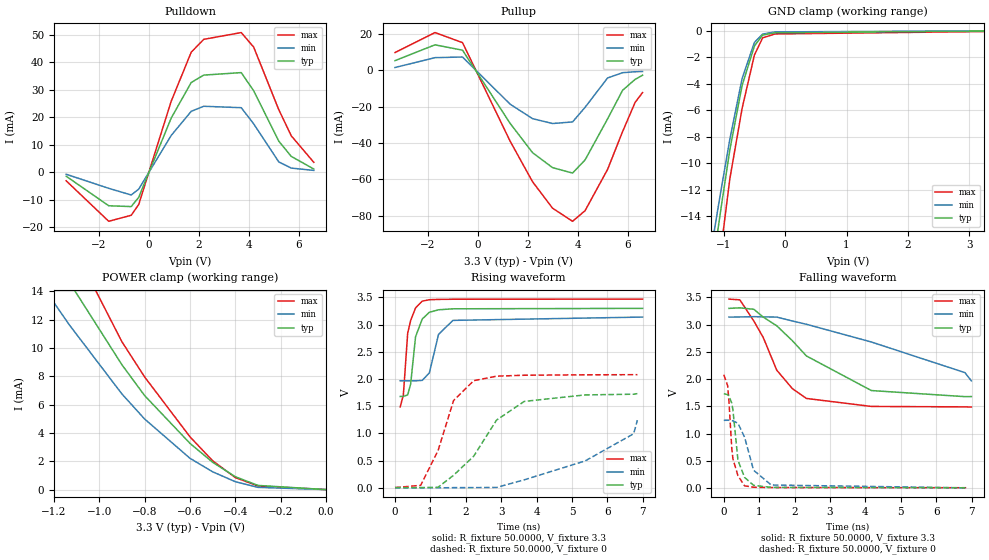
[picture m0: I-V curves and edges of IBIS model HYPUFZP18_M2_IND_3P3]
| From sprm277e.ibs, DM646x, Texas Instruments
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|Driver model in Slow Mode of operation, 1P8V +/-5% Operation
|   Model Cell HYPUFZP18_M2_IND_3P3
[Model]   HYPUFZP18_M2_IND_3P3
Model_type   I/O
Polarity   Non-Inverting
Enable   Active-Low
Vinl =  0.8V
Vinh =  2V
Cref =  10.0000pF
Rref =  50.0000
Vref =  1.5V
Vmeas =  1.65
C_comp   1.727272p   1.679637p   1.767235p
[Model Spec]
Vinl   0.8V   0.8V   0.8V
Vinh   2V   2V   2V
[Temperature Range]   25   125   -40
[Voltage Range]   3.3   3.14   3.47
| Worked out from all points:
|   slope of the pulldown table from 0 to 0.495 V, typ, clamps not added: 44 ohm
|   slope of the pullup table from 0 to 0.495 V, typ, clamps not added: 42.8 ohm
|   GND clamp passes 1 mA (typ) near -0.48 V on its own axis
|   POWER clamp passes 1 mA (typ) near -0.41 V on its own axis
|   rising waveform, R_fixture 50.0000, V_fixture 3.3: 20-80 % time 223ps typ, 314ps min, 181ps max; typ from 1.68 V to 3.3 V
|   rising waveform, R_fixture 50.0000, V_fixture 0: 20-80 % time 1.22ns typ, 2.54ns min, 685ps max; typ from 0.003 V to 1.73 V
|   falling waveform, R_fixture 50.0000, V_fixture 3.3: 20-80 % time 1.87ns typ, 3.47ns min, 1.01ns max; typ from 3.3 V to 1.68 V
|   falling waveform, R_fixture 50.0000, V_fixture 0: 20-80 % time 204ps typ, 362ps min, 167ps max; typ from 1.73 V to 0.003 V
[POWER_clamp]
|   voltage   I(typ)   I(min)   I(max)
-3.3V     86.16mA    64.93mA    104.3mA
-1.4V     22.2mA     18mA       26.83mA
-1.367V   21.21mA    17.19mA    25.68mA
-1.233V   17.39mA    13.98mA    21.08mA
-1.133V   14.68mA    11.66mA    17.73mA
-900mV    8.817mA    6.754mA    10.44mA
-800mV    6.639mA    4.986mA    7.957mA
-600mV    3.265mA    2.21mA     3.725mA
-500mV    1.929mA    1.256mA    2.033mA
-400mV    907.2uA    556.6uA    845.5uA
-300mV    294.6uA    156.7uA    257.4uA
0V        111.6nA    200.9nA    235nA
[Pulldown]
|   voltage   I(typ)   I(min)   I(max)
-3.3V     -1.512mA   -788.5uA   -3.18mA
-1.6V     -12.28mA   -5.92mA    -17.95mA
-700mV    -12.58mA   -8.352mA   -15.75mA
-400mV    -9.19mA    -6.204mA   -11.82mA
900mV     19.74mA    13.39mA    25.89mA
1.7V      32.7mA     22.18mA    43.75mA
2.2V      35.39mA    24.02mA    48.44mA
3.7V      36.3mA     23.5mA     50.91mA
4.2V      29.62mA    17.57mA    45.56mA
5.2V      11.29mA    3.716mA    22.78mA
5.7V      5.731mA    1.467mA    13.24mA
6.6V      1.129mA    616.6uA    3.57mA
[Pullup]
|   voltage   I(typ)   I(min)   I(max)
-3.3V     5.396mA    1.593mA    9.847mA
-1.7V     14.1mA     7.028mA    20.86mA
-600mV    11.14mA    7.391mA    15.31mA
1.3V      -29.12mA   -18.58mA   -38.91mA
2.2V      -45.34mA   -26.59mA   -61.37mA
3V        -53.59mA   -29.28mA   -75.95mA
3.8V      -56.59mA   -28.4mA    -83.18mA
4.3V      -49.37mA   -20.37mA   -77.34mA
5.2V      -26.74mA   -4.177mA   -54.59mA
5.8V      -10.98mA   -1.259mA   -33.78mA
6.3V      -4.973mA   -743uA     -17.68mA
6.6V      -2.651mA   -591uA     -12.21mA
[GND_clamp]
|   voltage   I(typ)   I(min)   I(max)
-3.3V     -101.9mA   -78.12mA   -120.9mA
-1.3V     -22.23mA   -19.37mA   -26.67mA
-1.233V   -19.8mA    -17.43mA   -23.98mA
-1.167V   -17.45mA   -15.5mA    -21.31mA
-1.1V     -15.2mA    -13.6mA    -18.66mA
-1.033V   -13.07mA   -11.75mA   -16.08mA
-900mV    -8.978mA   -8.176mA   -11.17mA
-700mV    -4.111mA   -3.59mA    -5.844mA
-500mV    -1.141mA   -866.9uA   -1.82mA
-366.7mV  -309.2uA   -237.7uA   -524.9uA
-166.7mV  -140.6uA   -73.41uA   -228.8uA
3.233V    -8.734uA   10uA       -45.21uA
[Ramp]
| variable   typ   min   max
dV/dt_f 0.98441839/1.9020411n 0.74512477/3.6718234n  1.2012952/1.0170093n
dV/dt_r  1.0409321/1.2292789n 0.75500684/2.5921283n  1.2504128/0.6862581n
R_load = 50
[Rising Waveform]
R_fixture = 50.0000
V_fixture = 3.3
V_fixture_min = 3.14
V_fixture_max = 3.47
|   time   V(typ)   V(min)   V(max)
146.9ps   1.68V      1.968V     1.487V
236.2ps   1.68V      1.968V     1.706V
358.8ps   1.709V     1.968V     2.845V
442.2ps   1.908V     1.968V     3.077V
581.3ps   2.779V     1.968V     3.309V
769.9ps   3.104V     1.975V     3.433V
971.3ps   3.228V     2.114V     3.459V
1.23ns    3.274V     2.821V     3.465V
1.637ns   3.292V     3.079V     3.468V
6.996ns   3.3V       3.14V      3.47V
[Rising Waveform]
R_fixture = 50.0000
V_fixture = 0
V_fixture_min = 0
V_fixture_max = 0
|   time   V(typ)   V(min)   V(max)
95.49fs   3.146mV    1.893mV    4.431mV
724.9ps   2.755mV    1.675mV    44.55mV
1.216ns   9.836mV    -1.558mV   683.1mV
1.656ns   230.3mV    2.632mV    1.605V
2.224ns   581.3mV    3.378mV    1.97V
2.872ns   1.247V     6.476mV    2.053V
3.654ns   1.589V     146.8mV    2.07V
5.371ns   1.708V     493.3mV    2.078V
6.744ns   1.721V     993.9mV    2.08V
6.849ns   1.732V     1.243V     2.081V
[Falling Waveform]
R_fixture = 50.0000
V_fixture = 3.3
V_fixture_min = 3.14
V_fixture_max = 3.47
|   time   V(typ)   V(min)   V(max)
146.9ps   3.3V       3.14V      3.47V
453.3ps   3.31V      3.142V     3.457V
850.2ps   3.283V     3.148V     3.066V
1.114ns   3.14V      3.144V     2.766V
1.496ns   2.98V      3.14V      2.165V
1.938ns   2.706V     3.068V     1.825V
2.334ns   2.426V     3.008V     1.645V
4.171ns   1.79V      2.682V     1.498V
6.815ns   1.678V     2.119V     1.49V
6.996ns   1.68V      1.968V     1.487V
[Falling Waveform]
R_fixture = 50.0000
V_fixture = 0
V_fixture_min = 0
V_fixture_max = 0
|   time   V(typ)   V(min)   V(max)
95.49fs   1.732V     1.243V     2.081V
109.4ps   1.714V     1.244V     1.878V
144.4ps   1.693V     1.244V     1.603V
224.4ps   1.56V      1.238V     739.2mV
257.7ps   1.436V     1.234V     535.1mV
400.6ps   507.2mV    1.188V     224.3mV
587.6ps   193.6mV    932.8mV    39.78mV
841.9ps   48.86mV    325.8mV    13.44mV
1.34ns    11.05mV    54.58mV    7.764mV
6.849ns   3.146mV    1.893mV    4.431mV
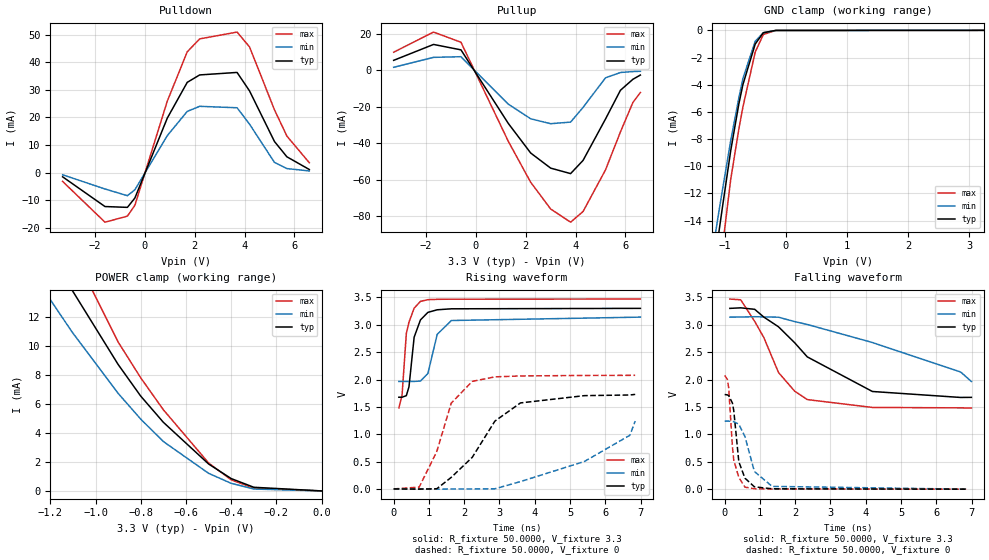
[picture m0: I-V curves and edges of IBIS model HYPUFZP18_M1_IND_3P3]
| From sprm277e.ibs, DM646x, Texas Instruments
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|   Model Cell HYPUFZP18_M1_IND_3P3
[Model]   HYPUFZP18_M1_IND_3P3
Model_type   I/O
Polarity   Non-Inverting
Enable   Active-Low
Vinl =  0.8V
Vinh =  2V
Cref =  10.0000pF
Rref =  50.0000
Vref =  1.5V
Vmeas =  1.65
C_comp   1.727272p   1.679637p   1.767235p
[Model Spec]
Vinl   0.8V   0.8V   0.8V
Vinh   2V   2V   2V
[Temperature Range]   25   125   -40
[Voltage Range]   3.3   3.14   3.47
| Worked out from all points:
|   slope of the pulldown table from 0 to 0.495 V, typ, clamps not added: 44 ohm
|   slope of the pullup table from 0 to 0.495 V, typ, clamps not added: 42.8 ohm
|   GND clamp passes 1 mA (typ) near -0.50 V on its own axis
|   POWER clamp passes 1 mA (typ) near -0.41 V on its own axis
|   rising waveform, R_fixture 50.0000, V_fixture 3.3: 20-80 % time 225ps typ, 315ps min, 183ps max; typ from 1.68 V to 3.3 V
|   rising waveform, R_fixture 50.0000, V_fixture 0: 20-80 % time 1.22ns typ, 2.49ns min, 683ps max; typ from 0 V to 1.73 V
|   falling waveform, R_fixture 50.0000, V_fixture 3.3: 20-80 % time 1.87ns typ, 3.46ns min, 1ns max; typ from 3.3 V to 1.68 V
|   falling waveform, R_fixture 50.0000, V_fixture 0: 20-80 % time 203ps typ, 361ps min, 165ps max; typ from 1.73 V to 0 V
[POWER_clamp]
|   voltage   I(typ)   I(min)   I(max)
-3.3V     86.16mA    64.93mA    104.3mA
-1.367V   21.2mA     17.18mA    25.66mA
-1.233V   17.37mA    13.97mA    21.04mA
-1.133V   14.66mA    11.65mA    17.64mA
-1.1V     13.77mA    10.89mA    16.52mA
-900mV    8.73mA     6.735mA    10.28mA
-800mV    6.543mA    4.955mA    7.805mA
-700mV    4.738mA    3.41mA     5.602mA
-500mV    1.861mA    1.216mA    1.931mA
-400mV    852uA      523.7uA    761.9uA
-300mV    252.5uA    131.8uA    194.2uA
0V        112.1nA    201.3nA    235.2nA
[Pulldown]
|   voltage   I(typ)   I(min)   I(max)
-3.3V     -1.512mA   -788.5uA   -3.18mA
-1.6V     -12.28mA   -5.92mA    -17.95mA
-700mV    -12.58mA   -8.352mA   -15.76mA
-400mV    -9.19mA    -6.205mA   -11.82mA
900mV     19.74mA    13.39mA    25.89mA
1.7V      32.7mA     22.18mA    43.75mA
2.2V      35.39mA    24.02mA    48.45mA
3.7V      36.3mA     23.5mA     50.91mA
4.2V      29.62mA    17.57mA    45.56mA
5.2V      11.29mA    3.716mA    22.78mA
5.7V      5.731mA    1.467mA    13.24mA
6.6V      1.129mA    616.6uA    3.57mA
[Pullup]
|   voltage   I(typ)   I(min)   I(max)
-3.3V     5.396mA    1.593mA    9.847mA
-1.7V     14.1mA     7.028mA    20.86mA
-600mV    11.14mA    7.391mA    15.31mA
1.3V      -29.12mA   -18.58mA   -38.91mA
2.2V      -45.34mA   -26.59mA   -61.37mA
3V        -53.59mA   -29.28mA   -75.95mA
3.8V      -56.59mA   -28.4mA    -83.18mA
4.3V      -49.37mA   -20.37mA   -77.34mA
5.2V      -26.74mA   -4.177mA   -54.59mA
5.8V      -10.98mA   -1.259mA   -33.78mA
6.3V      -4.973mA   -743uA     -17.68mA
6.6V      -2.651mA   -591uA     -12.21mA
[GND_clamp]
|   voltage   I(typ)   I(min)   I(max)
-3.3V     -101.7mA   -78.06mA   -120.7mA
-1.233V   -19.67mA   -17.36mA   -23.77mA
-1.167V   -17.33mA   -15.44mA   -21.11mA
-1.1V     -15.07mA   -13.53mA   -18.46mA
-1.033V   -12.94mA   -11.68mA   -15.87mA
-900mV    -8.85mA    -8.113mA   -10.96mA
-766.7mV  -5.397mA   -4.953mA   -7.245mA
-700mV    -3.976mA   -3.526mA   -5.621mA
-500mV    -1.005mA   -799.5uA   -1.597mA
-366.7mV  -173.3uA   -170.2uA   -302.3uA
-166.7mV  -4.974uA   -6.036uA   -6.587uA
3.233V    79.94nA    2.44uA     205.4nA
[Ramp]
| variable   typ   min   max
dV/dt_f 0.98699288/1.8980343n 0.74658914/3.6696309n   1.204652/1.0122786n
dV/dt_r  1.0418022/1.2286872n 0.75518748/2.5917648n  1.2520798/0.68561525n
R_load = 50
[Rising Waveform]
R_fixture = 50.0000
V_fixture = 3.3
V_fixture_min = 3.14
V_fixture_max = 3.47
|   time   V(typ)   V(min)   V(max)
147ps     1.676V     1.965V     1.481V
238ps     1.676V     1.965V     1.711V
359.3ps   1.705V     1.965V     2.839V
434.3ps   1.865V     1.965V     3.047V
580.9ps   2.773V     1.965V     3.304V
760.5ps   3.09V      1.971V     3.428V
971.3ps   3.227V     2.111V     3.459V
1.235ns   3.274V     2.825V     3.465V
1.637ns   3.292V     3.078V     3.468V
6.996ns   3.3V       3.14V      3.47V
[Rising Waveform]
R_fixture = 50.0000
V_fixture = 0
V_fixture_min = 0
V_fixture_max = 0
|   time   V(typ)   V(min)   V(max)
0s        38.03uV    22.53uV    59.66uV
724.4ps   -3.316mV   -195.8uV   33.46mV
1.224ns   3.693mV    -4.135mV   685.1mV
1.632ns   210.9mV    -771.5uV   1.567V
2.229ns   578.1mV    33.73uV    1.966V
2.871ns   1.24V      3.076mV    2.048V
3.596ns   1.572V     134.1mV    2.065V
5.411ns   1.705V     502.7mV    2.074V
6.7ns     1.717V     981.4mV    2.076V
6.849ns   1.728V     1.24V      2.077V
[Falling Waveform]
R_fixture = 50.0000
V_fixture = 3.3
V_fixture_min = 3.14
V_fixture_max = 3.47
|   time   V(typ)   V(min)   V(max)
147ps     3.3V       3.14V      3.47V
453.3ps   3.31V      3.142V     3.457V
850.2ps   3.283V     3.148V     3.063V
1.108ns   3.142V     3.144V     2.77V
1.525ns   2.964V     3.139V     2.13V
1.982ns   2.674V     3.059V     1.79V
2.343ns   2.414V     3.006V     1.635V
4.188ns   1.783V     2.677V     1.492V
6.692ns   1.674V     2.138V     1.484V
6.996ns   1.676V     1.965V     1.481V
[Falling Waveform]
R_fixture = 50.0000
V_fixture = 0
V_fixture_min = 0
V_fixture_max = 0
|   time   V(typ)   V(min)   V(max)
0s        1.728V     1.24V      2.077V
75.14ps   1.721V     1.242V     2.002V
112.4ps   1.709V     1.242V     1.855V
218.9ps   1.572V     1.236V     779.8mV
257.1ps   1.435V     1.232V     529.4mV
400.6ps   501.1mV    1.186V     214.3mV
573.9ps   200.9mV    960.8mV    36.89mV
842.1ps   42.86mV    322.7mV    7.839mV
1.343ns   6.854mV    50.74mV    2.674mV
6.849ns   38.03uV    22.53uV    59.66uV
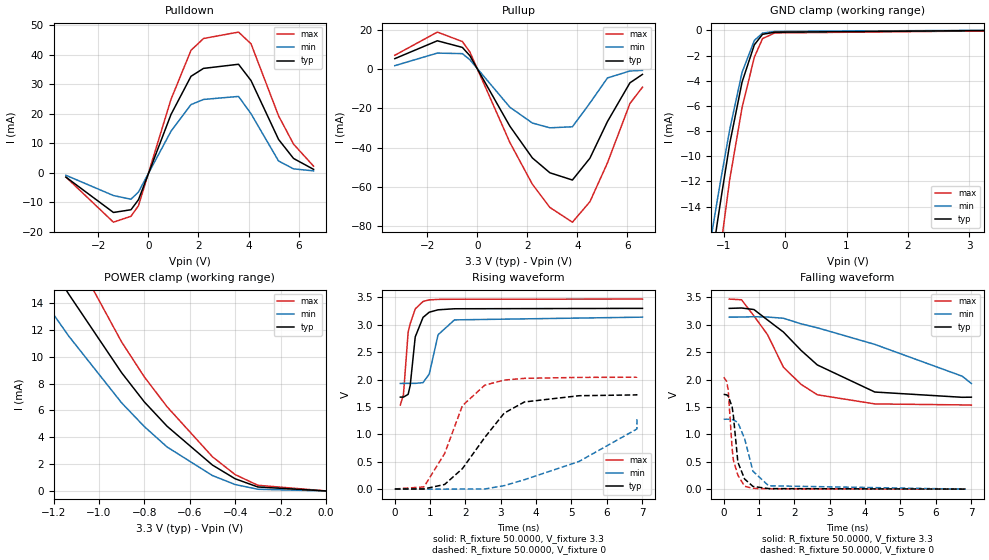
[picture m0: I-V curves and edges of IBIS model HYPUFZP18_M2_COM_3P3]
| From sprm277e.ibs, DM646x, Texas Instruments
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|   Model Cell HYPUFZP18_M2_COM_3P3
[Model]   HYPUFZP18_M2_COM_3P3
Model_type   I/O
Polarity   Non-Inverting
Enable   Active-Low
Vinl =  0.8V
Vinh =  2V
Cref =  10.0000pF
Rref =  50.0000
Vref =  1.5V
Vmeas =  1.65
C_comp   1.727272p   1.681011p   1.768042p
[Model Spec]
Vinl   0.8V   0.8V   0.8V
Vinh   2V   2V   2V
[Temperature Range]   25   105   0
[Voltage Range]   3.3   3.14   3.47
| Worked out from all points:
|   slope of the pulldown table from 0 to 0.495 V, typ, clamps not added: 44 ohm
|   slope of the pullup table from 0 to 0.495 V, typ, clamps not added: 42.8 ohm
|   GND clamp passes 1 mA (typ) near -0.48 V on its own axis
|   POWER clamp passes 1 mA (typ) near -0.41 V on its own axis
|   rising waveform, R_fixture 50.0000, V_fixture 3.3: 20-80 % time 223ps typ, 309ps min, 188ps max; typ from 1.68 V to 3.3 V
|   rising waveform, R_fixture 50.0000, V_fixture 0: 20-80 % time 1.22ns typ, 2.4ns min, 842ps max; typ from 0.003 V to 1.73 V
|   falling waveform, R_fixture 50.0000, V_fixture 3.3: 20-80 % time 1.88ns typ, 3.36ns min, 1.22ns max; typ from 3.3 V to 1.68 V
|   falling waveform, R_fixture 50.0000, V_fixture 0: 20-80 % time 204ps typ, 351ps min, 171ps max; typ from 1.73 V to 0.003 V
[POWER_clamp]
|   voltage   I(typ)   I(min)   I(max)
-3.3V     86.16mA    67.13mA    105mA
-1.433V   23.25mA    19mA       28.67mA
-1.4V     22.2mA     18.14mA    27.44mA
-1.267V   18.31mA    14.78mA    22.82mA
-1.133V   14.68mA    11.55mA    18.37mA
-900mV    8.817mA    6.569mA    11.11mA
-800mV    6.639mA    4.799mA    8.503mA
-700mV    4.827mA    3.28mA     6.281mA
-500mV    1.929mA    1.146mA    2.549mA
-400mV    907.2uA    478uA      1.218mA
-300mV    294.5uA    124.1uA    421.8uA
0V        111.6nA    122.2nA    531.1nA
[Pulldown]
|   voltage   I(typ)   I(min)   I(max)
-3.3V     -1.512mA   -878.6uA   -1.478mA
-1.4V     -13.5mA    -7.754mA   -16.8mA
-700mV    -12.58mA   -9.011mA   -14.79mA
-400mV    -9.19mA    -6.568mA   -11.22mA
900mV     19.74mA    14.05mA    24.87mA
1.7V      32.7mA     23.1mA     41.52mA
2.2V      35.39mA    24.85mA    45.53mA
3.6V      36.79mA    25.88mA    47.71mA
4.1V      31.25mA    19.99mA    43.72mA
5.2V      11.29mA    3.971mA    19.31mA
5.8V      4.817mA    1.297mA    9.688mA
6.6V      1.129mA    610.1uA    2.216mA
[Pullup]
|   voltage   I(typ)   I(min)   I(max)
-3.3V     5.397mA    1.812mA    7.127mA
-1.6V     14.52mA    8.233mA    18.96mA
-600mV    11.14mA    7.955mA    14.14mA
-300mV    6.902mA    4.842mA    8.811mA
1.3V      -29.12mA   -19.41mA   -37.45mA
2.2V      -45.34mA   -27.5mA    -58.77mA
2.9V      -52.91mA   -29.94mA   -70.62mA
3.8V      -56.6mA    -29.4mA    -78.14mA
4.5V      -45.44mA   -17.28mA   -67.66mA
5.2V      -26.74mA   -4.474mA   -47.85mA
6.1V      -6.94mA    -895.2uA   -17.5mA
6.6V      -2.652mA   -585.1uA   -9.182mA
[GND_clamp]
|   voltage   I(typ)   I(min)   I(max)
-3.3V     -101.9mA   -80.83mA   -121.5mA
-1.3V     -22.23mA   -19.42mA   -27.13mA
-1.233V   -19.8mA    -17.39mA   -24.45mA
-1.167V   -17.45mA   -15.39mA   -21.82mA
-1.1V     -15.2mA    -13.41mA   -19.23mA
-1.033V   -13.07mA   -11.5mA    -16.71mA
-900mV    -8.978mA   -7.863mA   -11.83mA
-700mV    -4.111mA   -3.334mA   -6.141mA
-500mV    -1.141mA   -794.5uA   -2.129mA
-366.7mV  -309.2uA   -210.5uA   -650.5uA
-166.7mV  -140.6uA   -75.05uA   -198.7uA
3.233V    -8.733uA   9.396uA    -38.37uA
[Ramp]
| variable   typ   min   max
dV/dt_f   0.984392/1.9018313n 0.76805453/3.5496673n  1.1728981/1.2350833n
dV/dt_r  1.0409375/1.2292146n 0.77628069/2.4455529n  1.2301703/0.84780407n
R_load = 50
[Rising Waveform]
R_fixture = 50.0000
V_fixture = 3.3
V_fixture_min = 3.14
V_fixture_max = 3.47
|   time   V(typ)   V(min)   V(max)
158.4ps   1.68V      1.93V      1.535V
247.4ps   1.681V     1.931V     1.73V
379.4ps   1.731V     1.931V     2.865V
438.3ps   1.895V     1.931V     3.021V
580ps     2.779V     1.931V     3.29V
801.3ps   3.136V     1.945V     3.426V
976.5ps   3.23V      2.102V     3.455V
1.226ns   3.274V     2.818V     3.464V
1.69ns    3.293V     3.09V      3.467V
7.008ns   3.3V       3.14V      3.47V
[Rising Waveform]
R_fixture = 50.0000
V_fixture = 0
V_fixture_min = 0
V_fixture_max = 0
|   time   V(typ)   V(min)   V(max)
2.236ps   3.146mV    1.93mV     3.847mV
826.7ps   4.911mV    1.344mV    41.58mV
1.411ns   85.98mV    353.5uV    650.1mV
1.915ns   375.2mV    3.413mV    1.525V
2.548ns   944.8mV    3.815mV    1.899V
3.096ns   1.388V     64.44mV    1.991V
3.668ns   1.592V     172.7mV    2.023V
5.214ns   1.706V     506.2mV    2.04V
6.85ns    1.721V     1.099V     2.044V
6.852ns   1.732V     1.277V     2.046V
[Falling Waveform]
R_fixture = 50.0000
V_fixture = 3.3
V_fixture_min = 3.14
V_fixture_max = 3.47
|   time   V(typ)   V(min)   V(max)
158.4ps   3.3V       3.14V      3.47V
506.2ps   3.307V     3.142V     3.457V
857.7ps   3.279V     3.148V     3.162V
1.244ns   3.087V     3.142V     2.819V
1.692ns   2.868V     3.12V      2.226V
2.191ns   2.534V     3.018V     1.914V
2.651ns   2.268V     2.946V     1.724V
4.277ns   1.774V     2.643V     1.557V
6.749ns   1.678V     2.063V     1.539V
7.008ns   1.68V      1.93V      1.535V
[Falling Waveform]
R_fixture = 50.0000
V_fixture = 0
V_fixture_min = 0
V_fixture_max = 0
|   time   V(typ)   V(min)   V(max)
2.236ps   1.732V     1.277V     2.046V
84.64ps   1.722V     1.279V     1.971V
129.1ps   1.703V     1.278V     1.813V
241.5ps   1.5V       1.271V     737mV
276.7ps   1.338V     1.265V     532.2mV
403.4ps   493.2mV    1.219V     256.1mV
594.2ps   186.6mV    921.7mV    54.7mV
829.9ps   52.15mV    329.2mV    15.68mV
1.274ns   12.09mV    63.13mV    8.24mV
6.852ns   3.146mV    1.93mV     3.847mV
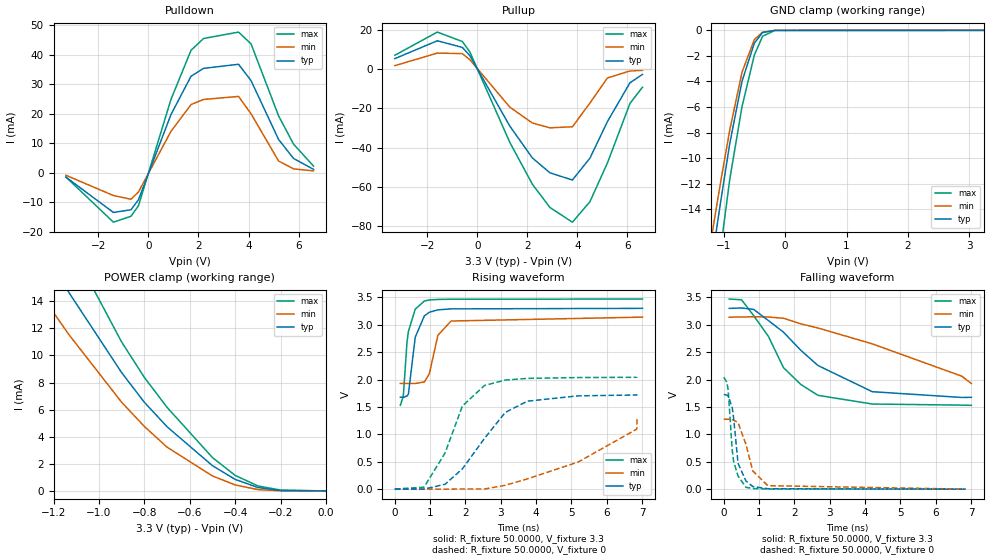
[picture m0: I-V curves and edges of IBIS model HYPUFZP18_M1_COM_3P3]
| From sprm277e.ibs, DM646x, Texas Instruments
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|   Model Cell HYPUFZP18_M1_COM_3P3
[Model]   HYPUFZP18_M1_COM_3P3
Model_type   I/O
Polarity   Non-Inverting
Enable   Active-Low
Vinl =  0.8V
Vinh =  2V
Cref =  10.0000pF
Rref =  50.0000
Vref =  1.5V
Vmeas =  1.65
C_comp   1.727272p   1.681011p   1.768042p
[Model Spec]
Vinl   0.8V   0.8V   0.8V
Vinh   2V   2V   2V
[Temperature Range]   25   105   0
[Voltage Range]   3.3   3.14   3.47
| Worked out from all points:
|   slope of the pulldown table from 0 to 0.495 V, typ, clamps not added: 44 ohm
|   slope of the pullup table from 0 to 0.495 V, typ, clamps not added: 42.8 ohm
|   GND clamp passes 1 mA (typ) near -0.50 V on its own axis
|   POWER clamp passes 1 mA (typ) near -0.41 V on its own axis
|   rising waveform, R_fixture 50.0000, V_fixture 3.3: 20-80 % time 225ps typ, 310ps min, 190ps max; typ from 1.68 V to 3.3 V
|   rising waveform, R_fixture 50.0000, V_fixture 0: 20-80 % time 1.22ns typ, 2.4ns min, 841ps max; typ from 0 V to 1.73 V
|   falling waveform, R_fixture 50.0000, V_fixture 3.3: 20-80 % time 1.87ns typ, 3.36ns min, 1.22ns max; typ from 3.3 V to 1.68 V
|   falling waveform, R_fixture 50.0000, V_fixture 0: 20-80 % time 203ps typ, 351ps min, 170ps max; typ from 1.73 V to 0 V
[POWER_clamp]
|   voltage   I(typ)   I(min)   I(max)
-3.3V     86.16mA    67.13mA    105mA
-1.4V     22.19mA    18.14mA    27.42mA
-1.267V   18.3mA     14.77mA    22.8mA
-1.133V   14.66mA    11.55mA    18.33mA
-900mV    8.73mA     6.544mA    10.99mA
-800mV    6.543mA    4.759mA    8.378mA
-700mV    4.738mA    3.23mA     6.168mA
-500mV    1.861mA    1.104mA    2.464mA
-400mV    852uA      443.1uA    1.148mA
-300mV    252.5uA    97.77uA    368.3uA
-200mV    33.02uA    10.49uA    62.16uA
0V        112.1nA    122.4nA    532.4nA
[Pulldown]
|   voltage   I(typ)   I(min)   I(max)
-3.3V     -1.512mA   -878.6uA   -1.478mA
-1.4V     -13.5mA    -7.754mA   -16.8mA
-700mV    -12.58mA   -9.011mA   -14.79mA
-400mV    -9.19mA    -6.568mA   -11.22mA
900mV     19.74mA    14.05mA    24.87mA
1.7V      32.7mA     23.1mA     41.52mA
2.2V      35.39mA    24.85mA    45.53mA
3.6V      36.79mA    25.88mA    47.71mA
4.1V      31.25mA    19.99mA    43.72mA
5.2V      11.29mA    3.971mA    19.31mA
5.8V      4.817mA    1.297mA    9.688mA
6.6V      1.129mA    610.1uA    2.216mA
[Pullup]
|   voltage   I(typ)   I(min)   I(max)
-3.3V     5.397mA    1.812mA    7.127mA
-1.6V     14.52mA    8.233mA    18.96mA
-600mV    11.14mA    7.955mA    14.14mA
-300mV    6.902mA    4.842mA    8.811mA
1.3V      -29.12mA   -19.41mA   -37.45mA
2.2V      -45.34mA   -27.5mA    -58.77mA
2.9V      -52.91mA   -29.94mA   -70.62mA
3.8V      -56.6mA    -29.4mA    -78.14mA
4.5V      -45.44mA   -17.28mA   -67.66mA
5.2V      -26.74mA   -4.474mA   -47.85mA
6.1V      -6.939mA   -895.2uA   -17.5mA
6.6V      -2.652mA   -585.1uA   -9.182mA
[GND_clamp]
|   voltage   I(typ)   I(min)   I(max)
-3.3V     -101.7mA   -80.77mA   -121.3mA
-1.3V     -22.1mA    -19.35mA   -26.96mA
-1.233V   -19.67mA   -17.33mA   -24.27mA
-1.167V   -17.33mA   -15.32mA   -21.64mA
-1.1V     -15.07mA   -13.35mA   -19.05mA
-1.033V   -12.94mA   -11.44mA   -16.53mA
-900mV    -8.849mA   -7.798mA   -11.65mA
-700mV    -3.976mA   -3.266mA   -5.954mA
-500mV    -1.005mA   -723.9uA   -1.94mA
-366.7mV  -173.3uA   -140uA     -461.5uA
-166.7mV  -4.974uA   -4.702uA   -10.03uA
3.233V    79.94nA    1.449uA    399.8nA
[Ramp]
| variable   typ   min   max
dV/dt_f 0.98696343/1.8977835n 0.76958064/3.5474193n  1.1759279/1.2301136n
dV/dt_r  1.0418135/1.2286609n 0.77649287/2.4452071n  1.2315165/0.84717372n
R_load = 50
[Rising Waveform]
R_fixture = 50.0000
V_fixture = 3.3
V_fixture_min = 3.14
V_fixture_max = 3.47
|   time   V(typ)   V(min)   V(max)
158.5ps   1.676V     1.928V     1.53V
242.7ps   1.676V     1.928V     1.697V
348ps     1.698V     1.928V     2.693V
387.2ps   1.737V     1.928V     2.88V
580.1ps   2.774V     1.928V     3.285V
837.3ps   3.162V     1.955V     3.434V
978.4ps   3.229V     2.104V     3.454V
1.221ns   3.273V     2.808V     3.463V
1.594ns   3.291V     3.069V     3.467V
7.008ns   3.3V       3.14V      3.47V
[Rising Waveform]
R_fixture = 50.0000
V_fixture = 0
V_fixture_min = 0
V_fixture_max = 0
|   time   V(typ)   V(min)   V(max)
2.154ps   38.03uV    21.16uV    59.4uV
827.1ps   -1.482mV   -578.1uV   32.76mV
1.423ns   86.82mV    -2.717mV   656.8mV
1.914ns   368.2mV    -63.3uV    1.517V
2.541ns   926.3mV    292.9uV    1.892V
3.127ns   1.399V     68.24mV    1.99V
3.754ns   1.605V     185.9mV    2.021V
5.189ns   1.702V     492.7mV    2.036V
6.85ns    1.718V     1.096V     2.041V
6.851ns   1.728V     1.275V     2.043V
[Falling Waveform]
R_fixture = 50.0000
V_fixture = 3.3
V_fixture_min = 3.14
V_fixture_max = 3.47
|   time   V(typ)   V(min)   V(max)
158.5ps   3.3V       3.14V      3.47V
506.2ps   3.307V     3.142V     3.457V
849.3ps   3.282V     3.148V     3.168V
1.267ns   3.077V     3.142V     2.789V
1.692ns   2.866V     3.12V      2.219V
2.185ns   2.534V     3.018V     1.91V
2.668ns   2.257V     2.942V     1.713V
4.207ns   1.779V     2.652V     1.554V
6.738ns   1.674V     2.062V     1.534V
7.008ns   1.676V     1.928V     1.53V
[Falling Waveform]
R_fixture = 50.0000
V_fixture = 0
V_fixture_min = 0
V_fixture_max = 0
|   time   V(typ)   V(min)   V(max)
2.154ps   1.728V     1.275V     2.043V
90.59ps   1.717V     1.276V     1.954V
129.1ps   1.7V       1.276V     1.808V
241.5ps   1.495V     1.268V     728.6mV
281.3ps   1.308V     1.262V     510.7mV
407.7ps   472.2mV    1.214V     240.8mV
630.3ps   150.2mV    820.5mV    34.45mV
824.3ps   47.91mV    333.2mV    10.65mV
1.25ns    8.222mV    63.96mV    3.812mV
6.851ns   38.03uV    21.16uV    59.4uV
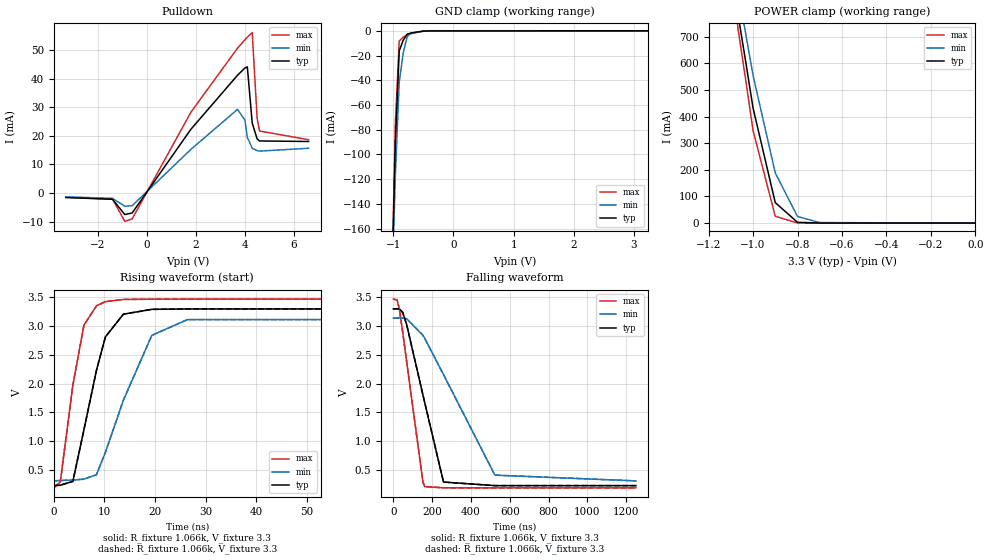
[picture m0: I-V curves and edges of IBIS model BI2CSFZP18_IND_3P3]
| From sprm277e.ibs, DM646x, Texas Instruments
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|   Model Cell BI2CSFZP18_IND_3P3
[Model]   BI2CSFZP18_IND_3P3
Model_type   I/O_open_drain
Polarity   Non-Inverting
Enable   Active-Low
Vinl =  0.99
Vinh =  2.31
Cref =  400pF
Rref =  1.066k
Vref =  1.8V
Vmeas =  1.65
C_comp   1.488594p   1.349892p   1.621248p
[Model Spec]
Vinl   0.99   0.942   1.041
Vinh   2.31   2.198   2.429
[Temperature Range]   25   125   -40
[Voltage Range]   3.3   3.14   3.47
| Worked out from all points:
|   slope of the pulldown table from 0 to 0.495 V, typ, clamps not added: 76.9 ohm
|   GND clamp passes 1 mA (typ) near -0.62 V on its own axis
|   POWER clamp passes 1 mA (typ) near -0.73 V on its own axis
|   rising waveform, R_fixture 1.066k, V_fixture 3.3: 20-80 % time 4.58ns typ, 7.2ns min, 3.21ns max; typ from 0.221 V to 3.3 V
|   rising waveform, R_fixture 1.066k, V_fixture 3.3: 20-80 % time 4.58ns typ, 7.2ns min, 3.21ns max; typ from 0.221 V to 3.3 V
|   falling waveform, R_fixture 1.066k, V_fixture 3.3: 20-80 % time 126ns typ, 253ns min, 79.7ns max; typ from 3.3 V to 0.221 V
|   falling waveform, R_fixture 1.066k, V_fixture 3.3: 20-80 % time 126ns typ, 253ns min, 79.7ns max; typ from 3.3 V to 0.221 V
[POWER_clamp]
|   voltage   I(typ)   I(min)   I(max)
-3.3V     15.05A     13.64A     16.17A
-1.067V   781.2mA    867.7mA    727.6mA
-1.033V   606.9mA    711.6mA    538mA
-1V       432.7mA    555.5mA    348.4mA
-900mV    76.75mA    188.3mA    25.46mA
-800mV    2.774mA    24.69mA    252.5uA
-700mV    66.53uA    1.695mA    2.137uA
0V        40.21nA    40.76nA    94nA
[Pulldown]
|   voltage   I(typ)   I(min)   I(max)
-3.3V     -1.585mA   -1.346mA   -1.531mA
-1.4V     -2.213mA   -1.889mA   -2.158mA
-900mV    -7.541mA   -4.635mA   -9.916mA
-600mV    -7.019mA   -4.472mA   -9.091mA
1.8V      22.32mA    15.27mA    28.29mA
3.7V      41.2mA     29.25mA    50.67mA
4V        43.73mA    25.55mA    53.59mA
4.1V      44.15mA    19.45mA    54.54mA
4.3V      24.45mA    15.65mA    56.14mA
4.5V      18.92mA    14.81mA    26.17mA
4.6V      18.2mA     14.65mA    21.68mA
6.6V      18.02mA    15.65mA    18.64mA
[GND_clamp]
|   voltage   I(typ)   I(min)   I(max)
-3.3V     -17.3A     -15.65A    -18.51A
-1.033V   -228.3mA   -233.3mA   -231.9mA
-966.7mV  -93.1mA    -119.6mA   -77.04mA
-900mV    -16.18mA   -41.41mA   -8.144mA
-833.3mV  -7.484mA   -17.78mA   -5.09mA
-766.7mV  -2.666mA   -4.584mA   -3.099mA
-700mV    -1.721mA   -1.808mA   -2.172mA
-500mV    -222.6uA   -326.8uA   -246.3uA
-366.7mV  -16.95uA   -49.29uA   -14.91uA
3.233V    39.65nA    41.75nA    88.83nA
[Ramp]
| variable   typ   min   max
dV/dt_f  1.7339576/0.13001354u  1.5510461/0.26044462u  1.8799555/81.619392n
dV/dt_r 13.711008m/1.120079n  8.3530201m/2.632613n  19.501467m/0.66262005n
R_load = 528
[Rising Waveform]
R_fixture = 1.066k
V_fixture = 3.3
V_fixture_min = 3.14
V_fixture_max = 3.47
|   time   V(typ)   V(min)   V(max)
0s        220.8mV    303.5mV    182.1mV
1.28ns    228.8mV    310.6mV    285mV
3.755ns   294mV      318.4mV    1.97V
5.955ns   1.198V     333.8mV    3.019V
8.425ns   2.232V     412.1mV    3.354V
10.19ns   2.813V     802.3mV    3.427V
13.74ns   3.208V     1.71V      3.464V
19.34ns   3.292V     2.838V     3.469V
26.35ns   3.299V     3.113V     3.47V
1.25us    3.3V       3.14V      3.47V
[Rising Waveform]
R_fixture = 1.066k
V_fixture = 3.3
V_fixture_min = 3.14
V_fixture_max = 3.47
|   time   V(typ)   V(min)   V(max)
0s        220.8mV    303.5mV    182.1mV
1.28ns    228.8mV    310.6mV    285mV
3.755ns   294mV      318.4mV    1.97V
5.955ns   1.198V     333.8mV    3.019V
8.425ns   2.232V     412.1mV    3.354V
10.19ns   2.813V     802.3mV    3.427V
13.74ns   3.208V     1.71V      3.464V
19.34ns   3.292V     2.838V     3.469V
26.35ns   3.299V     3.113V     3.47V
1.25us    3.3V       3.14V      3.47V
[Falling Waveform]
R_fixture = 1.066k
V_fixture = 3.3
V_fixture_min = 3.14
V_fixture_max = 3.47
|   time   V(typ)   V(min)   V(max)
0s        3.3V       3.14V      3.47V
19.62ns   3.302V     3.141V     3.457V
31.73ns   3.298V     3.141V     3.287V
48.39ns   3.239V     3.139V     2.896V
68.52ns   3.03V      3.129V     2.385V
152.7ns   1.799V     2.839V     281.9mV
161.7ns   1.67V      2.787V     203.6mV
258.5ns   283.3mV    2.157V     182.9mV
523.3ns   221mV      403.6mV    182.1mV
1.25us    220.8mV    303.5mV    182.1mV
[Falling Waveform]
R_fixture = 1.066k
V_fixture = 3.3
V_fixture_min = 3.14
V_fixture_max = 3.47
|   time   V(typ)   V(min)   V(max)
0s        3.3V       3.14V      3.47V
19.62ns   3.302V     3.141V     3.457V
31.73ns   3.298V     3.141V     3.287V
48.39ns   3.239V     3.139V     2.896V
68.52ns   3.03V      3.129V     2.385V
152.7ns   1.799V     2.839V     281.9mV
161.7ns   1.67V      2.787V     203.6mV
258.5ns   283.3mV    2.157V     182.9mV
523.3ns   221mV      403.6mV    182.1mV
1.25us    220.8mV    303.5mV    182.1mV
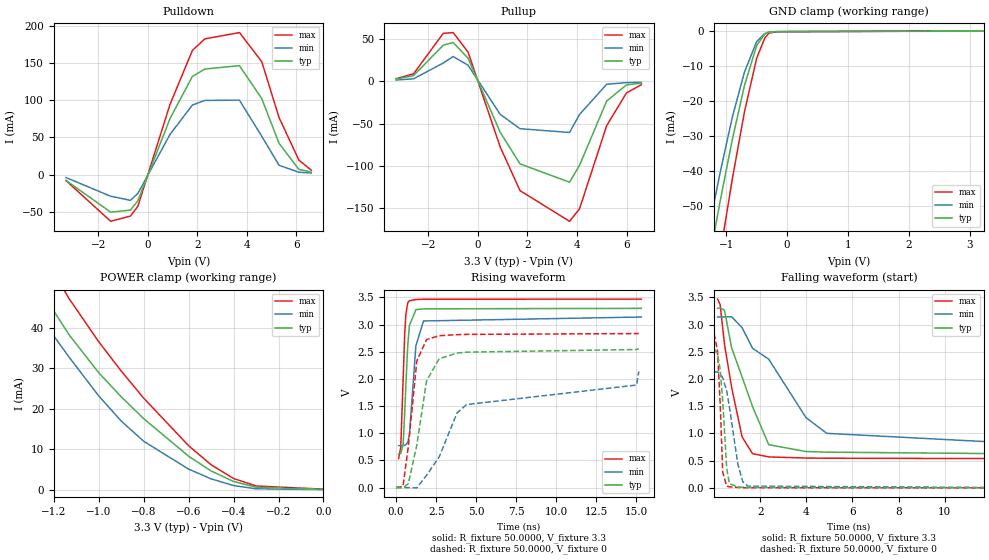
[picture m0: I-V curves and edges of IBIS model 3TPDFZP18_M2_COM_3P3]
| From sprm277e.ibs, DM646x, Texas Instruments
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|   Model Cell 3TPDFZP18_M2_COM_3P3
|BPCI33TPDFZP18_M2_COM_3P3
[Model]   3TPDFZP18_M2_COM_3P3
Model_type   I/O
Polarity   Non-Inverting
Enable   Active-Low
Vinl =  0.99V
Vinh =  1.65V
Cref =  10.0000pF
Rref =  50.0000
Vref =  1.5V
Vmeas =  1.65
C_comp   3.400798p   3.35082p   3.526617p
[Model Spec]
Vinl   0.99V   0.942V   1.041V
Vinh   1.65V   1.570V   1.735V
[Temperature Range]   25   105   0
[Voltage Range]   3.3   3.14   3.47
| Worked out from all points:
|   slope of the pulldown table from 0 to 0.495 V, typ, clamps not added: 11.5 ohm
|   slope of the pullup table from 0 to 0.495 V, typ, clamps not added: 14.2 ohm
|   GND clamp passes 1 mA (typ) near -0.38 V on its own axis
|   POWER clamp passes 1 mA (typ) near -0.32 V on its own axis
|   rising waveform, R_fixture 50.0000, V_fixture 3.3: 20-80 % time 257ps typ, 345ps min, 208ps max; typ from 0.618 V to 3.3 V
|   rising waveform, R_fixture 50.0000, V_fixture 0: 20-80 % time 905ps typ, 6.35ns min, 575ps max; typ from 0 V to 2.56 V
|   falling waveform, R_fixture 50.0000, V_fixture 3.3: 20-80 % time 1.25ns typ, 2.59ns min, 741ps max; typ from 3.3 V to 0.618 V
|   falling waveform, R_fixture 50.0000, V_fixture 0: 20-80 % time 227ps typ, 454ps min, 150ps max; typ from 2.56 V to 0 V
[POWER_clamp]
|   voltage   I(typ)   I(min)   I(max)
-3.3V     267mA      206.5mA    325.9mA
-1.333V   56.8mA     48.39mA    68.28mA
-1.233V   46.92mA    40.45mA    56.76mA
-1.133V   38.28mA    32.77mA    47.2mA
-1V       28.86mA    23.16mA    36.48mA
-900mV    22.94mA    16.96mA    29.27mA
-800mV    17.55mA    11.99mA    22.6mA
-600mV    8.297mA    5.123mA    10.88mA
-500mV    4.676mA    2.728mA    6.199mA
-400mV    2.081mA    1.079mA    2.81mA
-300mV    677.7uA    289.8uA    977uA
0V        143.1uA    86.94uA    197.4uA
[Pulldown]
|   voltage   I(typ)   I(min)   I(max)
-3.3V     -7.787mA   -3.888mA   -7.985mA
-1.5V     -50.3mA    -28.94mA   -62.59mA
-700mV    -47.57mA   -34.42mA   -55.53mA
-400mV    -34.9mA    -25.14mA   -42.3mA
900mV     75.57mA    54.22mA    94.65mA
1.8V      131.8mA    93.47mA    166.8mA
2.3V      141.8mA    99.67mA    182.3mA
3.7V      146.4mA    100.1mA    190.8mA
4.6V      102.2mA    51.62mA    151.8mA
5.3V      42.11mA    12.62mA    76.69mA
6.1V      7.062mA    3.321mA    19.67mA
6.6V      3.543mA    2.232mA    5.962mA
[Pullup]
|   voltage   I(typ)   I(min)   I(max)
-3.3V     2.841mA    1.735mA    3.327mA
-2.6V     6.94mA     3.146mA    9.053mA
-1.4V     43.04mA    21.89mA    57.16mA
-1V       46.23mA    29.6mA     58.04mA
-400mV    27.62mA    19.3mA     34.95mA
900mV     -60.4mA    -39.07mA   -77.82mA
1.7V      -97.84mA   -56.07mA   -129.6mA
3.7V      -119.6mA   -60.58mA   -166mA
4.1V      -99.72mA   -39.32mA   -151.4mA
5.2V      -23.22mA   -3.285mA   -52.37mA
6V        -4.027mA   -1.402mA   -13.57mA
6.6V      -2.032mA   -942.8uA   -3.85mA
[GND_clamp]
|   voltage   I(typ)   I(min)   I(max)
-3.3V     -301.2mA   -235.6mA   -364.4mA
-1.367V   -75.51mA   -63.63mA   -93.99mA
-1.3V     -68.15mA   -57.67mA   -85.99mA
-1.233V   -61.35mA   -51.8mA    -78.43mA
-1.1V     -48.52mA   -40.32mA   -63.59mA
-900mV    -30.93mA   -24.51mA   -42.17mA
-700mV    -15.41mA   -11.59mA   -22.96mA
-500mV    -4.036mA   -2.901mA   -7.657mA
-366.7mV  -757uA     -601.1uA   -1.906mA
-300mV    -173.8uA   -161.6uA   -469.5uA
-166.7mV  -45.04uA   -35.14uA   -70.3uA
3.233V    143uA      89.63uA    196.9uA
[Ramp]
| variable   typ   min   max
dV/dt_f  1.6129021/1.248522n   1.4235696/2.5918886n  1.7639899/0.74162486n
dV/dt_r   1.539227/0.90708009n  1.2863475/4.9184263n  1.7058563/0.5763429n
R_load = 50
[Rising Waveform]
R_fixture = 50.0000
V_fixture = 3.3
V_fixture_min = 3.14
V_fixture_max = 3.47
|   time   V(typ)   V(min)   V(max)
155.6ps   617.6mV    771.5mV    534.9mV
285.5ps   627.7mV    771.6mV    739.5mV
436.9ps   802.4mV    771.5mV    2.005V
535.7ps   1.392V     776.1mV    2.84V
608.4ps   1.897V     787.7mV    3.196V
725.9ps   2.629V     831.4mV    3.4V
828.5ps   2.981V     972.5mV    3.439V
1.232ns   3.275V     2.609V     3.461V
1.707ns   3.289V     3.066V     3.466V
15.31ns   3.298V     3.139V     3.468V
[Rising Waveform]
R_fixture = 50.0000
V_fixture = 0
V_fixture_min = 0
V_fixture_max = 0
|   time   V(typ)   V(min)   V(max)
2.755ps   22.7uV     15.94uV    32.12uV
428.3ps   -3.666mV   -41.09uV   24.96mV
756.9ps   70.78mV    -1.983mV   747.6mV
1.289ns   780.7mV    -5.473mV   2.33V
1.896ns   1.963V     225.9mV    2.723V
2.688ns   2.371V     565.8mV    2.795V
3.799ns   2.475V     1.372V     2.814V
4.391ns   2.492V     1.527V     2.819V
15.01ns   2.541V     1.887V     2.834V
15.15ns   2.555V     2.134V     2.835V
[Falling Waveform]
R_fixture = 50.0000
V_fixture = 3.3
V_fixture_min = 3.14
V_fixture_max = 3.47
|   time   V(typ)   V(min)   V(max)
155.6ps   3.298V     3.139V     3.468V
265.5ps   3.305V     3.141V     3.368V
453.9ps   3.266V     3.141V     2.642V
760.9ps   2.577V     3.144V     1.852V
1.217ns   2.038V     2.945V     936.6mV
1.672ns   1.492V     2.564V     627.9mV
2.372ns   793mV      2.365V     568.6mV
3.986ns   667.9mV    1.292V     548mV
4.885ns   656.2mV    1.002V     544.7mV
15.31ns   617.6mV    771.5mV    534.9mV
[Falling Waveform]
R_fixture = 50.0000
V_fixture = 0
V_fixture_min = 0
V_fixture_max = 0
|   time   V(typ)   V(min)   V(max)
2.755ps   2.555V     2.134V     2.835V
152.8ps   2.471V     2.128V     2.519V
270.6ps   2.161V     2.092V     1.519V
377.2ps   1.603V     2.023V     287.5mV
549.9ps   359.6mV    1.783V     31.48mV
665.5ps   78.15mV    1.493V     19.4mV
1.034ns   15.99mV    433.4mV    7.066mV
1.248ns   11.71mV    112.3mV    3.615mV
1.462ns   8.64mV     31.83mV    2.235mV
15.15ns   22.7uV     15.94uV    32.12uV
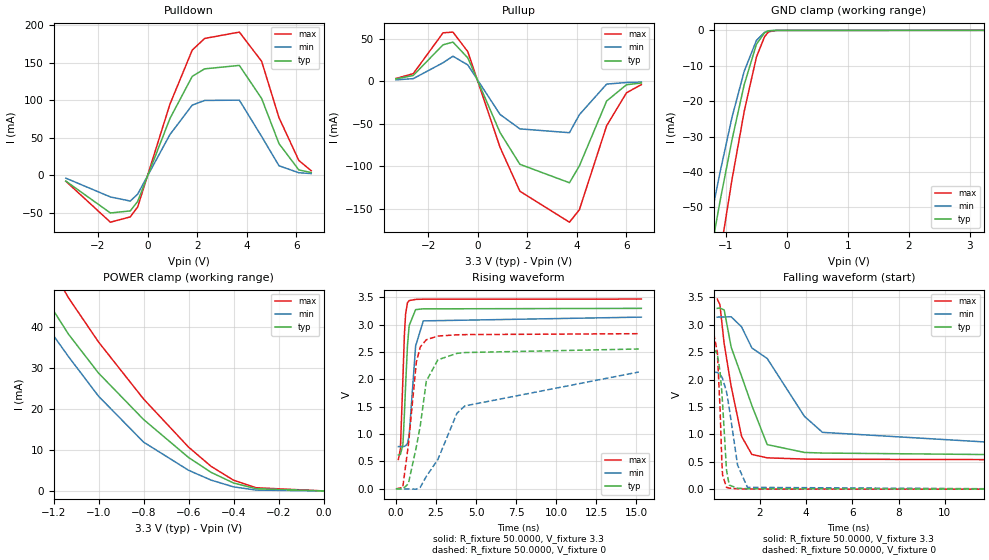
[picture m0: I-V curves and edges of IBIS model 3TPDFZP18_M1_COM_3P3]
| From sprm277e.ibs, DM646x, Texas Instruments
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|   Model Cell 3TPDFZP18_M1_COM_3P3
|BPCI33TPDFZP18_M1_COM_3P3
[Model]   3TPDFZP18_M1_COM_3P3
Model_type   I/O
Polarity   Non-Inverting
Enable   Active-Low
Vinl =  0.99V
Vinh =  1.65V
Cref =  10.0000pF
Rref =  50.0000
Vref =  1.5V
Vmeas =  1.65
C_comp   3.400798p   3.35082p   3.526617p
[Model Spec]
Vinl   0.99V   0.942V   1.041V
Vinh   1.65V   1.570V   1.735V
[Temperature Range]   25   105   0
[Voltage Range]   3.3   3.14   3.47
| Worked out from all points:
|   slope of the pulldown table from 0 to 0.495 V, typ, clamps not added: 11.5 ohm
|   slope of the pullup table from 0 to 0.495 V, typ, clamps not added: 14.2 ohm
|   GND clamp passes 1 mA (typ) near -0.38 V on its own axis
|   POWER clamp passes 1 mA (typ) near -0.33 V on its own axis
|   rising waveform, R_fixture 50.0000, V_fixture 3.3: 20-80 % time 256ps typ, 344ps min, 207ps max; typ from 0.619 V to 3.3 V
|   rising waveform, R_fixture 50.0000, V_fixture 0: 20-80 % time 902ps typ, 4.8ns min, 574ps max; typ from 0 V to 2.56 V
|   falling waveform, R_fixture 50.0000, V_fixture 3.3: 20-80 % time 1.25ns typ, 2.6ns min, 743ps max; typ from 3.3 V to 0.619 V
|   falling waveform, R_fixture 50.0000, V_fixture 0: 20-80 % time 227ps typ, 455ps min, 150ps max; typ from 2.56 V to 0 V
[POWER_clamp]
|   voltage   I(typ)   I(min)   I(max)
-3.3V     266.8mA    206.4mA    325.6mA
-1.333V   56.66mA    48.3mA     68.08mA
-1.3V     53.18mA    45.61mA    63.86mA
-1.233V   46.77mA    40.36mA    56.56mA
-1.133V   38.14mA    32.68mA    47mA
-1V       28.71mA    23.08mA    36.28mA
-800mV    17.41mA    11.9mA     22.41mA
-600mV    8.154mA    5.036mA    10.68mA
-500mV    4.533mA    2.642mA    6.002mA
-400mV    1.938mA    991.9uA    2.613mA
-300mV    534.7uA    203uA      780.2uA
0V        182.2nA    308.7nA    844.7nA
[Pulldown]
|   voltage   I(typ)   I(min)   I(max)
-3.3V     -7.787mA   -3.888mA   -7.985mA
-1.5V     -50.3mA    -28.94mA   -62.59mA
-700mV    -47.57mA   -34.42mA   -55.53mA
-400mV    -34.9mA    -25.14mA   -42.3mA
900mV     75.57mA    54.22mA    94.66mA
1.8V      131.8mA    93.47mA    166.8mA
2.3V      141.8mA    99.67mA    182.3mA
3.7V      146.4mA    100.1mA    190.8mA
4.6V      102.2mA    51.62mA    151.8mA
5.3V      42.11mA    12.62mA    76.69mA
6.1V      7.062mA    3.321mA    19.67mA
6.6V      3.543mA    2.232mA    5.962mA
[Pullup]
|   voltage   I(typ)   I(min)   I(max)
-3.3V     2.84mA     1.735mA    3.327mA
-2.6V     6.94mA     3.146mA    9.053mA
-1.4V     43.04mA    21.89mA    57.16mA
-1V       46.23mA    29.6mA     58.04mA
-400mV    27.63mA    19.3mA     34.95mA
900mV     -60.4mA    -39.07mA   -77.82mA
1.7V      -97.84mA   -56.07mA   -129.6mA
3.7V      -119.6mA   -60.58mA   -166.1mA
4.1V      -99.72mA   -39.32mA   -151.4mA
5.2V      -23.22mA   -3.285mA   -52.37mA
6V        -4.027mA   -1.402mA   -13.57mA
6.6V      -2.032mA   -942.8uA   -3.85mA
[GND_clamp]
|   voltage   I(typ)   I(min)   I(max)
-3.3V     -301.2mA   -235.6mA   -364.4mA
-1.367V   -75.5mA    -63.63mA   -93.98mA
-1.3V     -68.14mA   -57.66mA   -85.98mA
-1.233V   -61.34mA   -51.8mA    -78.41mA
-1.1V     -48.49mA   -40.31mA   -63.55mA
-900mV    -30.85mA   -24.49mA   -42.05mA
-700mV    -15.32mA   -11.54mA   -22.85mA
-500mV    -3.958mA   -2.853mA   -7.561mA
-366.7mV  -691.7uA   -560.5uA   -1.825mA
-300mV    -116.7uA   -125.7uA   -398.3uA
-166.7mV  -12.04uA   -14.05uA   -28.61uA
3.233V    119.2nA    2.959uA    596nA
[Ramp]
| variable   typ   min   max
dV/dt_f  1.6137308/1.2497869n  1.4241658/2.5928366n  1.7647865/0.74327872n
dV/dt_r  1.5402669/0.90489537n  1.2873513/4.8809306n  1.7069914/0.57489658n
R_load = 50
[Rising Waveform]
R_fixture = 50.0000
V_fixture = 3.3
V_fixture_min = 3.14
V_fixture_max = 3.47
|   time   V(typ)   V(min)   V(max)
155.5ps   618.6mV    772.4mV    535.8mV
283.3ps   628.2mV    772.5mV    729mV
439.1ps   811.5mV    772.4mV    2.025V
532.5ps   1.372V     776.7mV    2.823V
606.8ps   1.891V     788.3mV    3.196V
724.2ps   2.626V     831.4mV    3.402V
828.5ps   2.985V     974mV      3.442V
1.233ns   3.277V     2.615V     3.464V
1.711ns   3.291V     3.071V     3.468V
15.31ns   3.3V       3.14V      3.47V
[Rising Waveform]
R_fixture = 50.0000
V_fixture = 0
V_fixture_min = 0
V_fixture_max = 0
|   time   V(typ)   V(min)   V(max)
2.842ps   23.63uV    16.46uV    33.77uV
428.3ps   -3.668mV   -40.57uV   24.95mV
778ps     93.31mV    -2.244mV   799.4mV
1.277ns   768.4mV    -5.9mV     2.314V
1.518ns   1.146V     27.23mV    2.592V
1.898ns   1.969V     226.8mV    2.726V
2.619ns   2.359V     536.9mV    2.794V
3.805ns   2.477V     1.38V      2.816V
4.3ns     2.492V     1.516V     2.82V
15.15ns   2.557V     2.136V     2.837V
[Falling Waveform]
R_fixture = 50.0000
V_fixture = 3.3
V_fixture_min = 3.14
V_fixture_max = 3.47
|   time   V(typ)   V(min)   V(max)
155.5ps   3.3V       3.14V      3.47V
265.5ps   3.307V     3.143V     3.373V
453.9ps   3.27V      3.143V     2.649V
756.3ps   2.59V      3.146V     1.874V
1.206ns   2.061V     2.962V     963.4mV
1.65ns    1.527V     2.578V     634mV
2.314ns   813.3mV    2.385V     571.9mV
3.922ns   670.4mV    1.33V      549.3mV
4.705ns   659.2mV    1.037V     546.3mV
15.31ns   618.6mV    772.4mV    535.8mV
[Falling Waveform]
R_fixture = 50.0000
V_fixture = 0
V_fixture_min = 0
V_fixture_max = 0
|   time   V(typ)   V(min)   V(max)
2.842ps   2.557V     2.136V     2.837V
158.4ps   2.466V     2.129V     2.494V
277.3ps   2.137V     2.091V     1.444V
349ps     1.784V     2.047V     519.2mV
383.3ps   1.567V     2.019V     260.3mV
553.1ps   348.7mV    1.779V     32.28mV
671.7ps   75.16mV    1.479V     19.6mV
1.033ns   16.33mV    437.7mV    7.161mV
1.46ns    8.762mV    33.11mV    2.27mV
15.15ns   23.63uV    16.46uV    33.77uV
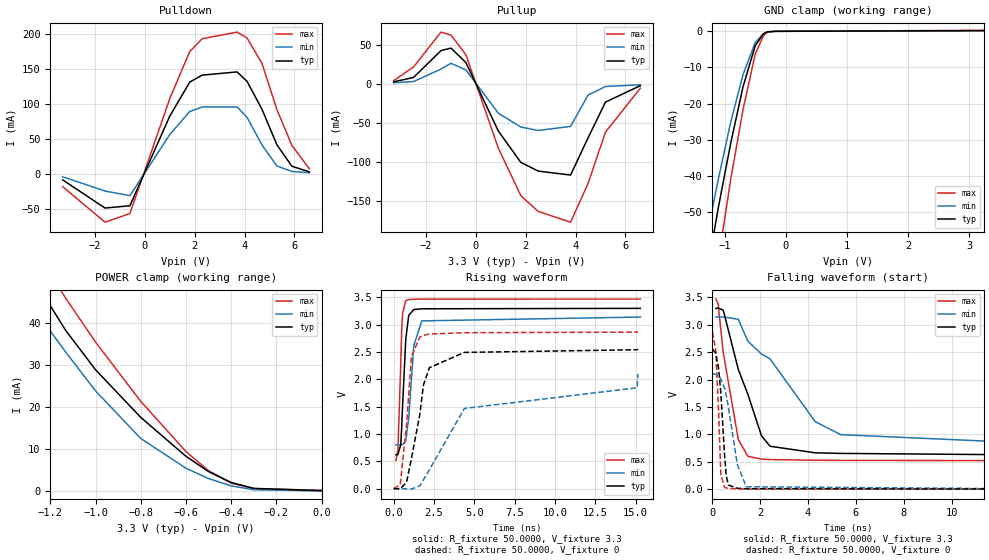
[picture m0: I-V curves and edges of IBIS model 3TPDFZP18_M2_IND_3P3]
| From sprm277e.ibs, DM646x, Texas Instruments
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|   Model Cell 3TPDFZP18_M2_IND_3P3
|BPCI33TPDFZP18_M2_IND_3P3
[Model]   3TPDFZP18_M2_IND_3P3
Model_type   I/O
Polarity   Non-Inverting
Enable   Active-Low
Vinl =  0.99V
Vinh =  1.65V
Cref =  10.0000pF
Rref =  50.0000
Vref =  1.5V
Vmeas =  1.65
C_comp   3.400798p   3.348868p   3.529696p
[Model Spec]
Vinl   0.99V   0.942V   1.041V
Vinh   1.65V   1.570V   1.735V
[Temperature Range]   25   125   -40
[Voltage Range]   3.3   3.14   3.47
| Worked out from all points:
|   slope of the pulldown table from 0 to 0.495 V, typ, clamps not added: 11.5 ohm
|   slope of the pullup table from 0 to 0.495 V, typ, clamps not added: 14.2 ohm
|   GND clamp passes 1 mA (typ) near -0.38 V on its own axis
|   POWER clamp passes 1 mA (typ) near -0.32 V on its own axis
|   rising waveform, R_fixture 50.0000, V_fixture 3.3: 20-80 % time 256ps typ, 355ps min, 184ps max; typ from 0.618 V to 3.3 V
|   rising waveform, R_fixture 50.0000, V_fixture 0: 20-80 % time 906ps typ, 7.05ns min, 457ps max; typ from 0 V to 2.56 V
|   falling waveform, R_fixture 50.0000, V_fixture 3.3: 20-80 % time 1.25ns typ, 2.7ns min, 649ps max; typ from 3.3 V to 0.618 V
|   falling waveform, R_fixture 50.0000, V_fixture 0: 20-80 % time 227ps typ, 465ps min, 141ps max; typ from 2.56 V to 0 V
[POWER_clamp]
|   voltage   I(typ)   I(min)   I(max)
-3.3V     267mA      199.1mA    323mA
-1.333V   56.8mA     48.08mA    64.5mA
-1.3V     53.32mA    45.52mA    60.67mA
-1.233V   46.92mA    40.5mA     54.49mA
-1.133V   38.28mA    33.14mA    45.95mA
-1V       28.86mA    23.84mA    35.43mA
-800mV    17.55mA    12.54mA    21.35mA
-600mV    8.297mA    5.469mA    9.424mA
-500mV    4.676mA    3.022mA    4.875mA
-400mV    2.081mA    1.274mA    1.922mA
-300mV    677.4uA    360.1uA    636.2uA
0V        142.8uA    83.54uA    234.1uA
[Pulldown]
|   voltage   I(typ)   I(min)   I(max)
-3.3V     -7.788mA   -3.439mA   -17.46mA
-1.6V     -48.12mA   -23.82mA   -68.34mA
-600mV    -44.86mA   -30.4mA    -55.99mA
1V        83.15mA    56.86mA    108.2mA
1.8V      131.8mA    89.77mA    175.4mA
2.3V      141.8mA    96.35mA    193.8mA
3.7V      146.4mA    96.42mA    203.3mA
4.1V      132.9mA    81.48mA    194.9mA
4.7V      93.04mA    41.99mA    158.5mA
5.3V      42.13mA    11.99mA    92.47mA
5.9V      11.6mA     4.111mA    41.42mA
6.6V      3.544mA    2.265mA    7.965mA
[Pullup]
|   voltage   I(typ)   I(min)   I(max)
-3.3V     2.84mA     1.649mA    4.345mA
-2.5V     8.541mA    3.25mA     22.02mA
-1.4V     43.04mA    19.26mA    66.82mA
-1V       46.23mA    26.7mA     63mA
-400mV    27.62mA    18.2mA     37.7mA
900mV     -60.4mA    -37.48mA   -82.33mA
1.8V      -100.6mA   -55.19mA   -143.4mA
2.5V      -111.9mA   -59.72mA   -163.8mA
3.8V      -117mA     -54.41mA   -177.6mA
4.5V      -69.24mA   -14.23mA   -127.9mA
5.2V      -23.21mA   -3.139mA   -61.78mA
6.6V      -2.032mA   -953.4uA   -5.249mA
[GND_clamp]
|   voltage   I(typ)   I(min)   I(max)
-3.3V     -301.2mA   -227.6mA   -361.6mA
-1.367V   -75.51mA   -63.1mA    -93.49mA
-1.3V     -68.15mA   -57.39mA   -85.78mA
-1.233V   -61.35mA   -51.76mA   -78.14mA
-1.1V     -48.52mA   -40.68mA   -62.97mA
-900mV    -30.93mA   -25.13mA   -40.97mA
-700mV    -15.41mA   -12.05mA   -21.73mA
-500mV    -4.036mA   -3.167mA   -6.357mA
-366.7mV  -756.9uA   -716.4uA   -1.297mA
-300mV    -173.8uA   -203.1uA   -270.2uA
-166.7mV  -45.01uA   -38.97uA   -63.56uA
3.233V    142.6uA    88.05uA    233.8uA
[Ramp]
| variable   typ   min   max
dV/dt_f  1.6129244/1.2481865n  1.4053732/2.6933403n  1.7735668/0.64963269n
dV/dt_r  1.5392242/0.90714573n   1.265974/5.327761n   1.7227507/0.4595914n
R_load = 50
[Rising Waveform]
R_fixture = 50.0000
V_fixture = 3.3
V_fixture_min = 3.14
V_fixture_max = 3.47
|   time   V(typ)   V(min)   V(max)
146.7ps   617.6mV    801.6mV    518.4mV
263.7ps   623.1mV    801.8mV    702.8mV
438.3ps   802.4mV    801.7mV    2.263V
493.7ps   1.09V      802.7mV    2.861V
558.5ps   1.547V     808.3mV    3.218V
751.2ps   2.732V     875.2mV    3.44V
933ps     3.169V     1.294V     3.457V
1.249ns   3.276V     2.617V     3.464V
1.746ns   3.29V      3.069V     3.467V
15.3ns    3.298V     3.139V     3.468V
[Rising Waveform]
R_fixture = 50.0000
V_fixture = 0
V_fixture_min = 0
V_fixture_max = 0
|   time   V(typ)   V(min)   V(max)
0s        22.69uV    17.19uV    29.57uV
407.5ps   -3.162mV   11.29uV    72.75mV
799.7ps   116.9mV    -2.452mV   1.169V
1.103ns   551.8mV    -9.258mV   2.421V
1.626ns   1.364V     52.3mV     2.773V
1.848ns   1.898V     162.6mV    2.804V
2.214ns   2.212V     345.2mV    2.827V
4.385ns   2.492V     1.467V     2.853V
15.1ns    2.541V     1.845V     2.863V
15.15ns   2.555V     2.1V       2.864V
[Falling Waveform]
R_fixture = 50.0000
V_fixture = 3.3
V_fixture_min = 3.14
V_fixture_max = 3.47
|   time   V(typ)   V(min)   V(max)
146.7ps   3.298V     3.139V     3.468V
241.4ps   3.304V     3.141V     3.378V
455.5ps   3.266V     3.141V     2.492V
1.084ns   2.185V     3.099V     908.1mV
1.484ns   1.73V      2.699V     599.1mV
2.051ns   977.9mV    2.466V     549mV
2.409ns   783.5mV    2.378V     539.7mV
4.299ns   662.9mV    1.231V     527.5mV
5.361ns   652.4mV    994.9mV    525.3mV
15.3ns    617.6mV    801.6mV    518.4mV
[Falling Waveform]
R_fixture = 50.0000
V_fixture = 0
V_fixture_min = 0
V_fixture_max = 0
|   time   V(typ)   V(min)   V(max)
0s        2.555V     2.1V       2.864V
143.3ps   2.482V     2.096V     2.534V
263.7ps   2.191V     2.063V     1.385V
353.8ps   1.756V     2.011V     272.7mV
508.8ps   630.6mV    1.847V     31.87mV
577.3ps   251.7mV    1.72V      22.54mV
668.9ps   76.35mV    1.496V     16.43mV
1.048ns   15.65mV    441.8mV    4.692mV
1.418ns   9.308mV    44.53mV    1.796mV
15.15ns   22.69uV    17.19uV    29.57uV
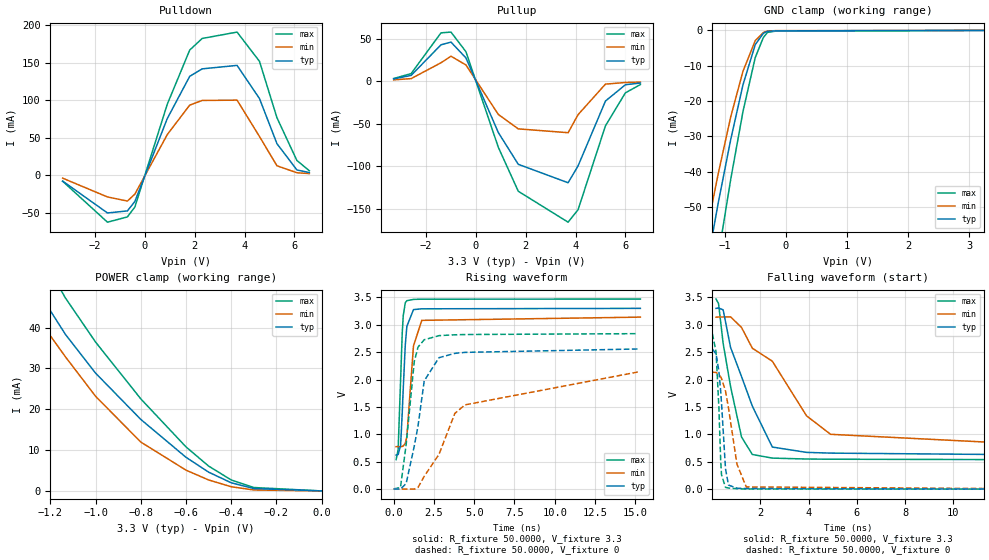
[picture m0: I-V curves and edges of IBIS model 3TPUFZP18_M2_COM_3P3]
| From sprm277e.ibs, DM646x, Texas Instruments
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|   Model Cell 3TPUFZP18_M2_COM_3P3
|BPCI33TPUFZP18_M2_COM_3P3
[Model]   3TPUFZP18_M2_COM_3P3
Model_type   I/O
Polarity   Non-Inverting
Enable   Active-Low
Vinl =  0.99V
Vinh =  1.65V
Cref =  10.0000pF
Rref =  50.0000
Vref =  1.5V
Vmeas =  1.65
C_comp   3.400798p   3.35082p   3.526617p
[Model Spec]
Vinl   0.99V   0.942V   1.041V
Vinh   1.65V   1.570V   1.735V
[Temperature Range]   25   105   0
[Voltage Range]   3.3   3.14   3.47
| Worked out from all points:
|   slope of the pulldown table from 0 to 0.495 V, typ, clamps not added: 11.5 ohm
|   slope of the pullup table from 0 to 0.495 V, typ, clamps not added: 14.2 ohm
|   GND clamp passes 1 mA (typ) near -0.38 V on its own axis
|   POWER clamp passes 1 mA (typ) near -0.33 V on its own axis
|   rising waveform, R_fixture 50.0000, V_fixture 3.3: 20-80 % time 255ps typ, 344ps min, 207ps max; typ from 0.62 V to 3.3 V
|   rising waveform, R_fixture 50.0000, V_fixture 0: 20-80 % time 903ps typ, 4.65ns min, 574ps max; typ from 0.001 V to 2.56 V
|   falling waveform, R_fixture 50.0000, V_fixture 3.3: 20-80 % time 1.25ns typ, 2.6ns min, 744ps max; typ from 3.3 V to 0.62 V
|   falling waveform, R_fixture 50.0000, V_fixture 0: 20-80 % time 226ps typ, 454ps min, 150ps max; typ from 2.56 V to 0.001 V
[POWER_clamp]
|   voltage   I(typ)   I(min)   I(max)
-3.3V     268.4mA    207.5mA    327.8mA
-1.333V   56.98mA    48.55mA    68.49mA
-1.3V     53.47mA    45.85mA    64.24mA
-1.233V   47.03mA    40.57mA    56.88mA
-1.133V   38.34mA    32.85mA    47.26mA
-1V       28.87mA    23.2mA     36.48mA
-800mV    17.53mA    11.98mA    22.56mA
-600mV    8.242mA    5.091mA    10.79mA
-500mV    4.606mA    2.687mA    6.094mA
-400mV    1.995mA    1.028mA    2.686mA
-300mV    577.2uA    229.5uA    834.3uA
0V        181nA      305.2nA    842.9nA
[Pulldown]
|   voltage   I(typ)   I(min)   I(max)
-3.3V     -7.785mA   -3.888mA   -7.982mA
-1.5V     -50.3mA    -28.94mA   -62.59mA
-700mV    -47.57mA   -34.42mA   -55.54mA
-400mV    -34.9mA    -25.14mA   -42.3mA
900mV     75.57mA    54.22mA    94.66mA
1.8V      131.8mA    93.47mA    166.8mA
2.3V      141.8mA    99.67mA    182.3mA
3.7V      146.4mA    100.1mA    190.8mA
4.6V      102.2mA    51.62mA    151.8mA
5.3V      42.12mA    12.62mA    76.69mA
6.1V      7.063mA    3.321mA    19.68mA
6.6V      3.543mA    2.233mA    5.963mA
[Pullup]
|   voltage   I(typ)   I(min)   I(max)
-3.3V     2.841mA    1.735mA    3.327mA
-2.6V     6.941mA    3.146mA    9.055mA
-1.4V     43.04mA    21.88mA    57.16mA
-1V       46.23mA    29.6mA     58.04mA
-400mV    27.62mA    19.3mA     34.95mA
900mV     -60.4mA    -39.07mA   -77.82mA
1.7V      -97.84mA   -56.07mA   -129.6mA
3.7V      -119.6mA   -60.58mA   -166.1mA
4.1V      -99.72mA   -39.32mA   -151.4mA
5.2V      -23.22mA   -3.285mA   -52.37mA
6V        -4.026mA   -1.402mA   -13.57mA
6.6V      -2.032mA   -942.7uA   -3.85mA
[GND_clamp]
|   voltage   I(typ)   I(min)   I(max)
-3.3V     -299.7mA   -234.6mA   -362.3mA
-1.367V   -75.26mA   -63.41mA   -93.68mA
-1.3V     -67.94mA   -57.47mA   -85.74mA
-1.233V   -61.19mA   -51.63mA   -78.23mA
-1.1V     -48.42mA   -40.2mA    -63.49mA
-900mV    -30.88mA   -24.46mA   -42.12mA
-700mV    -15.4mA    -11.56mA   -22.96mA
-500mV    -4.068mA   -2.905mA   -7.714mA
-366.7mV  -816.7uA   -622.7uA   -1.997mA
-300mV    -247.4uA   -192.2uA   -578.9uA
-166.7mV  -146uA     -83.39uA   -214.3uA
3.233V    -8.681uA   10.9uA     -38.06uA
[Ramp]
| variable   typ   min   max
dV/dt_f  1.6128795/1.2525253n   1.423504/2.5970645n  1.7638263/0.7450254n
dV/dt_r  1.5391339/0.9057428n  1.2867661/4.8469061n   1.705839/0.57507527n
R_load = 50
[Rising Waveform]
R_fixture = 50.0000
V_fixture = 3.3
V_fixture_min = 3.14
V_fixture_max = 3.47
|   time   V(typ)   V(min)   V(max)
155.3ps   619.9mV    773.3mV    537.3mV
281.1ps   629.1mV    773.5mV    720.3mV
435ps     798.6mV    773.4mV    2.002V
533.7ps   1.382V     777.8mV    2.839V
597.4ps   1.832V     787.3mV    3.165V
724.7ps   2.632V     832.3mV    3.403V
822.5ps   2.972V     959mV      3.441V
1.232ns   3.277V     2.612V     3.464V
1.747ns   3.292V     3.081V     3.468V
15.31ns   3.3V       3.14V      3.47V
[Rising Waveform]
R_fixture = 50.0000
V_fixture = 0
V_fixture_min = 0
V_fixture_max = 0
|   time   V(typ)   V(min)   V(max)
2.779ps   1.241mV    839.4uV    1.431mV
425.8ps   -2.184mV   794.9uV    27.76mV
778.6ps   100.1mV    -1.34mV    812.6mV
1.281ns   781.8mV    -3.04mV    2.327V
1.517ns   1.155V     30.48mV    2.594V
1.899ns   1.976V     232.3mV    2.727V
2.816ns   2.399V     632.9mV    2.802V
3.799ns   2.478V     1.381V     2.817V
4.427ns   2.496V     1.537V     2.822V
15.15ns   2.558V     2.137V     2.838V
[Falling Waveform]
R_fixture = 50.0000
V_fixture = 3.3
V_fixture_min = 3.14
V_fixture_max = 3.47
|   time   V(typ)   V(min)   V(max)
155.3ps   3.3V       3.14V      3.47V
259.3ps   3.307V     3.143V     3.388V
450.4ps   3.273V     3.143V     2.661V
758.6ps   2.587V     3.146V     1.873V
1.214ns   2.055V     2.951V     952mV
1.661ns   1.517V     2.573V     633.7mV
2.491ns   769.2mV    2.336V     567.7mV
3.911ns   672.2mV    1.339V     551mV
4.907ns   658.7mV    1.002V     547.3mV
15.31ns   619.9mV    773.3mV    537.3mV
[Falling Waveform]
R_fixture = 50.0000
V_fixture = 0
V_fixture_min = 0
V_fixture_max = 0
|   time   V(typ)   V(min)   V(max)
2.779ps   2.558V     2.137V     2.838V
156.1ps   2.47V      2.13V      2.507V
273.9ps   2.153V     2.094V     1.488V
347ps     1.799V     2.05V      540.7mV
382.5ps   1.576V     2.021V     262.8mV
547.8ps   373.3mV    1.793V     34.44mV
670.6ps   76.08mV    1.485V     21.57mV
1.022ns   18.47mV    459.9mV    9.487mV
1.408ns   11.43mV    41.77mV    4.145mV
15.15ns   1.241mV    839.4uV    1.431mV
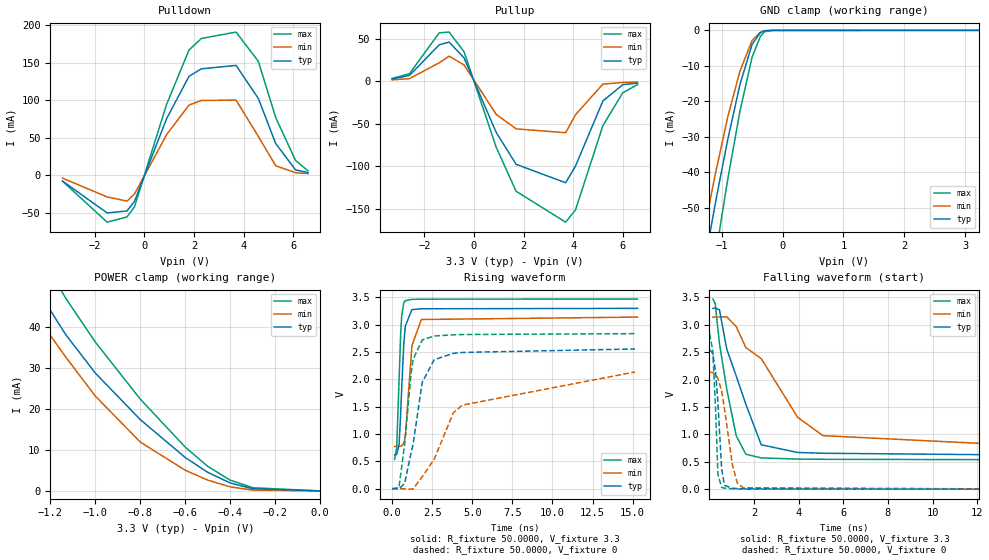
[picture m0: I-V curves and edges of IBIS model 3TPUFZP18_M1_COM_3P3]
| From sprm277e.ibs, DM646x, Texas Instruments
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|   Model Cell 3TPUFZP18_M1_COM_3P3
|BPCI33TPUFZP18_M1_COM_3P3
[Model]   3TPUFZP18_M1_COM_3P3
Model_type   I/O
Polarity   Non-Inverting
Enable   Active-Low
Vinl =  0.99V
Vinh =  1.65V
Cref =  10.0000pF
Rref =  50.0000
Vref =  1.5V
Vmeas =  1.65
C_comp   3.400798p   3.35082p   3.526617p
[Model Spec]
Vinl   0.99V   0.942V   1.041V
Vinh   1.65V   1.570V   1.735V
[Temperature Range]   25   105   0
[Voltage Range]   3.3   3.14   3.47
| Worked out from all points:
|   slope of the pulldown table from 0 to 0.495 V, typ, clamps not added: 11.5 ohm
|   slope of the pullup table from 0 to 0.495 V, typ, clamps not added: 14.2 ohm
|   GND clamp passes 1 mA (typ) near -0.38 V on its own axis
|   POWER clamp passes 1 mA (typ) near -0.33 V on its own axis
|   rising waveform, R_fixture 50.0000, V_fixture 3.3: 20-80 % time 256ps typ, 345ps min, 208ps max; typ from 0.619 V to 3.3 V
|   rising waveform, R_fixture 50.0000, V_fixture 0: 20-80 % time 902ps typ, 4.8ns min, 574ps max; typ from 0 V to 2.56 V
|   falling waveform, R_fixture 50.0000, V_fixture 3.3: 20-80 % time 1.25ns typ, 2.6ns min, 742ps max; typ from 3.3 V to 0.619 V
|   falling waveform, R_fixture 50.0000, V_fixture 0: 20-80 % time 226ps typ, 453ps min, 149ps max; typ from 2.56 V to 0 V
[POWER_clamp]
|   voltage   I(typ)   I(min)   I(max)
-3.3V     268.4mA    207.5mA    327.8mA
-1.333V   56.96mA    48.54mA    68.47mA
-1.3V     53.46mA    45.84mA    64.22mA
-1.233V   47.02mA    40.56mA    56.86mA
-1.133V   38.32mA    32.84mA    47.22mA
-1V       28.81mA    23.18mA    36.39mA
-800mV    17.43mA    11.94mA    22.43mA
-600mV    8.164mA    5.043mA    10.7mA
-500mV    4.539mA    2.645mA    6.009mA
-400mV    1.94mA     992.9uA    2.616mA
-300mV    535.1uA    203.2uA    780.9uA
0V        181.5nA    305.4nA    844.2nA
[Pulldown]
|   voltage   I(typ)   I(min)   I(max)
-3.3V     -7.785mA   -3.888mA   -7.982mA
-1.5V     -50.3mA    -28.94mA   -62.59mA
-700mV    -47.57mA   -34.42mA   -55.54mA
-400mV    -34.9mA    -25.14mA   -42.3mA
900mV     75.57mA    54.22mA    94.66mA
1.8V      131.8mA    93.47mA    166.8mA
2.3V      141.8mA    99.67mA    182.3mA
3.7V      146.4mA    100.1mA    190.8mA
4.6V      102.2mA    51.62mA    151.8mA
5.3V      42.12mA    12.62mA    76.69mA
6.1V      7.063mA    3.321mA    19.68mA
6.6V      3.543mA    2.233mA    5.963mA
[Pullup]
|   voltage   I(typ)   I(min)   I(max)
-3.3V     2.841mA    1.735mA    3.327mA
-2.6V     6.941mA    3.146mA    9.055mA
-1.4V     43.04mA    21.88mA    57.15mA
-1V       46.23mA    29.6mA     58.04mA
-400mV    27.63mA    19.3mA     34.95mA
900mV     -60.4mA    -39.07mA   -77.82mA
1.7V      -97.84mA   -56.07mA   -129.6mA
3.7V      -119.6mA   -60.58mA   -166.1mA
4.1V      -99.72mA   -39.32mA   -151.4mA
5.2V      -23.22mA   -3.285mA   -52.37mA
6V        -4.026mA   -1.402mA   -13.56mA
6.6V      -2.032mA   -942.7uA   -3.85mA
[GND_clamp]
|   voltage   I(typ)   I(min)   I(max)
-3.3V     -299.6mA   -234.5mA   -362.2mA
-1.367V   -75.14mA   -63.34mA   -93.5mA
-1.3V     -67.82mA   -57.41mA   -85.56mA
-1.233V   -61.06mA   -51.57mA   -78.06mA
-1.1V     -48.3mA    -40.13mA   -63.31mA
-900mV    -30.76mA   -24.39mA   -41.94mA
-700mV    -15.27mA   -11.5mA    -22.78mA
-500mV    -3.933mA   -2.834mA   -7.527mA
-366.7mV  -681.6uA   -552.6uA   -1.81mA
-300mV    -112.4uA   -122.1uA   -391.1uA
-166.7mV  -11.12uA   -13.5uA    -26.64uA
3.233V    118.1nA    2.958uA    593.5nA
[Ramp]
| variable   typ   min   max
dV/dt_f  1.6137143/1.2501583n  1.4240797/2.5934046n  1.7647717/0.74285157n
dV/dt_r  1.5402761/0.90553349n  1.2873177/4.8706273n  1.7069859/0.57542649n
R_load = 50
[Rising Waveform]
R_fixture = 50.0000
V_fixture = 3.3
V_fixture_min = 3.14
V_fixture_max = 3.47
|   time   V(typ)   V(min)   V(max)
155.4ps   618.6mV    772.4mV    535.8mV
285.1ps   628.6mV    772.5mV    738.8mV
438ps     807.1mV    772.4mV    2.019V
532.6ps   1.371V     776.7mV    2.824V
599ps     1.839V     786.6mV    3.166V
727.7ps   2.641V     833.2mV    3.404V
825.6ps   2.976V     964.8mV    3.441V
1.235ns   3.277V     2.616V     3.464V
1.823ns   3.292V     3.096V     3.468V
15.31ns   3.3V       3.14V      3.47V
[Rising Waveform]
R_fixture = 50.0000
V_fixture = 0
V_fixture_min = 0
V_fixture_max = 0
|   time   V(typ)   V(min)   V(max)
2.736ps   19.18uV    15.34uV    24.98uV
426.5ps   -3.61mV    -31.37uV   23.65mV
778.6ps   95.08mV    -2.236mV   805.1mV
1.182ns   655mV      -8.638mV   2.097V
1.305ns   807.3mV    -4.912mV   2.364V
1.878ns   1.947V     216.9mV    2.722V
2.62ns    2.359V     538mV      2.794V
3.819ns   2.478V     1.389V     2.816V
4.378ns   2.493V     1.529V     2.821V
15.15ns   2.557V     2.136V     2.837V
[Falling Waveform]
R_fixture = 50.0000
V_fixture = 3.3
V_fixture_min = 3.14
V_fixture_max = 3.47
|   time   V(typ)   V(min)   V(max)
155.4ps   3.3V       3.14V      3.47V
259.3ps   3.307V     3.143V     3.388V
450.4ps   3.273V     3.143V     2.659V
777.6ps   2.556V     3.146V     1.824V
1.2ns     2.066V     2.969V     974.9mV
1.632ns   1.551V     2.585V     637.7mV
2.323ns   810mV      2.382V     571.5mV
3.955ns   669.7mV    1.312V     549.1mV
5.089ns   655.6mV    976.6mV    545.2mV
15.31ns   618.6mV    772.4mV    535.8mV
[Falling Waveform]
R_fixture = 50.0000
V_fixture = 0
V_fixture_min = 0
V_fixture_max = 0
|   time   V(typ)   V(min)   V(max)
2.736ps   2.557V     2.136V     2.837V
148.7ps   2.477V     2.13V      2.542V
273.9ps   2.151V     2.092V     1.484V
380.4ps   1.586V     2.022V     269.2mV
547.1ps   372.8mV    1.792V     32.1mV
674.6ps   70.32mV    1.471V     18.95mV
1.031ns   16.14mV    439.8mV    7.175mV
1.25ns    11.75mV    109.9mV    3.609mV
1.513ns   7.933mV    26.7mV     2.034mV
15.15ns   19.18uV    15.34uV    24.98uV
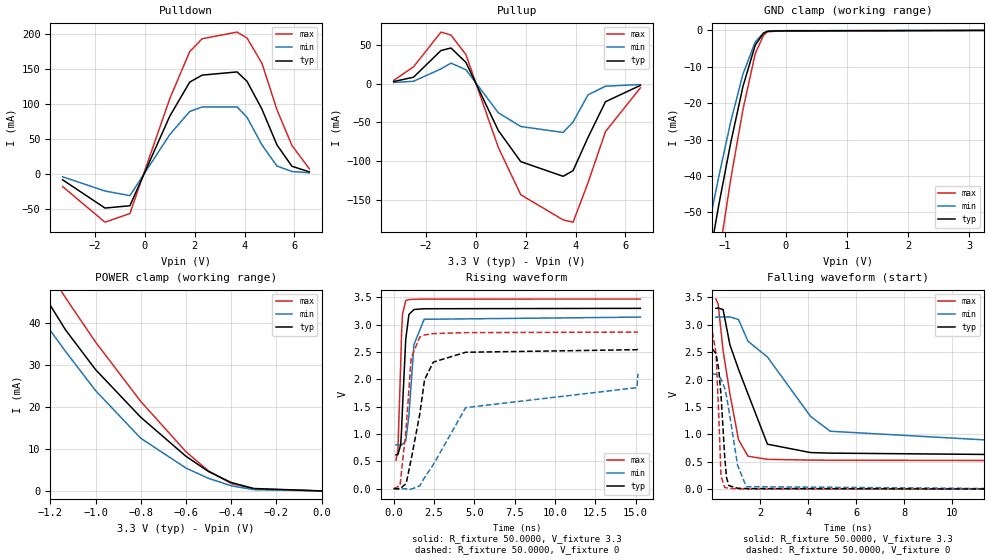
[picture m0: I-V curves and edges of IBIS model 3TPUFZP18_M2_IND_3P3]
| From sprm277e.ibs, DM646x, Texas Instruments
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|   Model Cell 3TPUFZP18_M2_IND_3P3
|BPCI33TPUFZP18_M2_IND_3P3
[Model]   3TPUFZP18_M2_IND_3P3
Model_type   I/O
Polarity   Non-Inverting
Enable   Active-Low
Vinl =  0.99V
Vinh =  1.65V
Cref =  10.0000pF
Rref =  50.0000
Vref =  1.5V
Vmeas =  1.65
C_comp   3.400798p   3.348868p   3.529696p
[Model Spec]
Vinl   0.99V   0.942V   1.041V
Vinh   1.65V   1.570V   1.735V
[Temperature Range]   25   125   -40
[Voltage Range]   3.3   3.14   3.47
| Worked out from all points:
|   slope of the pulldown table from 0 to 0.495 V, typ, clamps not added: 11.5 ohm
|   slope of the pullup table from 0 to 0.495 V, typ, clamps not added: 14.2 ohm
|   GND clamp passes 1 mA (typ) near -0.38 V on its own axis
|   POWER clamp passes 1 mA (typ) near -0.33 V on its own axis
|   rising waveform, R_fixture 50.0000, V_fixture 3.3: 20-80 % time 255ps typ, 354ps min, 183ps max; typ from 0.62 V to 3.3 V
|   rising waveform, R_fixture 50.0000, V_fixture 0: 20-80 % time 907ps typ, 6.83ns min, 457ps max; typ from 0.001 V to 2.56 V
|   falling waveform, R_fixture 50.0000, V_fixture 3.3: 20-80 % time 1.25ns typ, 2.71ns min, 652ps max; typ from 3.3 V to 0.62 V
|   falling waveform, R_fixture 50.0000, V_fixture 0: 20-80 % time 227ps typ, 464ps min, 141ps max; typ from 2.56 V to 0.001 V
[POWER_clamp]
|   voltage   I(typ)   I(min)   I(max)
-3.3V     268.4mA    200mA      324.8mA
-1.333V   56.98mA    48.24mA    64.65mA
-1.3V     53.47mA    45.67mA    60.79mA
-1.233V   47.03mA    40.62mA    54.57mA
-1.133V   38.34mA    33.22mA    45.98mA
-1V       28.87mA    23.88mA    35.43mA
-800mV    17.53mA    12.53mA    21.29mA
-600mV    8.242mA    5.439mA    9.321mA
-500mV    4.606mA    2.982mA    4.749mA
-400mV    1.995mA    1.225mA    1.773mA
-300mV    577.2uA    302.3uA    465.3uA
0V        181nA      550.2nA    315.7nA
[Pulldown]
|   voltage   I(typ)   I(min)   I(max)
-3.3V     -7.786mA   -3.439mA   -17.46mA
-1.6V     -48.12mA   -23.82mA   -68.35mA
-600mV    -44.86mA   -30.4mA    -55.99mA
1V        83.16mA    56.86mA    108.2mA
1.8V      131.8mA    89.77mA    175.4mA
2.3V      141.8mA    96.35mA    193.8mA
3.7V      146.4mA    96.42mA    203.3mA
4.1V      132.9mA    81.48mA    194.9mA
4.7V      93.03mA    41.99mA    158.5mA
5.3V      42.13mA    11.99mA    92.47mA
5.9V      11.6mA     4.111mA    41.43mA
6.6V      3.544mA    2.265mA    7.968mA
[Pullup]
|   voltage   I(typ)   I(min)   I(max)
-3.3V     2.841mA    1.649mA    4.345mA
-2.5V     8.543mA    3.25mA     22.02mA
-1.4V     43.04mA    19.26mA    66.81mA
-1V       46.23mA    26.7mA     63mA
-400mV    27.62mA    18.2mA     37.7mA
900mV     -60.4mA    -37.48mA   -82.33mA
1.8V      -100.6mA   -55.19mA   -143.4mA
3.5V      -119.6mA   -62.93mA   -175.9mA
3.9V      -112.3mA   -49.35mA   -178.9mA
4.5V      -69.25mA   -14.23mA   -127.9mA
5.2V      -23.21mA   -3.139mA   -61.78mA
6.6V      -2.032mA   -953.4uA   -5.247mA
[GND_clamp]
|   voltage   I(typ)   I(min)   I(max)
-3.3V     -299.7mA   -226.5mA   -359.7mA
-1.367V   -75.26mA   -62.88mA   -93.24mA
-1.3V     -67.94mA   -57.2mA    -85.58mA
-1.233V   -61.19mA   -51.59mA   -77.98mA
-1.1V     -48.42mA   -40.56mA   -62.87mA
-900mV    -30.88mA   -25.08mA   -40.92mA
-700mV    -15.4mA    -12.03mA   -21.74mA
-500mV    -4.068mA   -3.172mA   -6.424mA
-366.7mV  -816.7uA   -738uA     -1.406mA
-300mV    -247.4uA   -233.1uA   -399.6uA
-166.7mV  -146uA     -85.57uA   -233.4uA
3.233V    -8.684uA   12.59uA    -45.02uA
[Ramp]
| variable   typ   min   max
dV/dt_f  1.6129018/1.2523805n  1.4052821/2.6991075n  1.7733838/0.65326516n
dV/dt_r  1.5391294/0.90558043n  1.2664774/5.2564012n  1.7228596/0.45846871n
R_load = 50
[Rising Waveform]
R_fixture = 50.0000
V_fixture = 3.3
V_fixture_min = 3.14
V_fixture_max = 3.47
|   time   V(typ)   V(min)   V(max)
146.3ps   619.9mV    803.5mV    521.2mV
263.5ps   625.4mV    803.7mV    705.9mV
439.3ps   809mV      803.6mV    2.293V
488.3ps   1.059V     804.3mV    2.833V
549.2ps   1.485V     809mV      3.192V
750.2ps   2.735V     875.9mV    3.443V
945.2ps   3.187V     1.339V     3.46V
1.258ns   3.279V     2.637V     3.466V
1.89ns    3.293V     3.1V       3.469V
15.3ns    3.3V       3.14V      3.47V
[Rising Waveform]
R_fixture = 50.0000
V_fixture = 0
V_fixture_min = 0
V_fixture_max = 0
|   time   V(typ)   V(min)   V(max)
46.28fs   1.241mV    836.5uV    1.632mV
393.1ps   -1.558mV   837.5uV    54.39mV
778ps     97.92mV    -1.263mV   1.116V
1.085ns   537.3mV    -7.275mV   2.393V
1.621ns   1.368V     53.51mV    2.776V
1.918ns   1.996V     206.3mV    2.814V
2.458ns   2.317V     441.3mV    2.838V
4.466ns   2.497V     1.484V     2.856V
15.09ns   2.544V     1.85V      2.866V
15.15ns   2.558V     2.103V     2.868V
[Falling Waveform]
R_fixture = 50.0000
V_fixture = 3.3
V_fixture_min = 3.14
V_fixture_max = 3.47
|   time   V(typ)   V(min)   V(max)
146.3ps   3.3V       3.14V      3.47V
240.3ps   3.306V     3.142V     3.384V
447.1ps   3.279V     3.143V     2.53V
729.7ps   2.639V     3.145V     1.745V
1.091ns   2.188V     3.096V     903.9mV
1.485ns   1.74V      2.701V     602.8mV
2.298ns   821.8mV    2.412V     544.9mV
4.095ns   668.8mV    1.33V      531mV
4.914ns   658.7mV    1.058V     529mV
15.3ns    619.9mV    803.5mV    521.2mV
[Falling Waveform]
R_fixture = 50.0000
V_fixture = 0
V_fixture_min = 0
V_fixture_max = 0
|   time   V(typ)   V(min)   V(max)
46.28fs   2.558V     2.103V     2.868V
152.7ps   2.475V     2.097V     2.488V
265.3ps   2.19V      2.065V     1.373V
360.3ps   1.724V     2.01V      242.3mV
512.1ps   613.3mV    1.846V     34.17mV
587.9ps   219.9mV    1.702V     24.42mV
684.7ps   66.74mV    1.46V      18.42mV
1.053ns   17.64mV    434.7mV    6.701mV
1.415ns   11.35mV    46.45mV    3.607mV
15.15ns   1.241mV    836.5uV    1.632mV
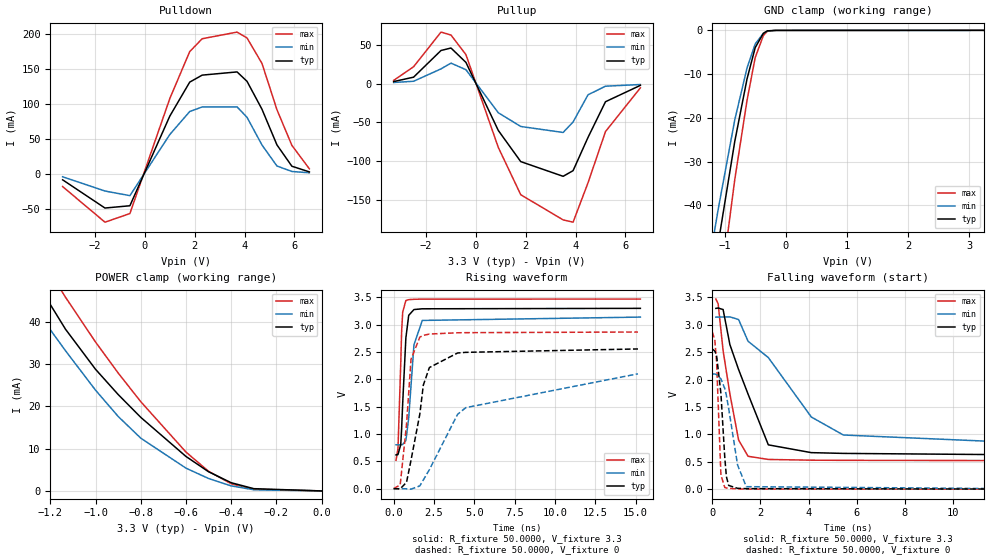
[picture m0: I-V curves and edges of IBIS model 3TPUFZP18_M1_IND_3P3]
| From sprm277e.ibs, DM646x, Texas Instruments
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|   Model Cell 3TPUFZP18_M1_IND_3P3
|BPCI33TPUFZP18_M1_IND_3P3
[Model]   3TPUFZP18_M1_IND_3P3
Model_type   I/O
Polarity   Non-Inverting
Enable   Active-Low
Vinl =  0.99V
Vinh =  1.65V
Cref =  10.0000pF
Rref =  50.0000
Vref =  1.5V
Vmeas =  1.65
C_comp   3.400798p   3.348868p   3.529696p
[Model Spec]
Vinl   0.99V   0.942V   1.041V
Vinh   1.65V   1.570V   1.735V
[Temperature Range]   25   125   -40
[Voltage Range]   3.3   3.14   3.47
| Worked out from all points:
|   slope of the pulldown table from 0 to 0.495 V, typ, clamps not added: 11.5 ohm
|   slope of the pullup table from 0 to 0.495 V, typ, clamps not added: 14.2 ohm
|   GND clamp passes 1 mA (typ) near -0.38 V on its own axis
|   POWER clamp passes 1 mA (typ) near -0.33 V on its own axis
|   rising waveform, R_fixture 50.0000, V_fixture 3.3: 20-80 % time 256ps typ, 355ps min, 184ps max; typ from 0.619 V to 3.3 V
|   rising waveform, R_fixture 50.0000, V_fixture 0: 20-80 % time 904ps typ, 4.92ns min, 457ps max; typ from 0 V to 2.56 V
|   falling waveform, R_fixture 50.0000, V_fixture 3.3: 20-80 % time 1.25ns typ, 2.7ns min, 650ps max; typ from 3.3 V to 0.619 V
|   falling waveform, R_fixture 50.0000, V_fixture 0: 20-80 % time 227ps typ, 464ps min, 141ps max; typ from 2.56 V to 0 V
[POWER_clamp]
|   voltage   I(typ)   I(min)   I(max)
-3.3V     268.4mA    200mA      324.8mA
-1.3V     53.46mA    45.66mA    60.76mA
-1.233V   47.02mA    40.62mA    54.52mA
-1.133V   38.32mA    33.22mA    45.89mA
-1V       28.81mA    23.87mA    35.27mA
-900mV    22.84mA    17.65mA    27.94mA
-800mV    17.43mA    12.5mA     21.14mA
-600mV    8.164mA    5.394mA    9.201mA
-500mV    4.539mA    2.943mA    4.647mA
-400mV    1.94mA     1.192mA    1.69mA
-300mV    535.1uA    277.3uA    402.3uA
0V        181.5nA    550.6nA    315.9nA
[Pulldown]
|   voltage   I(typ)   I(min)   I(max)
-3.3V     -7.786mA   -3.439mA   -17.46mA
-1.6V     -48.12mA   -23.82mA   -68.35mA
-600mV    -44.86mA   -30.4mA    -55.99mA
1V        83.15mA    56.86mA    108.2mA
1.8V      131.8mA    89.77mA    175.4mA
2.3V      141.8mA    96.35mA    193.8mA
3.7V      146.4mA    96.42mA    203.3mA
4.1V      132.9mA    81.48mA    194.9mA
4.7V      93.03mA    41.99mA    158.5mA
5.3V      42.13mA    11.99mA    92.47mA
5.9V      11.6mA     4.111mA    41.43mA
6.6V      3.544mA    2.265mA    7.968mA
[Pullup]
|   voltage   I(typ)   I(min)   I(max)
-3.3V     2.841mA    1.649mA    4.345mA
-2.5V     8.543mA    3.25mA     22.02mA
-1.4V     43.04mA    19.26mA    66.81mA
-1V       46.23mA    26.7mA     62.99mA
-400mV    27.63mA    18.2mA     37.7mA
900mV     -60.4mA    -37.48mA   -82.33mA
1.8V      -100.6mA   -55.19mA   -143.4mA
3.5V      -119.6mA   -62.93mA   -175.9mA
3.9V      -112.3mA   -49.35mA   -178.9mA
4.5V      -69.25mA   -14.23mA   -127.9mA
5.2V      -23.21mA   -3.139mA   -61.78mA
6.6V      -2.032mA   -953.4uA   -5.247mA
[GND_clamp]
|   voltage   I(typ)   I(min)   I(max)
-3.3V     -299.6mA   -226.5mA   -359.4mA
-1.367V   -75.14mA   -62.82mA   -93.04mA
-1.3V     -67.82mA   -57.13mA   -85.38mA
-1.233V   -61.06mA   -51.53mA   -77.77mA
-1.1V     -48.3mA    -40.5mA    -62.66mA
-833.3mV  -25.32mA   -20.4mA    -34.02mA
-633.3mV  -11.07mA   -8.563mA   -15.96mA
-500mV    -3.933mA   -3.105mA   -6.204mA
-366.7mV  -681.6uA   -670.9uA   -1.185mA
-300mV    -112.4uA   -166.1uA   -178.5uA
-166.7mV  -11.12uA   -18.67uA   -12.61uA
3.233V    118.1nA    5.034uA    260.1nA
[Ramp]
| variable   typ   min   max
dV/dt_f  1.6137366/1.2497505n  1.4058558/2.6955782n  1.7744587/0.65105787n
dV/dt_r  1.5402688/0.90560045n  1.2669752/5.2801896n  1.7240185/0.45882625n
R_load = 50
[Rising Waveform]
R_fixture = 50.0000
V_fixture = 3.3
V_fixture_min = 3.14
V_fixture_max = 3.47
|   time   V(typ)   V(min)   V(max)
146.5ps   618.5mV    802.6mV    519.5mV
268.9ps   625mV      802.7mV    735.9mV
439.3ps   806.6mV    802.6mV    2.283V
495.2ps   1.101V     803.7mV    2.88V
561.3ps   1.569V     809.6mV    3.232V
757.6ps   2.758V     881.1mV    3.444V
933.5ps   3.172V     1.294V     3.459V
1.259ns   3.278V     2.635V     3.466V
1.778ns   3.292V     3.079V     3.469V
15.3ns    3.3V       3.14V      3.47V
[Rising Waveform]
R_fixture = 50.0000
V_fixture = 0
V_fixture_min = 0
V_fixture_max = 0
|   time   V(typ)   V(min)   V(max)
0s        19.18uV    16.53uV    22.88uV
406.2ps   -3.136mV   11.73uV    71.57mV
799.1ps   117.4mV    -2.428mV   1.177V
1.077ns   521.3mV    -9mV       2.367V
1.623ns   1.365V     51.43mV    2.774V
1.841ns   1.896V     160.3mV    2.805V
2.216ns   2.217V     347.8mV    2.83V
3.964ns   2.483V     1.361V     2.853V
4.473ns   2.495V     1.483V     2.855V
15.15ns   2.557V     2.102V     2.867V
[Falling Waveform]
R_fixture = 50.0000
V_fixture = 3.3
V_fixture_min = 3.14
V_fixture_max = 3.47
|   time   V(typ)   V(min)   V(max)
146.5ps   3.3V       3.14V      3.47V
240.3ps   3.306V     3.142V     3.384V
447.1ps   3.279V     3.143V     2.527V
729.7ps   2.638V     3.145V     1.737V
1.091ns   2.184V     3.096V     898.2mV
1.485ns   1.735V     2.7V       600.6mV
2.328ns   808.9mV    2.402V     542.4mV
4.116ns   666.8mV    1.317V     529.1mV
5.448ns   652.9mV    988.6mV    526.3mV
15.3ns    618.5mV    802.6mV    519.5mV
[Falling Waveform]
R_fixture = 50.0000
V_fixture = 0
V_fixture_min = 0
V_fixture_max = 0
|   time   V(typ)   V(min)   V(max)
0s        2.557V     2.102V     2.867V
100.6ps   2.522V     2.102V     2.726V
174.3ps   2.444V     2.092V     2.343V
356.2ps   1.746V     2.011V     259.3mV
516.2ps   578.6mV    1.838V     30.62mV
583.5ps   229.9mV    1.71V      22.12mV
679.1ps   67.96mV    1.472V     16.04mV
1.048ns   15.72mV    442.6mV    4.715mV
1.411ns   9.452mV    45.81mV    1.82mV
15.15ns   19.18uV    16.53uV    22.88uV
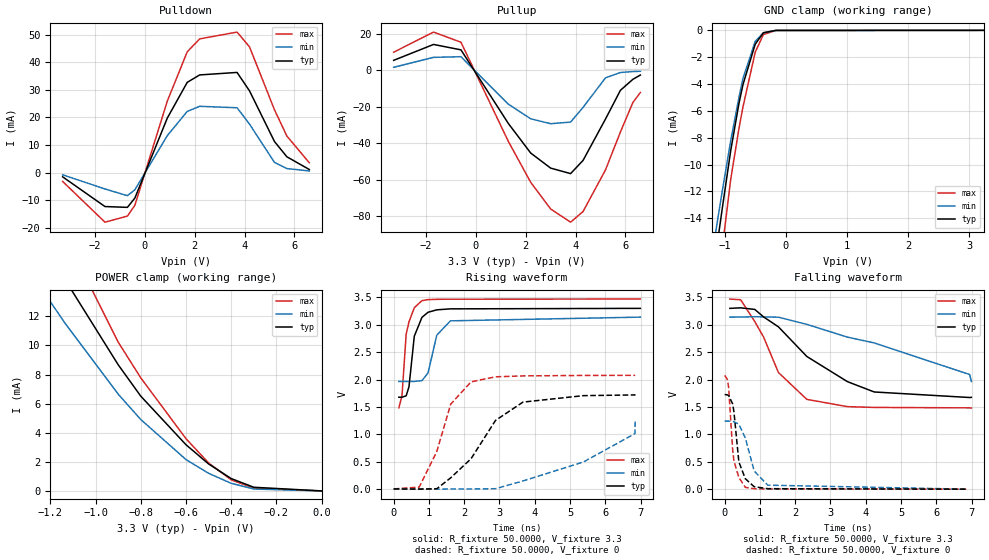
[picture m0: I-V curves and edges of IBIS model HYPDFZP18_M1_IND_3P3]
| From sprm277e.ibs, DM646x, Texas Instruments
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|   Model Cell HYPDFZP18_M1_IND_3P3
[Model]   HYPDFZP18_M1_IND_3P3
Model_type   I/O
Polarity   Non-Inverting
Enable   Active-Low
Vinl =  0.8V
Vinh =  2V
Cref =  10.0000pF
Rref =  50.0000
Vref =  1.5V
Vmeas =  1.65
C_comp   1.737544p   1.689782p   1.779236p
[Model Spec]
Vinl   0.8V   0.8V   0.8V
Vinh   2V   2V   2V
[Temperature Range]   25   125   -40
[Voltage Range]   3.3   3.14   3.47
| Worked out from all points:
|   slope of the pulldown table from 0 to 0.495 V, typ, clamps not added: 44 ohm
|   slope of the pullup table from 0 to 0.495 V, typ, clamps not added: 42.8 ohm
|   GND clamp passes 1 mA (typ) near -0.50 V on its own axis
|   POWER clamp passes 1 mA (typ) near -0.41 V on its own axis
|   rising waveform, R_fixture 50.0000, V_fixture 3.3: 20-80 % time 225ps typ, 313ps min, 182ps max; typ from 1.68 V to 3.3 V
|   rising waveform, R_fixture 50.0000, V_fixture 0: 20-80 % time 1.22ns typ, 2.53ns min, 684ps max; typ from 0 V to 1.73 V
|   falling waveform, R_fixture 50.0000, V_fixture 3.3: 20-80 % time 1.87ns typ, 3.45ns min, 1ns max; typ from 3.3 V to 1.68 V
|   falling waveform, R_fixture 50.0000, V_fixture 0: 20-80 % time 203ps typ, 362ps min, 166ps max; typ from 1.73 V to 0 V
[POWER_clamp]
|   voltage   I(typ)   I(min)   I(max)
-3.3V     84.55mA    63.88mA    102.1mA
-1.4V     21.83mA    17.72mA    26.39mA
-1.367V   20.87mA    16.93mA    25.26mA
-1.233V   17.13mA    13.77mA    20.77mA
-1.133V   14.48mA    11.49mA    17.46mA
-900mV    8.681mA    6.66mA     10.24mA
-800mV    6.518mA    4.912mA    7.777mA
-600mV    3.177mA    2.157mA    3.594mA
-500mV    1.856mA    1.212mA    1.925mA
-400mV    849.7uA    522.4uA    759.8uA
-300mV    252uA      131.5uA    193.9uA
0V        112nA      205.5nA    236nA
[Pulldown]
|   voltage   I(typ)   I(min)   I(max)
-3.3V     -1.512mA   -788.5uA   -3.181mA
-1.6V     -12.28mA   -5.92mA    -17.95mA
-700mV    -12.58mA   -8.352mA   -15.75mA
-400mV    -9.19mA    -6.204mA   -11.82mA
900mV     19.74mA    13.39mA    25.89mA
1.7V      32.7mA     22.18mA    43.75mA
2.2V      35.39mA    24.02mA    48.45mA
3.7V      36.3mA     23.5mA     50.91mA
4.2V      29.62mA    17.57mA    45.56mA
5.2V      11.29mA    3.715mA    22.78mA
5.7V      5.73mA     1.467mA    13.24mA
6.6V      1.129mA    616.6uA    3.568mA
[Pullup]
|   voltage   I(typ)   I(min)   I(max)
-3.3V     5.396mA    1.593mA    9.846mA
-1.7V     14.1mA     7.028mA    20.86mA
-600mV    11.14mA    7.391mA    15.31mA
1.3V      -29.12mA   -18.58mA   -38.91mA
2.2V      -45.34mA   -26.59mA   -61.37mA
3V        -53.59mA   -29.28mA   -75.95mA
3.8V      -56.59mA   -28.4mA    -83.18mA
4.3V      -49.37mA   -20.37mA   -77.33mA
5.2V      -26.74mA   -4.177mA   -54.59mA
5.8V      -10.99mA   -1.259mA   -33.78mA
6.3V      -4.974mA   -743uA     -17.68mA
6.6V      -2.652mA   -591.1uA   -12.21mA
[GND_clamp]
|   voltage   I(typ)   I(min)   I(max)
-3.3V     -103.4mA   -79.14mA   -123mA
-1.233V   -19.94mA   -17.59mA   -24.08mA
-1.167V   -17.56mA   -15.64mA   -21.36mA
-1.1V     -15.26mA   -13.71mA   -18.66mA
-1.033V   -13.1mA    -11.83mA   -16.04mA
-900mV    -8.949mA   -8.213mA   -11.09mA
-766.7mV  -5.469mA   -5.016mA   -7.34mA
-700mV    -4.037mA   -3.573mA   -5.7mA
-500mV    -1.031mA   -820.7uA   -1.629mA
-366.7mV  -182.7uA   -178.8uA   -313uA
-166.7mV  -5.406uA   -6.461uA   -7.337uA
3.233V    80.21nA    2.439uA    206.4nA
[Ramp]
| variable   typ   min   max
dV/dt_f 0.98700834/1.8960887n 0.74650007/3.6591671n  1.2046935/1.0118155n
dV/dt_r  1.0418117/1.2291844n 0.75526144/2.5945409n  1.2520654/0.68528301n
R_load = 50
[Rising Waveform]
R_fixture = 50.0000
V_fixture = 3.3
V_fixture_min = 3.14
V_fixture_max = 3.47
|   time   V(typ)   V(min)   V(max)
147ps     1.676V     1.965V     1.481V
236.6ps   1.676V     1.965V     1.701V
355ps     1.702V     1.965V     2.829V
434.3ps   1.865V     1.965V     3.052V
585.8ps   2.792V     1.965V     3.312V
802.7ps   3.136V     1.98V      3.441V
975.8ps   3.229V     2.12V      3.46V
1.222ns   3.273V     2.809V     3.465V
1.61ns    3.291V     3.072V     3.468V
6.996ns   3.3V       3.14V      3.47V
[Rising Waveform]
R_fixture = 50.0000
V_fixture = 0
V_fixture_min = 0
V_fixture_max = 0
|   time   V(typ)   V(min)   V(max)
115.1fs   44.34uV    22.86uV    73.1uV
724.3ps   -3.306mV   -195.7uV   33.71mV
1.224ns   3.759mV    -4.133mV   684.5mV
1.619ns   204mV      -843uV     1.55V
2.194ns   551.7mV    34.71uV    1.957V
2.889ns   1.253V     4.098mV    2.049V
3.667ns   1.587V     145.9mV    2.066V
5.381ns   1.705V     492.7mV    2.074V
6.842ns   1.718V     1.011V     2.076V
6.849ns   1.728V     1.24V      2.077V
[Falling Waveform]
R_fixture = 50.0000
V_fixture = 3.3
V_fixture_min = 3.14
V_fixture_max = 3.47
|   time   V(typ)   V(min)   V(max)
147ps     3.3V       3.14V      3.47V
452.9ps   3.31V      3.142V     3.457V
853.3ps   3.281V     3.148V     3.059V
1.101ns   3.145V     3.144V     2.779V
1.524ns   2.963V     3.139V     2.129V
2.329ns   2.422V     3.008V     1.639V
3.482ns   1.962V     2.775V     1.506V
4.241ns   1.774V     2.669V     1.492V
6.945ns   1.673V     2.093V     1.484V
6.996ns   1.676V     1.965V     1.481V
[Falling Waveform]
R_fixture = 50.0000
V_fixture = 0
V_fixture_min = 0
V_fixture_max = 0
|   time   V(typ)   V(min)   V(max)
115.1fs   1.728V     1.24V      2.077V
74.02ps   1.721V     1.242V     2.004V
111.3ps   1.71V      1.242V     1.862V
223.8ps   1.558V     1.236V     736.5mV
261.9ps   1.413V     1.231V     514mV
401.9ps   497.4mV    1.185V     213mV
585.8ps   189.8mV    933.8mV    33.14mV
836.3ps   44.83mV    330.6mV    7.963mV
1.222ns   8.785mV    72.96mV    3.384mV
6.849ns   44.34uV    22.86uV    73.1uV
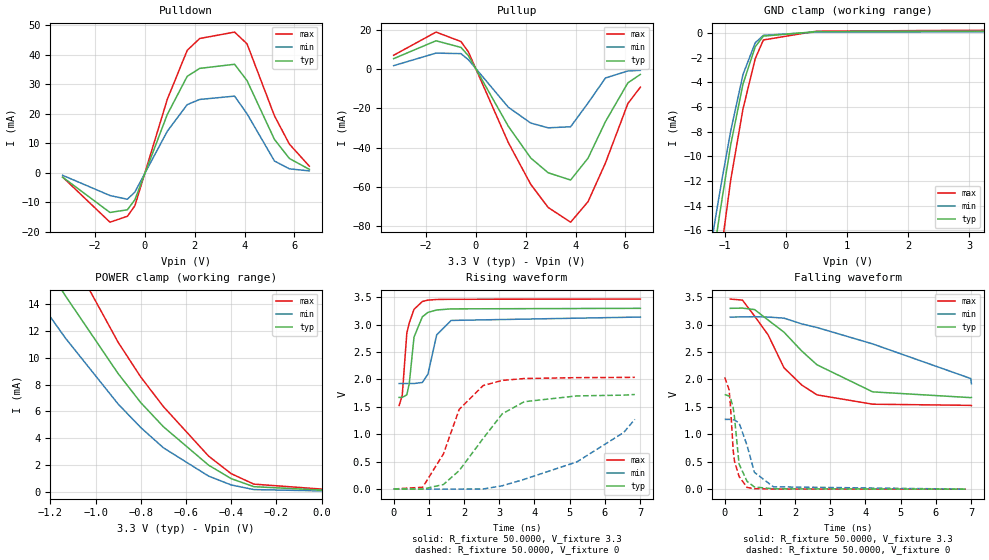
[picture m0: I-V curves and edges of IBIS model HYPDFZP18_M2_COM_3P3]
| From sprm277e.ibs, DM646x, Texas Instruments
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|   Model Cell HYPDFZP18_M2_COM_3P3
[Model]   HYPDFZP18_M2_COM_3P3
Model_type   I/O
Polarity   Non-Inverting
Enable   Active-Low
Vinl =  0.8V
Vinh =  2V
Cref =  10.0000pF
Rref =  50.0000
Vref =  1.5V
Vmeas =  1.65
C_comp   1.737544p   1.691525p   1.779952p
[Model Spec]
Vinl   0.8V   0.8V   0.8V
Vinh   2V   2V   2V
[Temperature Range]   25   105   0
[Voltage Range]   3.3   3.14   3.47
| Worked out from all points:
|   slope of the pulldown table from 0 to 0.495 V, typ, clamps not added: 44 ohm
|   slope of the pullup table from 0 to 0.495 V, typ, clamps not added: 42.8 ohm
|   GND clamp passes 1 mA (typ) near -0.48 V on its own axis
|   POWER clamp passes 1 mA (typ) near -0.40 V on its own axis
|   rising waveform, R_fixture 50.0000, V_fixture 3.3: 20-80 % time 225ps typ, 309ps min, 190ps max; typ from 1.67 V to 3.3 V
|   rising waveform, R_fixture 50.0000, V_fixture 0: 20-80 % time 1.22ns typ, 2.4ns min, 841ps max; typ from 0 V to 1.73 V
|   falling waveform, R_fixture 50.0000, V_fixture 3.3: 20-80 % time 1.87ns typ, 3.35ns min, 1.22ns max; typ from 3.3 V to 1.67 V
|   falling waveform, R_fixture 50.0000, V_fixture 0: 20-80 % time 201ps typ, 350ps min, 168ps max; typ from 1.73 V to 0 V
[POWER_clamp]
|   voltage   I(typ)   I(min)   I(max)
-3.3V     84.8mA     66.18mA    103.2mA
-1.433V   23.02mA    18.79mA    28.4mA
-1.4V     21.98mA    17.95mA    27.19mA
-1.267V   18.18mA    14.64mA    22.69mA
-1.133V   14.62mA    11.47mA    18.34mA
-900mV    8.824mA    6.555mA    11.16mA
-800mV    6.661mA    4.801mA    8.569mA
-700mV    4.864mA    3.293mA    6.366mA
-500mV    1.995mA    1.178mA    2.672mA
-400mV    988.4uA    519.3uA    1.359mA
-300mV    390.1uA    174.5uA    580.4uA
0V        137uA      76.42uA    211.3uA
[Pulldown]
|   voltage   I(typ)   I(min)   I(max)
-3.3V     -1.512mA   -878.7uA   -1.479mA
-1.4V     -13.5mA    -7.754mA   -16.8mA
-700mV    -12.58mA   -9.011mA   -14.79mA
-400mV    -9.19mA    -6.568mA   -11.22mA
900mV     19.74mA    14.05mA    24.87mA
1.7V      32.7mA     23.1mA     41.52mA
2.2V      35.39mA    24.85mA    45.53mA
3.6V      36.79mA    25.98mA    47.71mA
4.1V      31.25mA    19.99mA    43.72mA
5.2V      11.29mA    3.971mA    19.31mA
5.8V      4.817mA    1.297mA    9.688mA
6.6V      1.129mA    610.1uA    2.216mA
[Pullup]
|   voltage   I(typ)   I(min)   I(max)
-3.3V     5.396mA    1.812mA    7.126mA
-1.6V     14.52mA    8.233mA    18.96mA
-600mV    11.14mA    7.955mA    14.14mA
-300mV    6.902mA    4.842mA    8.81mA
1.3V      -29.12mA   -19.41mA   -37.45mA
2.2V      -45.34mA   -27.5mA    -58.78mA
2.9V      -52.9mA    -29.94mA   -70.62mA
3.8V      -56.6mA    -29.4mA    -78.14mA
4.5V      -45.44mA   -17.28mA   -67.66mA
5.2V      -26.74mA   -4.474mA   -47.85mA
6.1V      -6.94mA    -895.3uA   -17.51mA
6.6V      -2.653mA   -585.2uA   -9.184mA
[GND_clamp]
|   voltage   I(typ)   I(min)   I(max)
-3.3V     -103.4mA   -81.89mA   -123.6mA
-1.3V     -22.44mA   -19.61mA   -27.39mA
-1.233V   -19.98mA   -17.56mA   -24.67mA
-1.167V   -17.61mA   -15.54mA   -21.99mA
-1.1V     -15.33mA   -13.54mA   -19.38mA
-1.033V   -13.19mA   -11.61mA   -16.84mA
-900mV    -9.067mA   -7.945mA   -11.92mA
-700mV    -4.153mA   -3.384mA   -6.174mA
-500mV    -1.132mA   -810uA     -2.099mA
-366.7mV  -266.1uA   -202.6uA   -578.6uA
500mV     98.21uA    59.42uA    133.4uA
3.233V    136.8uA    77.9uA     210.2uA
[Ramp]
| variable   typ   min   max
dV/dt_f 0.98664109/1.8964266n 0.76924514/3.5377829n   1.175527/1.2301742n
dV/dt_r  1.0398667/1.2293169n 0.77513648/2.4479296n  1.2289182/0.84772756n
R_load = 50
[Rising Waveform]
R_fixture = 50.0000
V_fixture = 3.3
V_fixture_min = 3.14
V_fixture_max = 3.47
|   time   V(typ)   V(min)   V(max)
158.6ps   1.672V     1.924V     1.524V
246.5ps   1.672V     1.925V     1.712V
376ps     1.718V     1.925V     2.845V
446.4ps   1.927V     1.925V     3.032V
579.8ps   2.771V     1.925V     3.278V
815.7ps   3.141V     1.944V     3.421V
976.2ps   3.223V     2.096V     3.447V
1.224ns   3.267V     2.812V     3.458V
1.635ns   3.287V     3.076V     3.462V
7.008ns   3.297V     3.138V     3.466V
[Rising Waveform]
R_fixture = 50.0000
V_fixture = 0
V_fixture_min = 0
V_fixture_max = 0
|   time   V(typ)   V(min)   V(max)
2.182ps   44.4uV     21.49uV    73.03uV
826.7ps   -1.441mV   -574.8uV   32.62mV
1.415ns   81.96mV    -2.797mV   639.2mV
1.863ns   335.7mV    -107.4uV   1.453V
2.544ns   923.2mV    319.7uV    1.888V
3.088ns   1.373V     59.59mV    1.982V
3.71ns    1.593V     176.6mV    2.016V
5.204ns   1.699V     494.7mV    2.032V
6.536ns   1.713V     1.032V     2.036V
6.851ns   1.725V     1.272V     2.038V
[Falling Waveform]
R_fixture = 50.0000
V_fixture = 3.3
V_fixture_min = 3.14
V_fixture_max = 3.47
|   time   V(typ)   V(min)   V(max)
158.6ps   3.297V     3.138V     3.466V
506.3ps   3.301V     3.14V      3.447V
852.1ps   3.274V     3.145V     3.155V
1.235ns   3.083V     3.138V     2.813V
1.685ns   2.863V     3.118V     2.214V
2.191ns   2.518V     3.013V     1.898V
2.624ns   2.267V     2.947V     1.719V
4.206ns   1.774V     2.648V     1.549V
6.989ns   1.669V     2.017V     1.528V
7.008ns   1.672V     1.924V     1.524V
[Falling Waveform]
R_fixture = 50.0000
V_fixture = 0
V_fixture_min = 0
V_fixture_max = 0
|   time   V(typ)   V(min)   V(max)
2.182ps   1.725V     1.272V     2.038V
126.5ps   1.698V     1.273V     1.816V
167.3ps   1.663V     1.272V     1.506V
243.3ps   1.484V     1.265V     705.3mV
279.5ps   1.314V     1.259V     510.5mV
410.2ps   459.9mV    1.209V     231.9mV
636.7ps   143mV      799.5mV    31.65mV
846.2ps   40.4mV     306.4mV    9.569mV
1.384ns   6.237mV    43.21mV    3.001mV
6.851ns   44.4uV     21.49uV    73.03uV
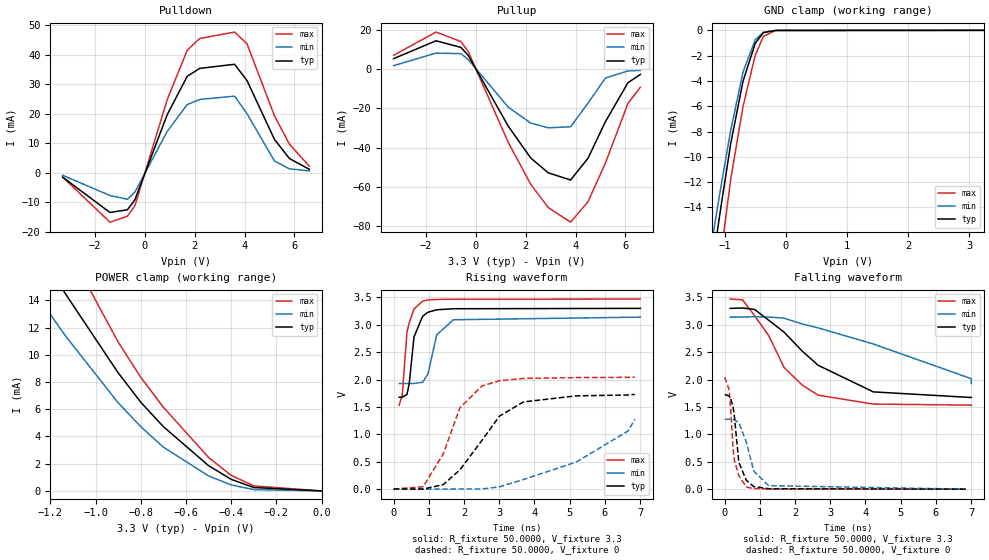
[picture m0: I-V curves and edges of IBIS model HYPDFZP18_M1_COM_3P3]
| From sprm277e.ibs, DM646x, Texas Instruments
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|   Model Cell HYPDFZP18_M1_COM_3P3
[Model]   HYPDFZP18_M1_COM_3P3
Model_type   I/O
Polarity   Non-Inverting
Enable   Active-Low
Vinl =  0.8V
Vinh =  2V
Cref =  10.0000pF
Rref =  50.0000
Vref =  1.5V
Vmeas =  1.65
C_comp   1.737544p   1.691525p   1.779952p
[Model Spec]
Vinl   0.8V   0.8V   0.8V
Vinh   2V   2V   2V
[Temperature Range]   25   105   0
[Voltage Range]   3.3   3.14   3.47
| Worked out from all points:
|   slope of the pulldown table from 0 to 0.495 V, typ, clamps not added: 44 ohm
|   slope of the pullup table from 0 to 0.495 V, typ, clamps not added: 42.8 ohm
|   GND clamp passes 1 mA (typ) near -0.50 V on its own axis
|   POWER clamp passes 1 mA (typ) near -0.41 V on its own axis
|   rising waveform, R_fixture 50.0000, V_fixture 3.3: 20-80 % time 225ps typ, 309ps min, 188ps max; typ from 1.68 V to 3.3 V
|   rising waveform, R_fixture 50.0000, V_fixture 0: 20-80 % time 1.22ns typ, 2.4ns min, 843ps max; typ from 0 V to 1.73 V
|   falling waveform, R_fixture 50.0000, V_fixture 3.3: 20-80 % time 1.87ns typ, 3.34ns min, 1.22ns max; typ from 3.3 V to 1.68 V
|   falling waveform, R_fixture 50.0000, V_fixture 0: 20-80 % time 203ps typ, 351ps min, 170ps max; typ from 1.73 V to 0 V
[POWER_clamp]
|   voltage   I(typ)   I(min)   I(max)
-3.3V     84.55mA    66.04mA    102.9mA
-1.433V   22.87mA    18.71mA    28.16mA
-1.4V     21.83mA    17.86mA    26.96mA
-1.267V   18.03mA    14.55mA    22.46mA
-1.133V   14.48mA    11.39mA    18.11mA
-900mV    8.681mA    6.476mA    10.94mA
-800mV    6.518mA    4.722mA    8.35mA
-700mV    4.722mA    3.215mA    6.148mA
-500mV    1.856mA    1.101mA    2.457mA
-400mV    849.7uA    442.1uA    1.145mA
-300mV    252uA      97.6uA     367.5uA
0V        112nA      124.6nA    531.6nA
[Pulldown]
|   voltage   I(typ)   I(min)   I(max)
-3.3V     -1.512mA   -878.7uA   -1.479mA
-1.4V     -13.5mA    -7.754mA   -16.8mA
-700mV    -12.58mA   -9.011mA   -14.79mA
-400mV    -9.19mA    -6.568mA   -11.22mA
900mV     19.74mA    14.05mA    24.87mA
1.7V      32.7mA     23.1mA     41.52mA
2.2V      35.39mA    24.85mA    45.53mA
3.6V      36.79mA    25.98mA    47.71mA
4.1V      31.25mA    19.99mA    43.72mA
5.2V      11.29mA    3.971mA    19.31mA
5.8V      4.817mA    1.297mA    9.687mA
6.6V      1.129mA    610.1uA    2.215mA
[Pullup]
|   voltage   I(typ)   I(min)   I(max)
-3.3V     5.396mA    1.812mA    7.126mA
-1.6V     14.52mA    8.233mA    18.96mA
-600mV    11.14mA    7.955mA    14.14mA
-300mV    6.902mA    4.842mA    8.811mA
1.3V      -29.12mA   -19.41mA   -37.45mA
2.2V      -45.34mA   -27.5mA    -58.77mA
2.9V      -52.91mA   -29.94mA   -70.62mA
3.8V      -56.6mA    -29.4mA    -78.14mA
4.5V      -45.44mA   -17.28mA   -67.65mA
5.2V      -26.74mA   -4.474mA   -47.85mA
6.1V      -6.94mA    -895.3uA   -17.51mA
6.6V      -2.653mA   -585.2uA   -9.184mA
[GND_clamp]
|   voltage   I(typ)   I(min)   I(max)
-3.3V     -103.4mA   -81.89mA   -123.6mA
-1.3V     -22.42mA   -19.6mA    -27.37mA
-1.233V   -19.94mA   -17.55mA   -24.63mA
-1.167V   -17.56mA   -15.52mA   -21.93mA
-1.1V     -15.26mA   -13.51mA   -19.29mA
-1.033V   -13.1mA    -11.58mA   -16.72mA
-900mV    -8.949mA   -7.893mA   -11.77mA
-700mV    -4.037mA   -3.312mA   -6.032mA
-500mV    -1.031mA   -744.5uA   -1.975mA
-366.7mV  -182.7uA   -147.8uA   -475.2uA
-166.7mV  -5.406uA   -4.997uA   -10.97uA
3.233V    80.21nA    1.448uA    401.1nA
[Ramp]
| variable   typ   min   max
dV/dt_f 0.98696747/1.8957249n   0.769503/3.5368781n  1.1759672/1.229781n
dV/dt_r  1.0418195/1.2291532n 0.77656629/2.4477142n  1.2315041/0.84693936n
R_load = 50
[Rising Waveform]
R_fixture = 50.0000
V_fixture = 3.3
V_fixture_min = 3.14
V_fixture_max = 3.47
|   time   V(typ)   V(min)   V(max)
158.5ps   1.676V     1.928V     1.53V
246.5ps   1.676V     1.928V     1.718V
379.9ps   1.727V     1.928V     2.864V
446.3ps   1.932V     1.928V     3.041V
580ps     2.778V     1.928V     3.288V
823.4ps   3.154V     1.95V      3.432V
976.2ps   3.23V      2.1V       3.454V
1.224ns   3.274V     2.815V     3.463V
1.698ns   3.293V     3.092V     3.467V
7.008ns   3.3V       3.14V      3.47V
[Rising Waveform]
R_fixture = 50.0000
V_fixture = 0
V_fixture_min = 0
V_fixture_max = 0
|   time   V(typ)   V(min)   V(max)
2.294ps   44.34uV    21.43uV    72.87uV
837.9ps   -1.353mV   -604.3uV   40.9mV
1.411ns   80mV       -2.877mV   640.8mV
1.885ns   351.4mV    -89.68uV   1.486V
2.514ns   892.6mV    221.9uV    1.884V
3.008ns   1.332V     40.55mV    1.978V
3.686ns   1.591V     173mV      2.02V
5.187ns   1.702V     492.3mV    2.036V
6.66ns    1.717V     1.061V     2.04V
6.852ns   1.728V     1.275V     2.043V
[Falling Waveform]
R_fixture = 50.0000
V_fixture = 3.3
V_fixture_min = 3.14
V_fixture_max = 3.47
|   time   V(typ)   V(min)   V(max)
158.5ps   3.3V       3.14V      3.47V
506.2ps   3.307V     3.142V     3.457V
854.7ps   3.28V      3.148V     3.163V
1.254ns   3.082V     3.142V     2.802V
1.689ns   2.866V     3.121V     2.22V
2.196ns   2.525V     3.017V     1.904V
2.656ns   2.261V     2.944V     1.716V
4.222ns   1.776V     2.65V      1.553V
7.004ns   1.673V     2.017V     1.534V
7.008ns   1.676V     1.928V     1.53V
[Falling Waveform]
R_fixture = 50.0000
V_fixture = 0
V_fixture_min = 0
V_fixture_max = 0
|   time   V(typ)   V(min)   V(max)
2.294ps   1.728V     1.275V     2.043V
126.5ps   1.701V     1.276V     1.822V
167.4ps   1.667V     1.275V     1.512V
241.8ps   1.494V     1.268V     726.8mV
278ps     1.327V     1.262V     522.1mV
403ps     490mV      1.216V     249.4mV
616.8ps   161.4mV    857.8mV    38.94mV
828.9ps   46.69mV    328.1mV    10.44mV
1.252ns   8.188mV    63.83mV    3.783mV
6.852ns   44.34uV    21.43uV    72.87uV
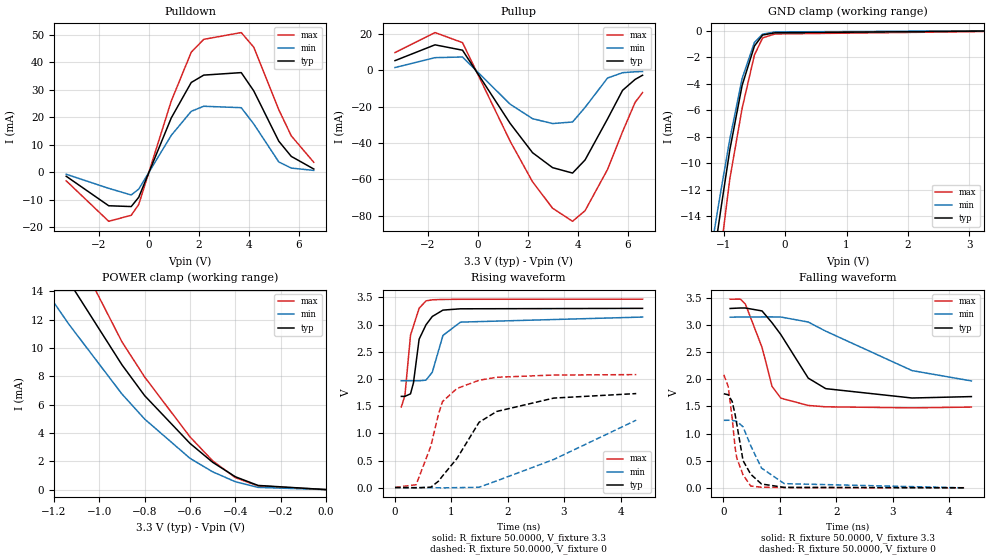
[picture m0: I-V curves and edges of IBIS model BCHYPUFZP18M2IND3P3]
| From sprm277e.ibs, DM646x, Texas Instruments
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|   Model Cell HYPUFZP18_M2_IND_3P3
[Model]   BCHYPUFZP18M2IND3P3
Model_type   I/O
Polarity   Non-Inverting
Enable   Active-Low
Vinl =  0.8V
Vinh =  2V
Cref =  10.0000pF
Rref =  50.0000
Vref =  1.5V
Vmeas =  1.65
C_comp   1.705749p   1.660791p   1.75003p
[Model Spec]
Vinl   0.8V   0.8V   0.8V
Vinh   2V   2V   2V
[Temperature Range]   25   125   -40
[Voltage Range]   3.3   3.14   3.47
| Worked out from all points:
|   slope of the pulldown table from 0 to 0.495 V, typ, clamps not added: 44 ohm
|   slope of the pullup table from 0 to 0.495 V, typ, clamps not added: 42.8 ohm
|   GND clamp passes 1 mA (typ) near -0.48 V on its own axis
|   POWER clamp passes 1 mA (typ) near -0.41 V on its own axis
|   rising waveform, R_fixture 50.0000, V_fixture 3.3: 20-80 % time 201ps typ, 269ps min, 158ps max; typ from 1.68 V to 3.3 V
|   rising waveform, R_fixture 50.0000, V_fixture 0: 20-80 % time 822ps typ, 1.71ns min, 370ps max; typ from 0.003 V to 1.73 V
|   falling waveform, R_fixture 50.0000, V_fixture 3.3: 20-80 % time 611ps typ, 1.46ns min, 343ps max; typ from 3.3 V to 1.68 V
|   falling waveform, R_fixture 50.0000, V_fixture 0: 20-80 % time 220ps typ, 394ps min, 170ps max; typ from 1.73 V to 0.003 V
[POWER_clamp]
|   voltage   I(typ)   I(min)   I(max)
-3.3V     86.16mA    64.93mA    104.3mA
-1.4V     22.19mA    18mA       26.83mA
-1.367V   21.21mA    17.19mA    25.67mA
-1.233V   17.38mA    13.98mA    21.08mA
-1.133V   14.68mA    11.66mA    17.73mA
-900mV    8.815mA    6.753mA    10.44mA
-800mV    6.637mA    4.985mA    7.954mA
-600mV    3.264mA    2.209mA    3.724mA
-500mV    1.928mA    1.255mA    2.032mA
-400mV    906.7uA    556.3uA    845.1uA
-300mV    294.4uA    156.7uA    257.3uA
0V        111.7nA    201.4nA    235.1nA
[Pulldown]
|   voltage   I(typ)   I(min)   I(max)
-3.3V     -1.512mA   -788.7uA   -3.179mA
-1.6V     -12.28mA   -5.921mA   -17.95mA
-700mV    -12.57mA   -8.351mA   -15.75mA
-400mV    -9.189mA   -6.204mA   -11.82mA
900mV     19.74mA    13.39mA    25.89mA
1.7V      32.7mA     22.18mA    43.75mA
2.2V      35.39mA    24.02mA    48.44mA
3.7V      36.3mA     23.5mA     50.91mA
4.2V      29.63mA    17.57mA    45.56mA
5.2V      11.29mA    3.715mA    22.78mA
5.7V      5.729mA    1.466mA    13.23mA
6.6V      1.129mA    616.5uA    3.566mA
[Pullup]
|   voltage   I(typ)   I(min)   I(max)
-3.3V     5.393mA    1.594mA    9.841mA
-1.7V     14.1mA     7.03mA     20.86mA
-600mV    11.14mA    7.392mA    15.31mA
1.3V      -29.12mA   -18.58mA   -38.9mA
2.2V      -45.34mA   -26.6mA    -61.37mA
3V        -53.58mA   -29.29mA   -75.93mA
3.8V      -56.58mA   -28.42mA   -83.16mA
4.3V      -49.36mA   -20.39mA   -77.31mA
5.2V      -26.72mA   -4.188mA   -54.56mA
5.8V      -10.98mA   -1.261mA   -33.74mA
6.3V      -4.972mA   -743.5uA   -17.65mA
6.6V      -2.65mA    -591.4uA   -12.2mA
[GND_clamp]
|   voltage   I(typ)   I(min)   I(max)
-3.3V     -101.9mA   -78.12mA   -120.9mA
-1.3V     -22.23mA   -19.37mA   -26.67mA
-1.233V   -19.8mA    -17.42mA   -23.99mA
-1.167V   -17.46mA   -15.5mA    -21.32mA
-1.1V     -15.2mA    -13.6mA    -18.67mA
-1.033V   -13.07mA   -11.75mA   -16.09mA
-900mV    -8.981mA   -8.175mA   -11.18mA
-700mV    -4.114mA   -3.591mA   -5.848mA
-500mV    -1.143mA   -868.3uA   -1.823mA
-366.7mV  -309.8uA   -238.3uA   -526uA
-166.7mV  -140.6uA   -73.42uA   -228.8uA
3.233V    -8.734uA   9.999uA    -45.21uA
[Ramp]
| variable   typ   min   max
dV/dt_f 0.99810179/0.63321517n 0.75549686/1.6093729n  1.2053371/0.34770363n
dV/dt_r  1.0435425/0.82612642n 0.76120691/2.3355085n  1.2520535/0.37164608n
R_load = 50
[Rising Waveform]
R_fixture = 50.0000
V_fixture = 3.3
V_fixture_min = 3.14
V_fixture_max = 3.47
|   time   V(typ)   V(min)   V(max)
118ps     1.68V      1.968V     1.487V
181.3ps   1.681V     1.969V     1.697V
280.6ps   1.727V     1.969V     2.808V
332.6ps   1.93V      1.968V     2.977V
432.9ps   2.733V     1.968V     3.302V
555.1ps   2.998V     1.979V     3.438V
666.4ps   3.151V     2.126V     3.458V
855ps     3.268V     2.802V     3.464V
1.166ns   3.292V     3.047V     3.467V
4.391ns   3.3V       3.14V      3.47V
[Rising Waveform]
R_fixture = 50.0000
V_fixture = 0
V_fixture_min = 0
V_fixture_max = 0
|   time   V(typ)   V(min)   V(max)
5.559ps   3.146mV    1.893mV    4.431mV
379.8ps   -2.066mV   1.898mV    54.34mV
640.2ps   9.37mV     536.2uV    764.3mV
775.8ps   119.7mV    -1.458mV   1.355V
847.2ps   215.1mV    -3.116mV   1.584V
1.102ns   536.1mV    1.135mV    1.825V
1.495ns   1.204V     7.617mV    1.977V
1.808ns   1.403V     126.2mV    2.032V
2.818ns   1.649V     519.5mV    2.073V
4.279ns   1.732V     1.243V     2.081V
[Falling Waveform]
R_fixture = 50.0000
V_fixture = 3.3
V_fixture_min = 3.14
V_fixture_max = 3.47
|   time   V(typ)   V(min)   V(max)
118ps     3.3V       3.14V      3.47V
301ps     3.309V     3.143V     3.472V
388.4ps   3.309V     3.143V     3.379V
682.9ps   3.255V     3.145V     2.585V
860.8ps   3.037V     3.145V     1.867V
1.016ns   2.82V      3.143V     1.651V
1.501ns   2.02V      3.051V     1.517V
1.811ns   1.826V     2.883V     1.492V
3.34ns    1.654V     2.158V     1.473V
4.391ns   1.68V      1.968V     1.487V
[Falling Waveform]
R_fixture = 50.0000
V_fixture = 0
V_fixture_min = 0
V_fixture_max = 0
|   time   V(typ)   V(min)   V(max)
5.559ps   1.732V     1.243V     2.081V
83.27ps   1.714V     1.245V     1.866V
154.4ps   1.59V      1.242V     1.282V
205.9ps   1.35V      1.233V     741.6mV
235.7ps   1.174V     1.224V     549.5mV
346.8ps   502mV      1.124V     240.7mV
483.2ps   251.5mV    774.8mV    35.29mV
673ps     72.94mV    366.1mV    13.76mV
1.077ns   10.48mV    79.42mV    7.761mV
4.279ns   3.146mV    1.893mV    4.431mV
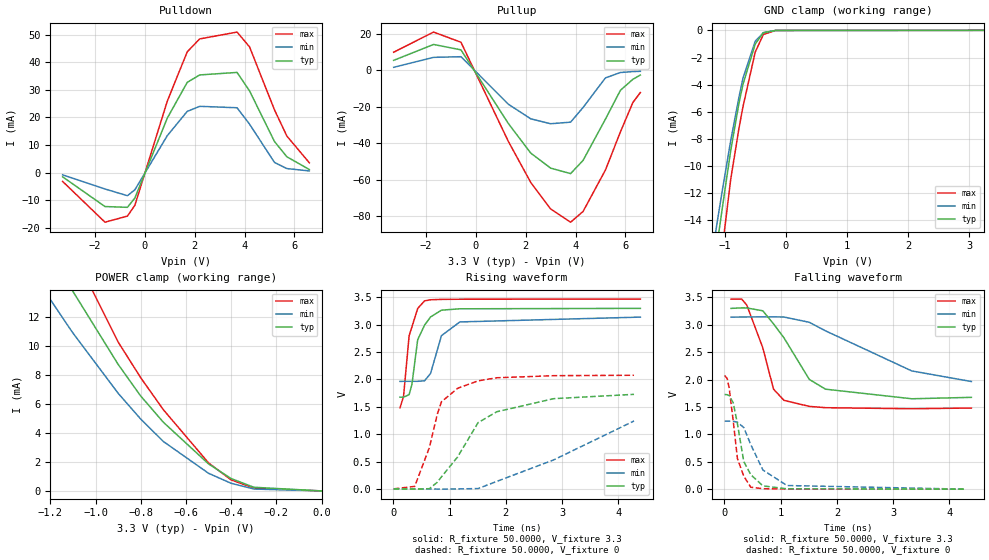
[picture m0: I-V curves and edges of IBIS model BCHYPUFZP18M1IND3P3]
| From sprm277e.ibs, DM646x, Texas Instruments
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|   Model Cell HYPUFZP18_M1_IND_3P3
[Model]   BCHYPUFZP18M1IND3P3
Model_type   I/O
Polarity   Non-Inverting
Enable   Active-Low
Vinl =  0.8V
Vinh =  2V
Cref =  10.0000pF
Rref =  50.0000
Vref =  1.5V
Vmeas =  1.65
C_comp   1.705749p   1.660791p   1.75003p
[Model Spec]
Vinl   0.8V   0.8V   0.8V
Vinh   2V   2V   2V
[Temperature Range]   25   125   -40
[Voltage Range]   3.3   3.14   3.47
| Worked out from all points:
|   slope of the pulldown table from 0 to 0.495 V, typ, clamps not added: 44 ohm
|   slope of the pullup table from 0 to 0.495 V, typ, clamps not added: 42.8 ohm
|   GND clamp passes 1 mA (typ) near -0.50 V on its own axis
|   POWER clamp passes 1 mA (typ) near -0.41 V on its own axis
|   rising waveform, R_fixture 50.0000, V_fixture 3.3: 20-80 % time 203ps typ, 274ps min, 160ps max; typ from 1.68 V to 3.3 V
|   rising waveform, R_fixture 50.0000, V_fixture 0: 20-80 % time 824ps typ, 1.72ns min, 371ps max; typ from 0 V to 1.73 V
|   falling waveform, R_fixture 50.0000, V_fixture 3.3: 20-80 % time 609ps typ, 1.45ns min, 342ps max; typ from 3.3 V to 1.68 V
|   falling waveform, R_fixture 50.0000, V_fixture 0: 20-80 % time 219ps typ, 389ps min, 169ps max; typ from 1.73 V to 0 V
[POWER_clamp]
|   voltage   I(typ)   I(min)   I(max)
-3.3V     86.16mA    64.93mA    104.3mA
-1.367V   21.2mA     17.18mA    25.65mA
-1.233V   17.37mA    13.97mA    21.04mA
-1.133V   14.65mA    11.65mA    17.64mA
-1.1V     13.76mA    10.89mA    16.51mA
-900mV    8.728mA    6.734mA    10.27mA
-800mV    6.541mA    4.954mA    7.803mA
-700mV    4.737mA    3.409mA    5.6mA
-500mV    1.861mA    1.215mA    1.93mA
-400mV    851.5uA    523.4uA    761.4uA
-300mV    252.3uA    131.7uA    194.1uA
0V        112.2nA    201.8nA    235.3nA
[Pulldown]
|   voltage   I(typ)   I(min)   I(max)
-3.3V     -1.512mA   -788.7uA   -3.179mA
-1.6V     -12.28mA   -5.921mA   -17.95mA
-700mV    -12.57mA   -8.351mA   -15.75mA
-400mV    -9.189mA   -6.204mA   -11.82mA
900mV     19.74mA    13.39mA    25.89mA
1.7V      32.7mA     22.18mA    43.75mA
2.2V      35.39mA    24.02mA    48.44mA
3.7V      36.3mA     23.5mA     50.91mA
4.2V      29.63mA    17.57mA    45.56mA
5.2V      11.29mA    3.715mA    22.78mA
5.7V      5.729mA    1.466mA    13.23mA
6.6V      1.129mA    616.5uA    3.566mA
[Pullup]
|   voltage   I(typ)   I(min)   I(max)
-3.3V     5.393mA    1.594mA    9.841mA
-1.7V     14.1mA     7.03mA     20.86mA
-600mV    11.14mA    7.392mA    15.31mA
1.3V      -29.12mA   -18.58mA   -38.9mA
2.2V      -45.34mA   -26.6mA    -61.37mA
3V        -53.58mA   -29.29mA   -75.93mA
3.8V      -56.58mA   -28.42mA   -83.16mA
4.3V      -49.36mA   -20.39mA   -77.3mA
5.2V      -26.72mA   -4.188mA   -54.56mA
5.8V      -10.98mA   -1.261mA   -33.74mA
6.3V      -4.972mA   -743.5uA   -17.65mA
6.6V      -2.65mA    -591.4uA   -12.2mA
[GND_clamp]
|   voltage   I(typ)   I(min)   I(max)
-3.3V     -101.7mA   -78.06mA   -120.7mA
-1.233V   -19.67mA   -17.36mA   -23.78mA
-1.167V   -17.33mA   -15.44mA   -21.11mA
-1.1V     -15.07mA   -13.53mA   -18.46mA
-1.033V   -12.95mA   -11.68mA   -15.88mA
-900mV    -8.853mA   -8.113mA   -10.97mA
-766.7mV  -5.4mA     -4.954mA   -7.25mA
-700mV    -3.98mA    -3.527mA   -5.625mA
-500mV    -1.007mA   -800.9uA   -1.6mA
-366.7mV  -173.9uA   -170.7uA   -303.4uA
-166.7mV  -4.98uA    -6.051uA   -6.594uA
3.233V    80.05nA    2.439uA    205.4nA
[Ramp]
| variable   typ   min   max
dV/dt_f  1.0005683/0.63143773n  0.7569077/1.6067163n  1.2086218/0.3466438n
dV/dt_r  1.0442832/0.8280692n  0.7613438/2.3367337n  1.2534756/0.3726629n
R_load = 50
[Rising Waveform]
R_fixture = 50.0000
V_fixture = 3.3
V_fixture_min = 3.14
V_fixture_max = 3.47
|   time   V(typ)   V(min)   V(max)
118ps     1.676V     1.965V     1.481V
180.6ps   1.676V     1.966V     1.685V
280.8ps   1.723V     1.966V     2.801V
330.2ps   1.909V     1.966V     2.96V
432.9ps   2.727V     1.966V     3.298V
555.1ps   2.993V     1.976V     3.437V
661.8ps   3.143V     2.11V      3.457V
854.6ps   3.267V     2.8V       3.464V
1.183ns   3.292V     3.052V     3.467V
4.392ns   3.3V       3.14V      3.47V
[Rising Waveform]
R_fixture = 50.0000
V_fixture = 0
V_fixture_min = 0
V_fixture_max = 0
|   time   V(typ)   V(min)   V(max)
5.487ps   38.02uV    22.52uV    59.66uV
379.8ps   -5.798mV   27.44uV    44.91mV
640.2ps   3.09mV     -1.373mV   753.3mV
781.3ps   120.3mV    -3.809mV   1.365V
854.4ps   218.4mV    -5.69mV    1.591V
1.142ns   582.6mV    -1.611mV   1.838V
1.507ns   1.211V     5.499mV    1.975V
1.84ns    1.41V      136.8mV    2.031V
2.851ns   1.649V     529.3mV    2.069V
4.279ns   1.728V     1.241V     2.077V
[Falling Waveform]
R_fixture = 50.0000
V_fixture = 3.3
V_fixture_min = 3.14
V_fixture_max = 3.47
|   time   V(typ)   V(min)   V(max)
118ps     3.3V       3.14V      3.47V
307.1ps   3.309V     3.143V     3.47V
397.4ps   3.308V     3.143V     3.362V
682.1ps   3.256V     3.145V     2.583V
873.8ps   3.017V     3.145V     1.825V
1.06ns    2.761V     3.142V     1.621V
1.51ns    2.003V     3.046V     1.511V
1.798ns   1.825V     2.89V      1.487V
3.332ns   1.65V      2.158V     1.468V
4.392ns   1.676V     1.965V     1.481V
[Falling Waveform]
R_fixture = 50.0000
V_fixture = 0
V_fixture_min = 0
V_fixture_max = 0
|   time   V(typ)   V(min)   V(max)
5.487ps   1.728V     1.241V     2.077V
50.08ps   1.724V     1.241V     2.018V
86.25ps   1.709V     1.242V     1.84V
157.1ps   1.576V     1.239V     1.245V
231.9ps   1.193V     1.223V     558.1mV
344.6ps   504.6mV    1.125V     237.3mV
469.5ps   264.3mV    812.1mV    35.28mV
684.6ps   59.81mV    349.7mV    8.543mV
1.113ns   6.462mV    66.61mV    2.994mV
4.279ns   38.02uV    22.52uV    59.66uV
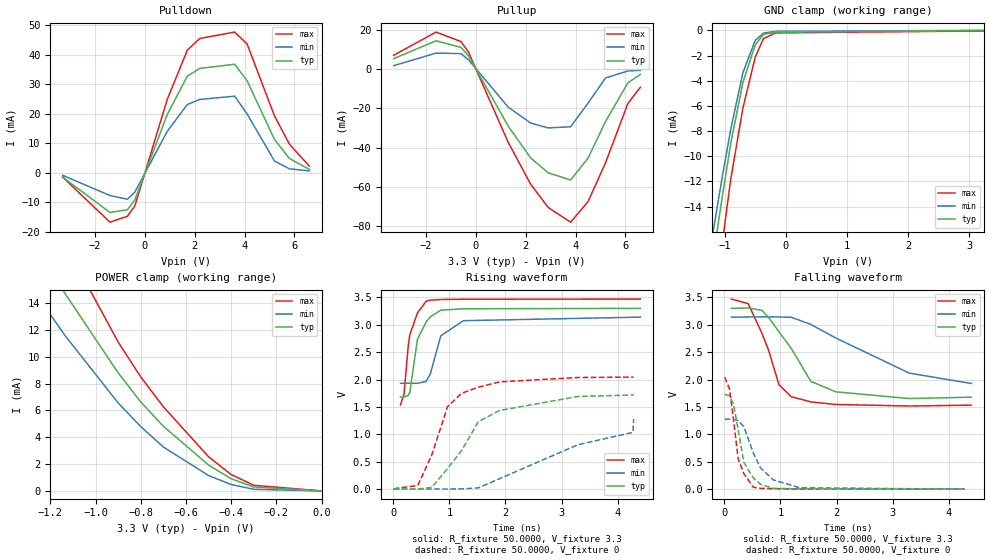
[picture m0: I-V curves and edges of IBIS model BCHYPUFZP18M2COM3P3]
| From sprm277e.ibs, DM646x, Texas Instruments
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|   Model Cell HYPUFZP18_M2_COM_3P3
[Model]   BCHYPUFZP18M2COM3P3
Model_type   I/O
Polarity   Non-Inverting
Enable   Active-Low
Vinl =  0.8V
Vinh =  2V
Cref =  10.0000pF
Rref =  50.0000
Vref =  1.5V
Vmeas =  1.65
C_comp   1.705749p   1.661847p   1.750916p
[Model Spec]
Vinl   0.8V   0.8V   0.8V
Vinh   2V   2V   2V
[Temperature Range]   25   105   0
[Voltage Range]   3.3   3.14   3.47
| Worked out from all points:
|   slope of the pulldown table from 0 to 0.495 V, typ, clamps not added: 44 ohm
|   slope of the pullup table from 0 to 0.495 V, typ, clamps not added: 42.8 ohm
|   GND clamp passes 1 mA (typ) near -0.48 V on its own axis
|   POWER clamp passes 1 mA (typ) near -0.41 V on its own axis
|   rising waveform, R_fixture 50.0000, V_fixture 3.3: 20-80 % time 201ps typ, 263ps min, 171ps max; typ from 1.68 V to 3.3 V
|   rising waveform, R_fixture 50.0000, V_fixture 0: 20-80 % time 819ps typ, 2.15ns min, 458ps max; typ from 0.003 V to 1.73 V
|   falling waveform, R_fixture 50.0000, V_fixture 3.3: 20-80 % time 611ps typ, 1.43ns min, 396ps max; typ from 3.3 V to 1.68 V
|   falling waveform, R_fixture 50.0000, V_fixture 0: 20-80 % time 220ps typ, 380ps min, 177ps max; typ from 1.73 V to 0.003 V
[POWER_clamp]
|   voltage   I(typ)   I(min)   I(max)
-3.3V     86.16mA    67.13mA    105mA
-1.433V   23.25mA    19mA       28.67mA
-1.4V     22.19mA    18.14mA    27.43mA
-1.267V   18.31mA    14.78mA    22.81mA
-1.133V   14.68mA    11.55mA    18.37mA
-900mV    8.815mA    6.567mA    11.11mA
-800mV    6.637mA    4.798mA    8.501mA
-700mV    4.825mA    3.279mA    6.279mA
-500mV    1.928mA    1.146mA    2.548mA
-400mV    906.7uA    477.8uA    1.218mA
-300mV    294.4uA    124uA      421.6uA
0V        111.7nA    122.5nA    531.5nA
[Pulldown]
|   voltage   I(typ)   I(min)   I(max)
-3.3V     -1.512mA   -878.8uA   -1.478mA
-1.4V     -13.5mA    -7.754mA   -16.8mA
-700mV    -12.57mA   -9.009mA   -14.79mA
-400mV    -9.189mA   -6.567mA   -11.22mA
900mV     19.74mA    14.05mA    24.87mA
1.7V      32.7mA     23.11mA    41.52mA
2.2V      35.39mA    24.85mA    45.53mA
3.6V      36.79mA    25.96mA    47.71mA
4.1V      31.25mA    19.99mA    43.72mA
5.2V      11.29mA    3.971mA    19.31mA
5.8V      4.815mA    1.297mA    9.686mA
6.6V      1.129mA    609.9uA    2.214mA
[Pullup]
|   voltage   I(typ)   I(min)   I(max)
-3.3V     5.393mA    1.813mA    7.121mA
-1.6V     14.52mA    8.235mA    18.96mA
-600mV    11.14mA    7.956mA    14.14mA
-300mV    6.901mA    4.842mA    8.81mA
1.3V      -29.12mA   -19.41mA   -37.44mA
2.2V      -45.34mA   -27.51mA   -58.77mA
2.9V      -52.9mA    -29.96mA   -70.6mA
3.8V      -56.59mA   -29.42mA   -78.12mA
4.5V      -45.43mA   -17.3mA    -67.63mA
5.2V      -26.73mA   -4.487mA   -47.82mA
6.1V      -6.938mA   -896.3uA   -17.48mA
6.6V      -2.651mA   -585.7uA   -9.175mA
[GND_clamp]
|   voltage   I(typ)   I(min)   I(max)
-3.3V     -101.9mA   -80.83mA   -121.5mA
-1.3V     -22.23mA   -19.41mA   -27.14mA
-1.233V   -19.8mA    -17.39mA   -24.46mA
-1.167V   -17.46mA   -15.39mA   -21.82mA
-1.1V     -15.2mA    -13.41mA   -19.24mA
-1.033V   -13.07mA   -11.5mA    -16.71mA
-900mV    -8.981mA   -7.864mA   -11.83mA
-700mV    -4.114mA   -3.336mA   -6.145mA
-500mV    -1.143mA   -796uA     -2.132mA
-366.7mV  -309.8uA   -211uA     -651.9uA
-166.7mV  -140.6uA   -75.06uA   -198.8uA
3.233V    -8.732uA   9.395uA    -38.37uA
[Ramp]
| variable   typ   min   max
dV/dt_f 0.99811603/0.63331585n 0.77842795/1.5763011n  1.1777301/0.40170142n
dV/dt_r  1.0435458/0.82616189n  0.7825142/2.2295515n  1.2316706/0.46155741n
R_load = 50
[Rising Waveform]
R_fixture = 50.0000
V_fixture = 3.3
V_fixture_min = 3.14
V_fixture_max = 3.47
|   time   V(typ)   V(min)   V(max)
128.6ps   1.68V      1.93V      1.535V
192.3ps   1.681V     1.932V     1.73V
267.7ps   1.71V      1.932V     2.612V
296.2ps   1.766V     1.931V     2.819V
432ps     2.735V     1.931V     3.217V
585.6ps   3.05V      1.964V     3.429V
662.3ps   3.148V     2.106V     3.451V
847.7ps   3.267V     2.799V     3.462V
1.249ns   3.293V     3.075V     3.467V
4.402ns   3.3V       3.14V      3.47V
[Rising Waveform]
R_fixture = 50.0000
V_fixture = 0
V_fixture_min = 0
V_fixture_max = 0
|   time   V(typ)   V(min)   V(max)
8.181ps   3.146mV    1.93mV     3.847mV
437.5ps   -3.235mV   1.924mV    64.06mV
689ps     30.14mV    414.7uV    627.4mV
968.5ps   374.5mV    -1.086mV   1.504V
1.218ns   702.8mV    2.507mV    1.749V
1.515ns   1.229V     19.72mV    1.859V
1.895ns   1.435V     188.4mV    1.957V
3.288ns   1.69V      808.7mV    2.037V
4.271ns   1.717V     1.035V     2.044V
4.282ns   1.732V     1.278V     2.046V
[Falling Waveform]
R_fixture = 50.0000
V_fixture = 3.3
V_fixture_min = 3.14
V_fixture_max = 3.47
|   time   V(typ)   V(min)   V(max)
128.6ps   3.3V       3.14V      3.47V
425.8ps   3.307V     3.143V     3.387V
669.1ps   3.265V     3.145V     2.85V
788.5ps   3.137V     3.146V     2.54V
974.4ps   2.873V     3.143V     1.907V
1.194ns   2.569V     3.138V     1.689V
1.543ns   1.968V     3.007V     1.594V
1.986ns   1.778V     2.76V      1.547V
3.297ns   1.655V     2.118V     1.519V
4.402ns   1.68V      1.93V      1.535V
[Falling Waveform]
R_fixture = 50.0000
V_fixture = 0
V_fixture_min = 0
V_fixture_max = 0
|   time   V(typ)   V(min)   V(max)
8.181ps   1.732V     1.278V     2.046V
93.6ps    1.706V     1.279V     1.83V
163.9ps   1.551V     1.275V     1.278V
248.2ps   1.088V     1.252V     553.2mV
349.9ps   487.9mV    1.141V     285.2mV
516.4ps   209.3mV    666.7mV    37.97mV
647.2ps   90.18mV    388.4mV    16.39mV
873.8ps   16.96mV    170.9mV    9.888mV
1.349ns   7.81mV     27.24mV    6.272mV
4.282ns   3.146mV    1.93mV     3.847mV
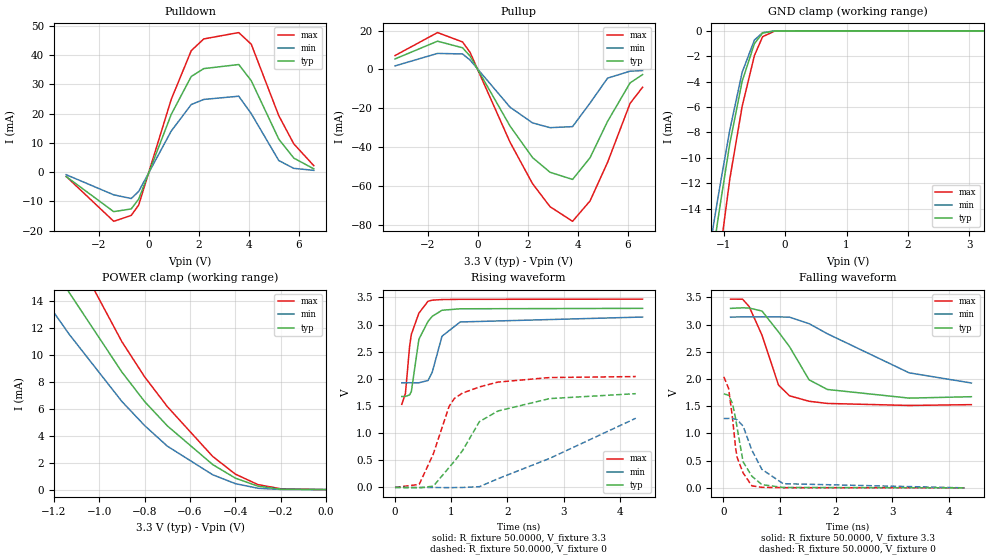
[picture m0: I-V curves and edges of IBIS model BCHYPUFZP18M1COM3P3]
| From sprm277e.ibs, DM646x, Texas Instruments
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|   Model Cell HYPUFZP18_M1_COM_3P3
[Model]   BCHYPUFZP18M1COM3P3
Model_type   I/O
Polarity   Non-Inverting
Enable   Active-Low
Vinl =  0.8V
Vinh =  2V
Cref =  10.0000pF
Rref =  50.0000
Vref =  1.5V
Vmeas =  1.65
C_comp   1.705749p   1.661847p   1.750916p
[Model Spec]
Vinl   0.8V   0.8V   0.8V
Vinh   2V   2V   2V
[Temperature Range]   25   105   0
[Voltage Range]   3.3   3.14   3.47
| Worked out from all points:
|   slope of the pulldown table from 0 to 0.495 V, typ, clamps not added: 44 ohm
|   slope of the pullup table from 0 to 0.495 V, typ, clamps not added: 42.8 ohm
|   GND clamp passes 1 mA (typ) near -0.50 V on its own axis
|   POWER clamp passes 1 mA (typ) near -0.41 V on its own axis
|   rising waveform, R_fixture 50.0000, V_fixture 3.3: 20-80 % time 203ps typ, 264ps min, 172ps max; typ from 1.68 V to 3.3 V
|   rising waveform, R_fixture 50.0000, V_fixture 0: 20-80 % time 820ps typ, 1.71ns min, 460ps max; typ from 0 V to 1.73 V
|   falling waveform, R_fixture 50.0000, V_fixture 3.3: 20-80 % time 610ps typ, 1.43ns min, 394ps max; typ from 3.3 V to 1.68 V
|   falling waveform, R_fixture 50.0000, V_fixture 0: 20-80 % time 219ps typ, 379ps min, 176ps max; typ from 1.73 V to 0 V
[POWER_clamp]
|   voltage   I(typ)   I(min)   I(max)
-3.3V     86.16mA    67.13mA    105mA
-1.4V     22.19mA    18.14mA    27.42mA
-1.267V   18.3mA     14.77mA    22.79mA
-1.133V   14.65mA    11.55mA    18.33mA
-900mV    8.728mA    6.543mA    10.98mA
-800mV    6.541mA    4.758mA    8.376mA
-700mV    4.737mA    3.229mA    6.166mA
-500mV    1.861mA    1.103mA    2.463mA
-400mV    851.5uA    442.9uA    1.148mA
-300mV    252.3uA    97.7uA     368uA
-200mV    33uA       10.48uA    62.12uA
0V        112.2nA    122.7nA    532.8nA
[Pulldown]
|   voltage   I(typ)   I(min)   I(max)
-3.3V     -1.512mA   -878.8uA   -1.478mA
-1.4V     -13.5mA    -7.754mA   -16.8mA
-700mV    -12.57mA   -9.009mA   -14.79mA
-400mV    -9.189mA   -6.568mA   -11.22mA
900mV     19.74mA    14.05mA    24.87mA
1.7V      32.7mA     23.11mA    41.52mA
2.2V      35.39mA    24.85mA    45.53mA
3.6V      36.79mA    25.96mA    47.71mA
4.1V      31.25mA    19.99mA    43.72mA
5.2V      11.29mA    3.971mA    19.31mA
5.8V      4.815mA    1.297mA    9.686mA
6.6V      1.129mA    609.9uA    2.214mA
[Pullup]
|   voltage   I(typ)   I(min)   I(max)
-3.3V     5.393mA    1.813mA    7.121mA
-1.6V     14.52mA    8.235mA    18.96mA
-600mV    11.14mA    7.956mA    14.14mA
-300mV    6.902mA    4.842mA    8.81mA
1.3V      -29.12mA   -19.41mA   -37.44mA
2.2V      -45.34mA   -27.51mA   -58.77mA
2.9V      -52.9mA    -29.96mA   -70.6mA
3.8V      -56.59mA   -29.42mA   -78.12mA
4.5V      -45.43mA   -17.3mA    -67.63mA
5.2V      -26.73mA   -4.487mA   -47.82mA
6.1V      -6.937mA   -896.3uA   -17.48mA
6.6V      -2.651mA   -585.7uA   -9.175mA
[GND_clamp]
|   voltage   I(typ)   I(min)   I(max)
-3.3V     -101.7mA   -80.77mA   -121.3mA
-1.3V     -22.1mA    -19.35mA   -26.96mA
-1.233V   -19.67mA   -17.32mA   -24.28mA
-1.167V   -17.33mA   -15.32mA   -21.64mA
-1.1V     -15.07mA   -13.34mA   -19.06mA
-1.033V   -12.95mA   -11.44mA   -16.53mA
-900mV    -8.853mA   -7.798mA   -11.65mA
-700mV    -3.98mA    -3.268mA   -5.958mA
-500mV    -1.007mA   -725.4uA   -1.943mA
-366.7mV  -173.9uA   -140.4uA   -462.9uA
-166.7mV  -4.98uA    -4.712uA   -10.06uA
3.233V    80.05nA    1.448uA    400.3nA
[Ramp]
| variable   typ   min   max
dV/dt_f  1.0005618/0.63156266n 0.77990537/1.5735667n  1.1806806/0.40053226n
dV/dt_r  1.0442891/0.82808661n 0.78269048/2.2305487n  1.2328499/0.46262539n
R_load = 50
[Rising Waveform]
R_fixture = 50.0000
V_fixture = 3.3
V_fixture_min = 3.14
V_fixture_max = 3.47
|   time   V(typ)   V(min)   V(max)
128.6ps   1.676V     1.928V     1.53V
193.2ps   1.677V     1.929V     1.731V
267.6ps   1.705V     1.929V     2.602V
298.6ps   1.769V     1.929V     2.822V
432ps     2.73V      1.928V     3.212V
594.2ps   3.059V     1.97V      3.431V
670.3ps   3.154V     2.128V     3.451V
842.3ps   3.265V     2.787V     3.462V
1.165ns   3.292V     3.049V     3.466V
4.402ns   3.3V       3.14V      3.47V
[Rising Waveform]
R_fixture = 50.0000
V_fixture = 0
V_fixture_min = 0
V_fixture_max = 0
|   time   V(typ)   V(min)   V(max)
8.119ps   38.02uV    21.16uV    59.39uV
437.5ps   -8.037mV   14.52uV    55.8mV
688.9ps   23.7mV     -1.579mV   618.3mV
968.6ps   368.3mV    -4.199mV   1.495V
1.065ns   485.1mV    -2.439mV   1.643V
1.206ns   677mV      -998.9uV   1.738V
1.506ns   1.212V     13.77mV    1.852V
1.834ns   1.408V     159.9mV    1.941V
2.752ns   1.637V     534.7mV    2.025V
4.282ns   1.728V     1.275V     2.043V
[Falling Waveform]
R_fixture = 50.0000
V_fixture = 3.3
V_fixture_min = 3.14
V_fixture_max = 3.47
|   time   V(typ)   V(min)   V(max)
128.6ps   3.3V       3.14V      3.47V
342.4ps   3.31V      3.143V     3.468V
456.6ps   3.306V     3.144V     3.336V
686.5ps   3.251V     3.145V     2.806V
979.1ps   2.866V     3.143V     1.89V
1.174ns   2.597V     3.139V     1.693V
1.522ns   1.986V     3.019V     1.592V
1.847ns   1.809V     2.833V     1.552V
3.298ns   1.65V      2.115V     1.515V
4.402ns   1.676V     1.928V     1.53V
[Falling Waveform]
R_fixture = 50.0000
V_fixture = 0
V_fixture_min = 0
V_fixture_max = 0
|   time   V(typ)   V(min)   V(max)
8.119ps   1.728V     1.275V     2.043V
92.87ps   1.703V     1.276V     1.831V
162.9ps   1.551V     1.273V     1.282V
218.3ps   1.269V     1.261V     726.7mV
245.6ps   1.099V     1.251V     557.1mV
350.4ps   480.2mV    1.137V     276mV
506.3ps   214.7mV    692.4mV    37.13mV
684.9ps   58.87mV    339.7mV    10.16mV
1.062ns   7.154mV    76.61mV    3.796mV
4.282ns   38.02uV    21.16uV    59.39uV
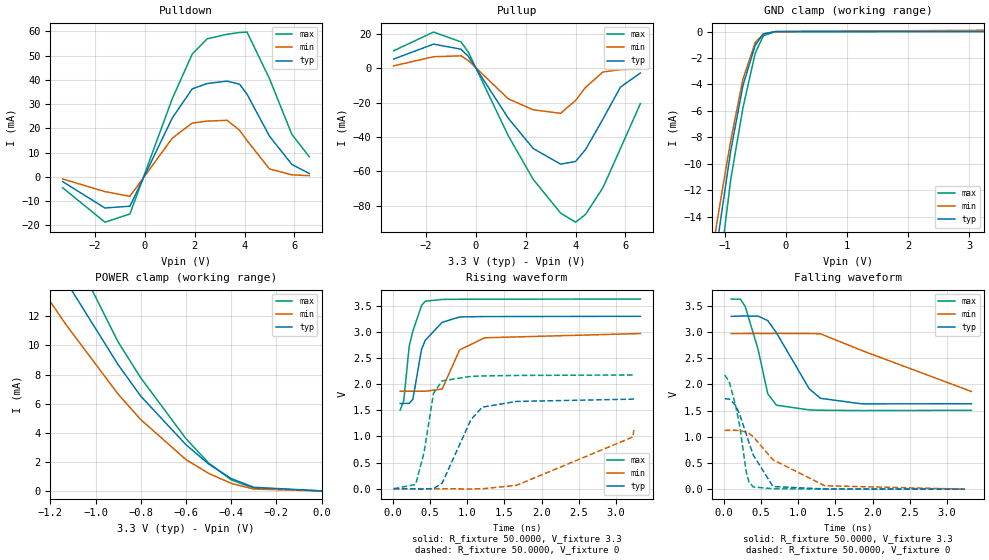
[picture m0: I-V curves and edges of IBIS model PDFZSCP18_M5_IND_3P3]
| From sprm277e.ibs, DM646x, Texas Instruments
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|   Model Cell PDFZSCP18_M5_IND_3P3
[Model]   PDFZSCP18_M5_IND_3P3
Model_type   I/O
Polarity   Non-Inverting
Enable   Active-Low
Vinl =  0.8V
Vinh =  2V
Cref =  10.0000pF
Rref =  50.0000
Vref =  1.5V
Vmeas =  1.65
C_comp   1.471252p   1.436302p   1.510805p
[Model Spec]
Vinl   0.8V   0.8V   0.8V
Vinh   2V   2V   2V
[Temperature Range]   25   125   -40
[Voltage Range]   3.3   2.97   3.63
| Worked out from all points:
|   slope of the pulldown table from 0 to 0.495 V, typ, clamps not added: 42.9 ohm
|   slope of the pullup table from 0 to 0.495 V, typ, clamps not added: 42.8 ohm
|   GND clamp passes 1 mA (typ) near -0.50 V on its own axis
|   POWER clamp passes 1 mA (typ) near -0.41 V on its own axis
|   rising waveform, R_fixture 50.0000, V_fixture 3.3: 20-80 % time 193ps typ, 260ps min, 145ps max; typ from 1.63 V to 3.3 V
|   rising waveform, R_fixture 50.0000, V_fixture 0: 20-80 % time 310ps typ, 971ps min, 152ps max; typ from 0 V to 1.73 V
|   falling waveform, R_fixture 50.0000, V_fixture 3.3: 20-80 % time 411ps typ, 1.11ns min, 215ps max; typ from 3.3 V to 1.63 V
|   falling waveform, R_fixture 50.0000, V_fixture 0: 20-80 % time 276ps typ, 625ps min, 153ps max; typ from 1.73 V to 0 V
[POWER_clamp]
|   voltage   I(typ)   I(min)   I(max)
-3.3V     84.55mA    63.95mA    102mA
-1.4V     21.83mA    17.74mA    26.38mA
-1.367V   20.87mA    16.94mA    25.25mA
-1.233V   17.12mA    13.77mA    20.77mA
-1.133V   14.48mA    11.49mA    17.46mA
-900mV    8.679mA    6.655mA    10.24mA
-800mV    6.517mA    4.906mA    7.776mA
-600mV    3.176mA    2.153mA    3.593mA
-500mV    1.855mA    1.21mA     1.925mA
-400mV    849.2uA    521.5uA    759.7uA
-300mV    251.8uA    131.3uA    194uA
0V        112.2nA    168.6nA    411nA
[Pulldown]
|   voltage   I(typ)   I(min)   I(max)
-3.3V     -1.945mA   -836.9uA   -4.474mA
-1.6V     -12.83mA   -6.075mA   -18.69mA
-600mV    -12.09mA   -8.013mA   -15.3mA
1.1V      24.29mA    15.95mA    32.25mA
1.9V      36.3mA     22.19mA    50.64mA
2.5V      38.52mA    23.01mA    56.95mA
3.3V      39.52mA    23.34mA    58.83mA
3.8V      38.23mA    19.26mA    59.54mA
4.1V      34.11mA    14.97mA    59.73mA
5V        16.81mA    3.301mA    40.55mA
5.9V      5.118mA    845.8uA    17.51mA
6.6V      1.393mA    503uA      8.266mA
[Pullup]
|   voltage   I(typ)   I(min)   I(max)
-3.3V     5.393mA    1.41mA     10.24mA
-1.7V     14.1mA     6.75mA     21.11mA
-600mV    11.14mA    7.267mA    15.41mA
-300mV    6.902mA    4.509mA    9.346mA
1.3V      -29.12mA   -17.81mA   -39.31mA
2.3V      -46.77mA   -24.19mA   -64.74mA
3.4V      -55.86mA   -26.24mA   -84.42mA
4V        -54.31mA   -18.73mA   -89.71mA
4.4V      -47.36mA   -11.08mA   -85.21mA
5.1V      -29.53mA   -2.142mA   -69.52mA
5.8V      -10.97mA   -782.4uA   -46.79mA
6.6V      -2.731mA   -431uA     -20.64mA
[GND_clamp]
|   voltage   I(typ)   I(min)   I(max)
-3.3V     -103.4mA   -79.15mA   -123mA
-1.3V     -22.51mA   -19.59mA   -27.05mA
-1.233V   -20.05mA   -17.62mA   -24.29mA
-1.167V   -17.67mA   -15.67mA   -21.55mA
-1.1V     -15.38mA   -13.74mA   -18.83mA
-1.033V   -13.21mA   -11.87mA   -16.19mA
-900mV    -9.031mA   -8.249mA   -11.2mA
-700mV    -4.077mA   -3.596mA   -5.76mA
-500mV    -1.039mA   -825.4uA   -1.643mA
-366.7mV  -183.5uA   -179.3uA   -315.5uA
-166.7mV  -5.408uA   -6.242uA   -8.231uA
3.233V    80.42nA    93.09uA    331.9nA
[Ramp]
| variable   typ   min   max
dV/dt_f  1.0170778/0.41721552n 0.71158306/1.194652n   1.281715/0.21525542n
dV/dt_r  1.0439964/0.31196719n 0.69305434/1.0171896n  1.3149037/0.15351891n
R_load = 50
[Rising Waveform]
R_fixture = 50.0000
V_fixture = 3.3
V_fixture_min = 2.97
V_fixture_max = 3.63
|   time   V(typ)   V(min)   V(max)
99.91ps   1.631V     1.865V     1.506V
148.6ps   1.631V     1.866V     1.686V
221.2ps   1.635V     1.866V     2.726V
270.5ps   1.711V     1.866V     3.016V
386.6ps   2.664V     1.866V     3.505V
437.2ps   2.841V     1.866V     3.589V
663.7ps   3.184V     1.908V     3.623V
897.8ps   3.288V     2.656V     3.626V
1.235ns   3.295V     2.889V     3.628V
3.326ns   3.3V       2.97V      3.63V
[Rising Waveform]
R_fixture = 50.0000
V_fixture = 0
V_fixture_min = 0
V_fixture_max = 0
|   time   V(typ)   V(min)   V(max)
12.6ps    42.91uV    19.85uV    85.36uV
308.1ps   -3.269mV   25.72uV    80.66mV
419ps     -8.634mV   27.49uV    683.6mV
548.1ps   1.052mV    -69.78uV   1.828V
664.6ps   108mV      -1.375mV   2.065V
1.051ns   1.324V     -3.847mV   2.151V
1.203ns   1.561V     -1.676mV   2.158V
1.662ns   1.671V     64.27mV    2.168V
3.226ns   1.714V     991mV      2.177V
3.238ns   1.728V     1.123V     2.179V
[Falling Waveform]
R_fixture = 50.0000
V_fixture = 3.3
V_fixture_min = 2.97
V_fixture_max = 3.63
|   time   V(typ)   V(min)   V(max)
99.91ps   3.3V       2.97V      3.63V
223.5ps   3.305V     2.971V     3.628V
288.1ps   3.305V     2.972V     3.49V
460.6ps   3.304V     2.973V     2.671V
590.5ps   3.22V      2.972V     1.824V
707.3ps   2.987V     2.973V     1.603V
1.148ns   1.916V     2.972V     1.513V
1.299ns   1.735V     2.967V     1.507V
1.859ns   1.628V     2.645V     1.501V
3.326ns   1.631V     1.865V     1.506V
[Falling Waveform]
R_fixture = 50.0000
V_fixture = 0
V_fixture_min = 0
V_fixture_max = 0
|   time   V(typ)   V(min)   V(max)
12.6ps    1.728V     1.123V     2.179V
73.06ps   1.72V      1.124V     2.054V
159.9ps   1.602V     1.124V     1.592V
213.2ps   1.428V     1.118V     1.218V
302.3ps   1.052V     1.09V      324.9mV
340ps     881mV      1.063V     131mV
396.9ps   650.3mV    998.7mV    42.45mV
661.5ps   50.11mV    560.6mV    8.178mV
1.358ns   4.083mV    64.71mV    1.919mV
3.238ns   42.91uV    19.85uV    85.36uV
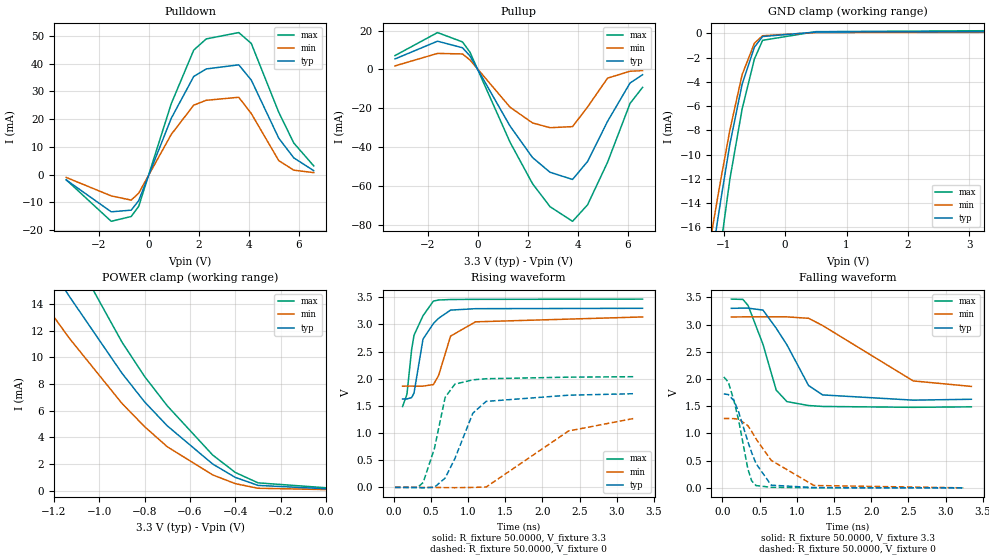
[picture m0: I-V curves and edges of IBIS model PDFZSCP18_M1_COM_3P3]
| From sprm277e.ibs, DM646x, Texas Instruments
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|   Model Cell PDFZSCP18_M1_COM_3P3
[Model]   PDFZSCP18_M1_COM_3P3
Model_type   I/O
Polarity   Non-Inverting
Enable   Active-Low
Vinl =  0.8V
Vinh =  2V
Cref =  10.0000pF
Rref =  50.0000
Vref =  1.5V
Vmeas =  1.65
C_comp   1.471252p   1.43537p   1.5115p
[Model Spec]
Vinl   0.8V   0.8V   0.8V
Vinh   2V   2V   2V
[Temperature Range]   25   105   0
[Voltage Range]   3.3   3.14   3.47
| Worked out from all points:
|   slope of the pulldown table from 0 to 0.495 V, typ, clamps not added: 42.9 ohm
|   slope of the pullup table from 0 to 0.495 V, typ, clamps not added: 42.8 ohm
|   GND clamp passes 1 mA (typ) near -0.48 V on its own axis
|   POWER clamp passes 1 mA (typ) near -0.40 V on its own axis
|   rising waveform, R_fixture 50.0000, V_fixture 3.3: 20-80 % time 195ps typ, 236ps min, 168ps max; typ from 1.63 V to 3.3 V
|   rising waveform, R_fixture 50.0000, V_fixture 0: 20-80 % time 310ps typ, 751ps min, 202ps max; typ from 0 V to 1.73 V
|   falling waveform, R_fixture 50.0000, V_fixture 3.3: 20-80 % time 410ps typ, 890ps min, 269ps max; typ from 3.3 V to 1.63 V
|   falling waveform, R_fixture 50.0000, V_fixture 0: 20-80 % time 274ps typ, 531ps min, 182ps max; typ from 1.73 V to 0 V
[POWER_clamp]
|   voltage   I(typ)   I(min)   I(max)
-3.3V     84.8mA     66.18mA    103.2mA
-1.433V   23.02mA    18.79mA    28.39mA
-1.4V     21.98mA    17.95mA    27.19mA
-1.267V   18.18mA    14.64mA    22.68mA
-1.133V   14.62mA    11.47mA    18.34mA
-900mV    8.822mA    6.554mA    11.16mA
-800mV    6.659mA    4.8mA      8.567mA
-700mV    4.862mA    3.292mA    6.364mA
-500mV    1.994mA    1.178mA    2.67mA
-400mV    987.9uA    519uA      1.358mA
-300mV    390uA      174.5uA    580.2uA
0V        137uA      76.42uA    211.3uA
[Pulldown]
|   voltage   I(typ)   I(min)   I(max)
-3.3V     -1.944mA   -1.033mA   -1.887mA
-1.5V     -13.44mA   -7.697mA   -16.86mA
-700mV    -12.84mA   -9.215mA   -15.12mA
-400mV    -9.371mA   -6.707mA   -11.45mA
900mV     20.28mA    14.47mA    25.55mA
1.8V      35.39mA    25.04mA    44.9mA
2.3V      38.1mA     26.79mA    48.93mA
3.6V      39.58mA    27.88mA    51.22mA
4.1V      34.1mA     22.03mA    47.31mA
5.2V      13.11mA    5.026mA    22.46mA
5.8V      6.024mA    1.586mA    11.39mA
6.6V      1.392mA    699.1uA    3.1mA
[Pullup]
|   voltage   I(typ)   I(min)   I(max)
-3.3V     5.394mA    1.815mA    7.121mA
-1.6V     14.52mA    8.238mA    18.96mA
-600mV    11.14mA    7.958mA    14.14mA
-300mV    6.901mA    4.843mA    8.81mA
1.3V      -29.12mA   -19.42mA   -37.44mA
2.2V      -45.34mA   -27.53mA   -58.77mA
2.9V      -52.9mA    -29.98mA   -70.61mA
3.8V      -56.59mA   -29.42mA   -78.12mA
4.4V      -47.37mA   -19.32mA   -69.66mA
5.2V      -26.71mA   -4.49mA    -47.76mA
6.1V      -6.966mA   -911.1uA   -17.47mA
6.6V      -2.733mA   -594.2uA   -9.226mA
[GND_clamp]
|   voltage   I(typ)   I(min)   I(max)
-3.3V     -103.4mA   -81.9mA    -123.6mA
-1.3V     -22.54mA   -19.65mA   -27.6mA
-1.233V   -20.09mA   -17.6mA    -24.87mA
-1.167V   -17.72mA   -15.58mA   -22.19mA
-1.1V     -15.45mA   -13.58mA   -19.56mA
-1.033V   -13.3mA    -11.66mA   -17mA
-900mV    -9.149mA   -7.993mA   -12.04mA
-700mV    -4.193mA   -3.413mA   -6.239mA
-500mV    -1.139mA   -815.4uA   -2.116mA
-366.7mV  -266.8uA   -203.2uA   -581.3uA
500mV     98.21uA    59.42uA    133.4uA
3.233V    136.8uA    77.9uA     210.2uA
[Ramp]
| variable   typ   min   max
dV/dt_f  1.0171548/0.41633149n 0.79867835/0.93562209n  1.1956771/0.27067381n
dV/dt_r  1.0420768/0.31261212n 0.77892311/0.77262793n  1.2300834/0.20209603n
R_load = 50
[Rising Waveform]
R_fixture = 50.0000
V_fixture = 3.3
V_fixture_min = 3.14
V_fixture_max = 3.47
|   time   V(typ)   V(min)   V(max)
121.6ps   1.627V     1.863V     1.488V
180.4ps   1.628V     1.865V     1.714V
243.6ps   1.653V     1.865V     2.541V
275.3ps   1.736V     1.864V     2.801V
396.1ps   2.729V     1.864V     3.16V
535.9ps   3.017V     1.893V     3.43V
605.6ps   3.113V     2.059V     3.45V
766.7ps   3.264V     2.785V     3.459V
1.102ns   3.29V      3.048V     3.462V
3.347ns   3.297V     3.138V     3.466V
[Rising Waveform]
R_fixture = 50.0000
V_fixture = 0
V_fixture_min = 0
V_fixture_max = 0
|   time   V(typ)   V(min)   V(max)
19.87ps   42.97uV    20.31uV    71.13uV
325.2ps   -5.732mV   29.69uV    502.9uV
398ps     -9.285mV   14.89uV    89.22mV
550.3ps   1.997mV    -1.598mV   718.6mV
693.6ps   171.7mV    -5.081mV   1.657V
824.3ps   528mV      -6.126mV   1.9V
1.066ns   1.366V     -1.274mV   1.98V
1.245ns   1.583V     6.047mV    2V
2.352ns   1.697V     1.038V     2.029V
3.246ns   1.725V     1.273V     2.038V
[Falling Waveform]
R_fixture = 50.0000
V_fixture = 3.3
V_fixture_min = 3.14
V_fixture_max = 3.47
|   time   V(typ)   V(min)   V(max)
121.6ps   3.297V     3.138V     3.466V
276.5ps   3.301V     3.14V      3.461V
346.7ps   3.3V       3.141V     3.348V
546.3ps   3.265V     3.141V     2.637V
724.4ps   2.931V     3.14V      1.795V
867.8ps   2.627V     3.14V      1.584V
1.159ns   1.88V      3.114V     1.512V
1.347ns   1.707V     2.982V     1.495V
2.565ns   1.611V     1.964V     1.479V
3.347ns   1.627V     1.863V     1.488V
[Falling Waveform]
R_fixture = 50.0000
V_fixture = 0
V_fixture_min = 0
V_fixture_max = 0
|   time   V(typ)   V(min)   V(max)
19.87ps   1.725V     1.273V     2.038V
80.93ps   1.713V     1.274V     1.942V
159.2ps   1.595V     1.271V     1.588V
219.9ps   1.391V     1.259V     1.236V
344ps     848.6mV    1.142V     343.4mV
394.2ps   646.4mV    1.036V     129.2mV
453.7ps   444.5mV    898.7mV    42.01mV
657.2ps   49.34mV    504.5mV    10.1mV
1.232ns   4.74mV     43.59mV    2.692mV
3.246ns   42.97uV    20.31uV    71.13uV
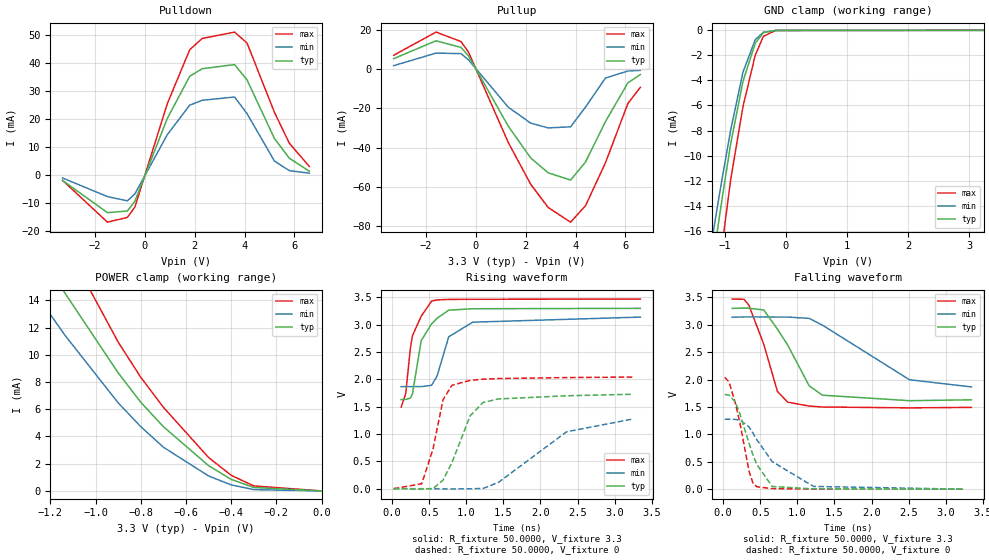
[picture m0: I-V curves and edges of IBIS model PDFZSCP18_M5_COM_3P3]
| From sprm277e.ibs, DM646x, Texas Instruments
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|   Model Cell PDFZSCP18_M5_COM_3P3
[Model]   PDFZSCP18_M5_COM_3P3
Model_type   I/O
Polarity   Non-Inverting
Enable   Active-Low
Vinl =  0.8V
Vinh =  2V
Cref =  10.0000pF
Rref =  50.0000
Vref =  1.5V
Vmeas =  1.65
C_comp   1.471252p   1.43537p   1.5115p
[Model Spec]
Vinl   0.8V   0.8V   0.8V
Vinh   2V   2V   2V
[Temperature Range]   25   105   0
[Voltage Range]   3.3   3.14   3.47
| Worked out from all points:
|   slope of the pulldown table from 0 to 0.495 V, typ, clamps not added: 42.9 ohm
|   slope of the pullup table from 0 to 0.495 V, typ, clamps not added: 42.8 ohm
|   GND clamp passes 1 mA (typ) near -0.50 V on its own axis
|   POWER clamp passes 1 mA (typ) near -0.41 V on its own axis
|   rising waveform, R_fixture 50.0000, V_fixture 3.3: 20-80 % time 193ps typ, 237ps min, 166ps max; typ from 1.63 V to 3.3 V
|   rising waveform, R_fixture 50.0000, V_fixture 0: 20-80 % time 310ps typ, 750ps min, 200ps max; typ from 0 V to 1.73 V
|   falling waveform, R_fixture 50.0000, V_fixture 3.3: 20-80 % time 411ps typ, 889ps min, 269ps max; typ from 3.3 V to 1.63 V
|   falling waveform, R_fixture 50.0000, V_fixture 0: 20-80 % time 276ps typ, 534ps min, 182ps max; typ from 1.73 V to 0 V
[POWER_clamp]
|   voltage   I(typ)   I(min)   I(max)
-3.3V     84.55mA    66.04mA    102.9mA
-1.433V   22.86mA    18.71mA    28.16mA
-1.4V     21.83mA    17.86mA    26.96mA
-1.267V   18.03mA    14.55mA    22.45mA
-1.133V   14.48mA    11.39mA    18.11mA
-900mV    8.679mA    6.475mA    10.94mA
-800mV    6.517mA    4.721mA    8.348mA
-700mV    4.721mA    3.214mA    6.146mA
-500mV    1.855mA    1.1mA      2.456mA
-400mV    849.2uA    441.9uA    1.144mA
-300mV    251.8uA    97.54uA    367.3uA
0V        112.2nA    125nA      532.8nA
[Pulldown]
|   voltage   I(typ)   I(min)   I(max)
-3.3V     -1.944mA   -1.033mA   -1.887mA
-1.5V     -13.44mA   -7.697mA   -16.86mA
-700mV    -12.84mA   -9.215mA   -15.12mA
-400mV    -9.372mA   -6.707mA   -11.45mA
900mV     20.28mA    14.47mA    25.55mA
1.8V      35.39mA    25.05mA    44.9mA
2.3V      38.1mA     26.79mA    48.93mA
3.6V      39.58mA    27.98mA    51.22mA
4.1V      34.1mA     22.03mA    47.31mA
5.2V      13.11mA    5.026mA    22.46mA
5.8V      6.024mA    1.586mA    11.39mA
6.6V      1.392mA    699.1uA    3.1mA
[Pullup]
|   voltage   I(typ)   I(min)   I(max)
-3.3V     5.394mA    1.815mA    7.121mA
-1.6V     14.52mA    8.237mA    18.96mA
-600mV    11.14mA    7.958mA    14.14mA
-300mV    6.902mA    4.843mA    8.81mA
1.3V      -29.12mA   -19.42mA   -37.44mA
2.2V      -45.34mA   -27.53mA   -58.77mA
2.9V      -52.9mA    -29.98mA   -70.61mA
3.8V      -56.59mA   -29.42mA   -78.12mA
4.4V      -47.37mA   -19.32mA   -69.66mA
5.2V      -26.71mA   -4.49mA    -47.76mA
6.1V      -6.966mA   -911.1uA   -17.47mA
6.6V      -2.733mA   -594.2uA   -9.226mA
[GND_clamp]
|   voltage   I(typ)   I(min)   I(max)
-3.3V     -103.4mA   -81.9mA    -123.6mA
-1.3V     -22.51mA   -19.64mA   -27.57mA
-1.233V   -20.05mA   -17.59mA   -24.83mA
-1.167V   -17.67mA   -15.56mA   -22.12mA
-1.1V     -15.38mA   -13.56mA   -19.46mA
-1.033V   -13.2mA    -11.63mA   -16.88mA
-900mV    -9.031mA   -7.941mA   -11.89mA
-700mV    -4.077mA   -3.341mA   -6.097mA
-500mV    -1.039mA   -749.9uA   -1.992mA
-366.7mV  -183.5uA   -148.4uA   -478uA
-166.7mV  -5.408uA   -5.001uA   -10.98uA
3.233V    80.42nA    1.448uA    402.2nA
[Ramp]
| variable   typ   min   max
dV/dt_f  1.0170369/0.4173123n  0.7987099/0.93716767n  1.1953768/0.27127991n
dV/dt_r  1.0440133/0.3117817n 0.78035107/0.770697n   1.2326758/0.20155307n
R_load = 50
[Rising Waveform]
R_fixture = 50.0000
V_fixture = 3.3
V_fixture_min = 3.14
V_fixture_max = 3.47
|   time   V(typ)   V(min)   V(max)
121.5ps   1.631V     1.866V     1.493V
182.6ps   1.632V     1.868V     1.74V
245.3ps   1.659V     1.867V     2.569V
273.7ps   1.734V     1.867V     2.8V
391.1ps   2.709V     1.867V     3.155V
531.4ps   3.016V     1.892V     3.433V
605.6ps   3.119V     2.062V     3.455V
762.4ps   3.267V     2.779V     3.463V
1.086ns   3.293V     3.047V     3.466V
3.347ns   3.3V       3.14V      3.47V
[Rising Waveform]
R_fixture = 50.0000
V_fixture = 0
V_fixture_min = 0
V_fixture_max = 0
|   time   V(typ)   V(min)   V(max)
19.94ps   42.91uV    20.24uV    70.97uV
398ps     -9.338mV   14.86uV    89.38mV
550.3ps   1.943mV    -1.601mV   722.7mV
686.3ps   156.7mV    -4.606mV   1.63V
806.4ps   477.4mV    -6.594mV   1.892V
1.052ns   1.335V     -1.54mV    1.982V
1.225ns   1.577V     3.667mV    2.003V
1.432ns   1.642V     114.1mV    2.015V
2.352ns   1.7V       1.041V     2.033V
3.246ns   1.728V     1.275V     2.043V
[Falling Waveform]
R_fixture = 50.0000
V_fixture = 3.3
V_fixture_min = 3.14
V_fixture_max = 3.47
|   time   V(typ)   V(min)   V(max)
121.5ps   3.3V       3.14V      3.47V
279.8ps   3.305V     3.143V     3.466V
346.1ps   3.303V     3.143V     3.358V
547ps     3.27V      3.143V     2.644V
730.5ps   2.923V     3.142V     1.785V
869.5ps   2.63V      3.142V     1.588V
1.16ns    1.885V     3.117V     1.517V
1.338ns   1.715V     2.994V     1.5V
2.511ns   1.615V     1.998V     1.484V
3.347ns   1.631V     1.866V     1.493V
[Falling Waveform]
R_fixture = 50.0000
V_fixture = 0
V_fixture_min = 0
V_fixture_max = 0
|   time   V(typ)   V(min)   V(max)
19.94ps   1.728V     1.275V     2.043V
77.76ps   1.718V     1.277V     1.957V
161.6ps   1.592V     1.274V     1.582V
225.9ps   1.373V     1.26V      1.205V
348.2ps   836.9mV    1.137V     327.8mV
398.7ps   635.5mV    1.029V     120.8mV
451.5ps   455.1mV    907.1mV    44.77mV
660.4ps   48.55mV    503mV      10.13mV
1.217ns   4.931mV    50.12mV    2.794mV
3.246ns   42.91uV    20.24uV    70.97uV
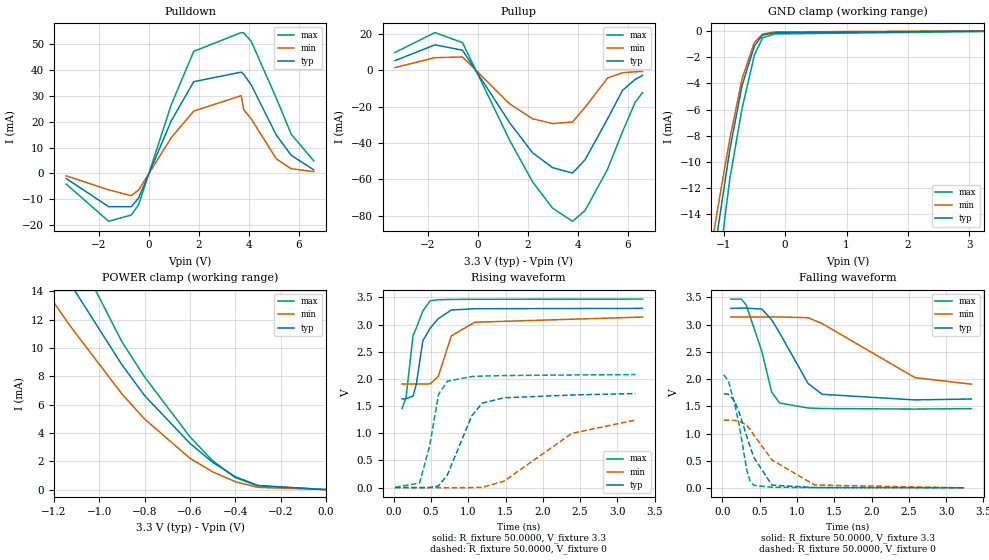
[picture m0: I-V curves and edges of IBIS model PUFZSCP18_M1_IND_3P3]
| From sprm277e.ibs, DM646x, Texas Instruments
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|   Model Cell PUFZSCP18_M1_IND_3P3
[Model]   PUFZSCP18_M1_IND_3P3
Model_type   I/O
Polarity   Non-Inverting
Enable   Active-Low
Vinl =  0.8V
Vinh =  2V
Cref =  10.0000pF
Rref =  50.0000
Vref =  1.5V
Vmeas =  1.65
C_comp   1.716149p   1.667102p   1.755986p
[Model Spec]
Vinl   0.8V   0.8V   0.8V
Vinh   2V   2V   2V
[Temperature Range]   25   125   -40
[Voltage Range]   3.3   3.14   3.47
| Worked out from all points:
|   slope of the pulldown table from 0 to 0.495 V, typ, clamps not added: 42.9 ohm
|   slope of the pullup table from 0 to 0.495 V, typ, clamps not added: 42.8 ohm
|   GND clamp passes 1 mA (typ) near -0.48 V on its own axis
|   POWER clamp passes 1 mA (typ) near -0.41 V on its own axis
|   rising waveform, R_fixture 50.0000, V_fixture 3.3: 20-80 % time 193ps typ, 243ps min, 155ps max; typ from 1.64 V to 3.3 V
|   rising waveform, R_fixture 50.0000, V_fixture 0: 20-80 % time 310ps typ, 768ps min, 169ps max; typ from 0.003 V to 1.73 V
|   falling waveform, R_fixture 50.0000, V_fixture 3.3: 20-80 % time 412ps typ, 910ps min, 240ps max; typ from 3.3 V to 1.64 V
|   falling waveform, R_fixture 50.0000, V_fixture 0: 20-80 % time 276ps typ, 554ps min, 170ps max; typ from 1.73 V to 0.003 V
[POWER_clamp]
|   voltage   I(typ)   I(min)   I(max)
-3.3V     86.16mA    64.93mA    104.3mA
-1.4V     22.2mA     18mA       26.83mA
-1.367V   21.21mA    17.19mA    25.67mA
-1.233V   17.38mA    13.98mA    21.08mA
-1.133V   14.68mA    11.66mA    17.73mA
-900mV    8.815mA    6.753mA    10.44mA
-800mV    6.637mA    4.985mA    7.954mA
-600mV    3.264mA    2.209mA    3.724mA
-500mV    1.928mA    1.255mA    2.032mA
-400mV    906.7uA    556.4uA    845.1uA
-300mV    294.4uA    156.7uA    257.3uA
0V        111.8nA    201.8nA    235.2nA
[Pulldown]
|   voltage   I(typ)   I(min)   I(max)
-3.3V     -1.944mA   -917.2uA   -4.091mA
-1.6V     -12.83mA   -6.342mA   -18.45mA
-700mV    -12.84mA   -8.548mA   -16.04mA
-400mV    -9.372mA   -6.338mA   -12.02mA
900mV     20.28mA    13.8mA     26.48mA
1.8V      35.39mA    24.06mA    47.09mA
3.7V      39.1mA     30mA       54.34mA
3.8V      38.22mA    24.56mA    54.24mA
4.1V      34.11mA    21.05mA    50.92mA
5.1V      14.83mA    5.661mA    29.08mA
5.7V      6.992mA    1.816mA    15.11mA
6.6V      1.393mA    706.9uA    4.852mA
[Pullup]
|   voltage   I(typ)   I(min)   I(max)
-3.3V     5.394mA    1.595mA    9.842mA
-1.7V     14.1mA     7.032mA    20.86mA
-600mV    11.14mA    7.393mA    15.31mA
1.3V      -29.12mA   -18.59mA   -38.9mA
2.2V      -45.34mA   -26.61mA   -61.37mA
3V        -53.59mA   -29.31mA   -75.93mA
3.8V      -56.58mA   -28.42mA   -83.16mA
4.3V      -49.27mA   -20.37mA   -77.23mA
5.2V      -26.7mA    -4.187mA   -54.48mA
5.8V      -10.97mA   -1.281mA   -33.72mA
6.3V      -5.031mA   -754.9uA   -17.64mA
6.6V      -2.731mA   -599.9uA   -12.21mA
[GND_clamp]
|   voltage   I(typ)   I(min)   I(max)
-3.3V     -101.9mA   -78.14mA   -121mA
-1.3V     -22.32mA   -19.4mA    -26.86mA
-1.233V   -19.91mA   -17.46mA   -24.16mA
-1.167V   -17.57mA   -15.54mA   -21.48mA
-1.1V     -15.32mA   -13.64mA   -18.81mA
-1.033V   -13.18mA   -11.79mA   -16.21mA
-900mV    -9.06mA    -8.22mA    -11.28mA
-700mV    -4.151mA   -3.62mA    -5.895mA
-500mV    -1.148mA   -873.2uA   -1.831mA
-366.7mV  -309.9uA   -238.5uA   -526.3uA
-166.7mV  -140.6uA   -73.42uA   -228.8uA
3.233V    -8.734uA   10uA       -45.21uA
[Ramp]
| variable   typ   min   max
dV/dt_f   1.014704/0.41867304n 0.77453361/0.95986265n  1.2156843/0.24085632n
dV/dt_r   1.043351/0.31142646n 0.75916638/0.78899652n  1.2523634/0.16920069n
R_load = 50
[Rising Waveform]
R_fixture = 50.0000
V_fixture = 3.3
V_fixture_min = 3.14
V_fixture_max = 3.47
|   time   V(typ)   V(min)   V(max)
112.4ps   1.635V     1.907V     1.458V
165.9ps   1.635V     1.908V     1.658V
259.3ps   1.687V     1.908V     2.794V
303.9ps   1.904V     1.907V     2.94V
390.9ps   2.702V     1.907V     3.252V
489ps     2.936V     1.91V      3.439V
597.2ps   3.108V     2.046V     3.459V
774.3ps   3.27V      2.795V     3.464V
1.089ns   3.293V     3.045V     3.467V
3.338ns   3.3V       3.14V      3.47V
[Rising Waveform]
R_fixture = 50.0000
V_fixture = 0
V_fixture_min = 0
V_fixture_max = 0
|   time   V(typ)   V(min)   V(max)
17.61ps   3.11mV     1.873mV    4.384mV
347.1ps   -4.313mV   1.882mV    85.8mV
479.7ps   740.1uV    1.367mV    749.8mV
602.5ps   32.18mV    179.3uV    1.719V
721.9ps   240.8mV    -3.776mV   1.96V
1.048ns   1.324V     1.415mV    2.045V
1.186ns   1.554V     4.02mV     2.053V
1.477ns   1.653V     117.3mV    2.063V
2.389ns   1.705V     998.5mV    2.074V
3.243ns   1.732V     1.244V     2.081V
[Falling Waveform]
R_fixture = 50.0000
V_fixture = 3.3
V_fixture_min = 3.14
V_fixture_max = 3.47
|   time   V(typ)   V(min)   V(max)
112.4ps   3.3V       3.14V      3.47V
253.7ps   3.305V     3.142V     3.47V
318.7ps   3.304V     3.143V     3.36V
529.6ps   3.287V     3.143V     2.5V
659.7ps   3.09V      3.143V     1.762V
765.8ps   2.85V      3.142V     1.562V
1.148ns   1.92V      3.128V     1.469V
1.337ns   1.721V     3.02V      1.459V
2.582ns   1.618V     2.027V     1.45V
3.338ns   1.635V     1.907V     1.458V
[Falling Waveform]
R_fixture = 50.0000
V_fixture = 0
V_fixture_min = 0
V_fixture_max = 0
|   time   V(typ)   V(min)   V(max)
17.61ps   1.732V     1.244V     2.081V
79.62ps   1.721V     1.245V     1.964V
160.3ps   1.602V     1.242V     1.562V
224.4ps   1.387V     1.229V     1.155V
325.6ps   946.5mV    1.152V     329.1mV
370.3ps   756.9mV    1.079V     125.9mV
421.2ps   560.9mV    971.7mV    48.38mV
663.7ps   51.55mV    514.5mV    13.12mV
1.237ns   8.047mV    54.35mV    6.814mV
3.243ns   3.11mV     1.873mV    4.384mV
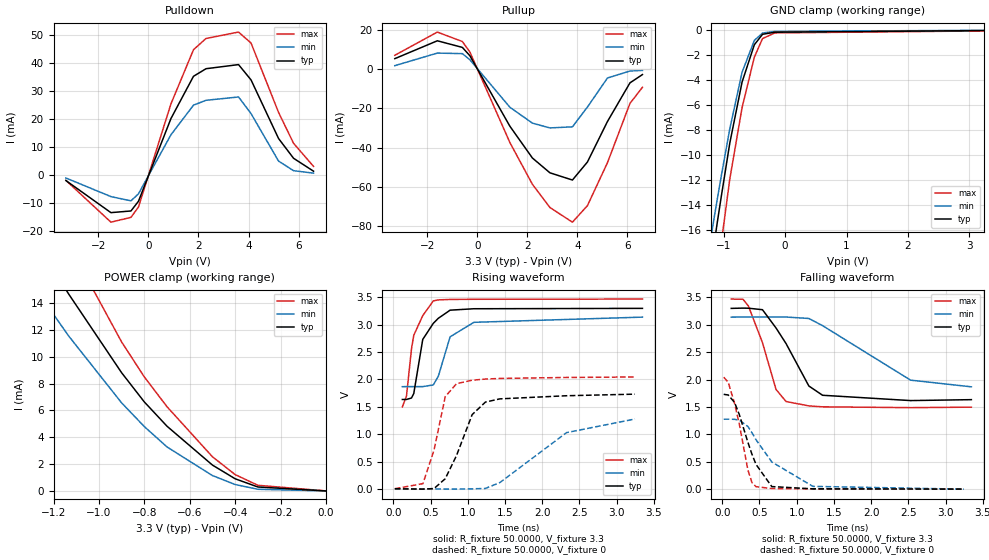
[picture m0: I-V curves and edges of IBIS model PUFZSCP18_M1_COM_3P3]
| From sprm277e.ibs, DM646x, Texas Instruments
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|   Model Cell PUFZSCP18_M1_COM_3P3
[Model]   PUFZSCP18_M1_COM_3P3
Model_type   I/O
Polarity   Non-Inverting
Enable   Active-Low
Vinl =  0.8V
Vinh =  2V
Cref =  10.0000pF
Rref =  50.0000
Vref =  1.5V
Vmeas =  1.65
C_comp   1.716149p   1.667802p   1.756925p
[Model Spec]
Vinl   0.8V   0.8V   0.8V
Vinh   2V   2V   2V
[Temperature Range]   25   105   0
[Voltage Range]   3.3   3.14   3.47
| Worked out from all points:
|   slope of the pulldown table from 0 to 0.495 V, typ, clamps not added: 42.9 ohm
|   slope of the pullup table from 0 to 0.495 V, typ, clamps not added: 42.8 ohm
|   GND clamp passes 1 mA (typ) near -0.48 V on its own axis
|   POWER clamp passes 1 mA (typ) near -0.41 V on its own axis
|   rising waveform, R_fixture 50.0000, V_fixture 3.3: 20-80 % time 193ps typ, 236ps min, 167ps max; typ from 1.64 V to 3.3 V
|   rising waveform, R_fixture 50.0000, V_fixture 0: 20-80 % time 309ps typ, 749ps min, 200ps max; typ from 0.003 V to 1.73 V
|   falling waveform, R_fixture 50.0000, V_fixture 3.3: 20-80 % time 412ps typ, 892ps min, 271ps max; typ from 3.3 V to 1.64 V
|   falling waveform, R_fixture 50.0000, V_fixture 0: 20-80 % time 275ps typ, 533ps min, 182ps max; typ from 1.73 V to 0.003 V
[POWER_clamp]
|   voltage   I(typ)   I(min)   I(max)
-3.3V     86.16mA    67.13mA    105mA
-1.433V   23.25mA    19mA       28.67mA
-1.4V     22.2mA     18.14mA    27.43mA
-1.267V   18.31mA    14.78mA    22.81mA
-1.133V   14.68mA    11.55mA    18.37mA
-900mV    8.815mA    6.568mA    11.11mA
-800mV    6.637mA    4.798mA    8.501mA
-700mV    4.825mA    3.279mA    6.279mA
-500mV    1.928mA    1.146mA    2.548mA
-400mV    906.7uA    477.8uA    1.218mA
-300mV    294.4uA    124uA      421.6uA
0V        111.8nA    122.7nA    532.3nA
[Pulldown]
|   voltage   I(typ)   I(min)   I(max)
-3.3V     -1.944mA   -1.033mA   -1.887mA
-1.5V     -13.44mA   -7.698mA   -16.86mA
-700mV    -12.84mA   -9.216mA   -15.12mA
-400mV    -9.372mA   -6.707mA   -11.45mA
900mV     20.28mA    14.47mA    25.55mA
1.8V      35.39mA    25.05mA    44.9mA
2.3V      38.1mA     26.79mA    48.93mA
3.6V      39.58mA    27.98mA    51.22mA
4.1V      34.1mA     22.03mA    47.31mA
5.2V      13.11mA    5.026mA    22.46mA
5.8V      6.025mA    1.586mA    11.39mA
6.6V      1.393mA    699.1uA    3.101mA
[Pullup]
|   voltage   I(typ)   I(min)   I(max)
-3.3V     5.394mA    1.815mA    7.122mA
-1.6V     14.52mA    8.237mA    18.96mA
-600mV    11.14mA    7.958mA    14.14mA
-300mV    6.902mA    4.843mA    8.81mA
1.3V      -29.12mA   -19.42mA   -37.44mA
2.2V      -45.34mA   -27.53mA   -58.77mA
2.9V      -52.9mA    -29.98mA   -70.61mA
3.8V      -56.59mA   -29.42mA   -78.12mA
4.4V      -47.38mA   -19.32mA   -69.67mA
5.2V      -26.71mA   -4.49mA    -47.76mA
6.1V      -6.965mA   -911.1uA   -17.46mA
6.6V      -2.733mA   -594.2uA   -9.225mA
[GND_clamp]
|   voltage   I(typ)   I(min)   I(max)
-3.3V     -101.9mA   -80.85mA   -121.5mA
-1.3V     -22.32mA   -19.45mA   -27.34mA
-1.233V   -19.91mA   -17.43mA   -24.66mA
-1.167V   -17.57mA   -15.43mA   -22.01mA
-1.1V     -15.32mA   -13.46mA   -19.41mA
-1.033V   -13.18mA   -11.55mA   -16.87mA
-900mV    -9.06mA    -7.912mA   -11.95mA
-700mV    -4.151mA   -3.363mA   -6.206mA
-500mV    -1.148mA   -799.9uA   -2.146mA
-366.7mV  -309.9uA   -211.1uA   -653.2uA
-166.7mV  -140.6uA   -75.06uA   -198.8uA
3.233V    -8.732uA   9.395uA    -38.37uA
[Ramp]
| variable   typ   min   max
dV/dt_f  1.0146827/0.41874253n   0.797251/0.93901583n  1.1925558/0.2723151n
dV/dt_r  1.0433594/0.31133722n  0.7802355/0.76960805n  1.2316605/0.20136743n
R_load = 50
[Rising Waveform]
R_fixture = 50.0000
V_fixture = 3.3
V_fixture_min = 3.14
V_fixture_max = 3.47
|   time   V(typ)   V(min)   V(max)
121.4ps   1.635V     1.869V     1.498V
177.2ps   1.635V     1.87V      1.699V
244.2ps   1.662V     1.87V      2.562V
274.9ps   1.744V     1.87V      2.809V
395.3ps   2.732V     1.87V      3.167V
536.8ps   3.026V     1.9V       3.436V
604.8ps   3.119V     2.061V     3.455V
762.6ps   3.267V     2.78V      3.463V
1.082ns   3.293V     3.045V     3.466V
3.347ns   3.3V       3.14V      3.47V
[Rising Waveform]
R_fixture = 50.0000
V_fixture = 0
V_fixture_min = 0
V_fixture_max = 0
|   time   V(typ)   V(min)   V(max)
19.96ps   3.11mV     1.91mV     3.799mV
398ps     -4.509mV   1.905mV    96.7mV
547.5ps   7.513mV    329.9uV    714.1mV
697.7ps   186.8mV    -3.115mV   1.687V
848.8ps   610.1mV    -2.485mV   1.923V
1.059ns   1.358V     1.933mV    1.987V
1.237ns   1.587V     8.297mV    2.008V
1.432ns   1.646V     116.8mV    2.019V
2.327ns   1.703V     1.029V     2.037V
3.246ns   1.732V     1.278V     2.046V
[Falling Waveform]
R_fixture = 50.0000
V_fixture = 3.3
V_fixture_min = 3.14
V_fixture_max = 3.47
|   time   V(typ)   V(min)   V(max)
121.4ps   3.3V       3.14V      3.47V
279.7ps   3.305V     3.143V     3.466V
352ps     3.303V     3.143V     3.343V
540.6ps   3.276V     3.143V     2.675V
723ps     2.942V     3.142V     1.821V
857.5ps   2.658V     3.142V     1.601V
1.164ns   1.884V     3.116V     1.521V
1.348ns   1.715V     2.985V     1.504V
2.53ns    1.618V     1.991V     1.489V
3.347ns   1.635V     1.869V     1.498V
[Falling Waveform]
R_fixture = 50.0000
V_fixture = 0
V_fixture_min = 0
V_fixture_max = 0
|   time   V(typ)   V(min)   V(max)
19.96ps   1.732V     1.278V     2.046V
81.13ps   1.72V      1.279V     1.951V
165.2ps   1.585V     1.276V     1.569V
229.7ps   1.363V     1.261V     1.188V
345.4ps   855.2mV    1.145V     348.6mV
399.2ps   640.3mV    1.031V     124.5mV
455.2ps   451mV      901.9mV    46.67mV
666.1ps   48.99mV    498.1mV    13.9mV
1.218ns   8.18mV     52.86mV    6.627mV
3.246ns   3.11mV     1.91mV     3.799mV
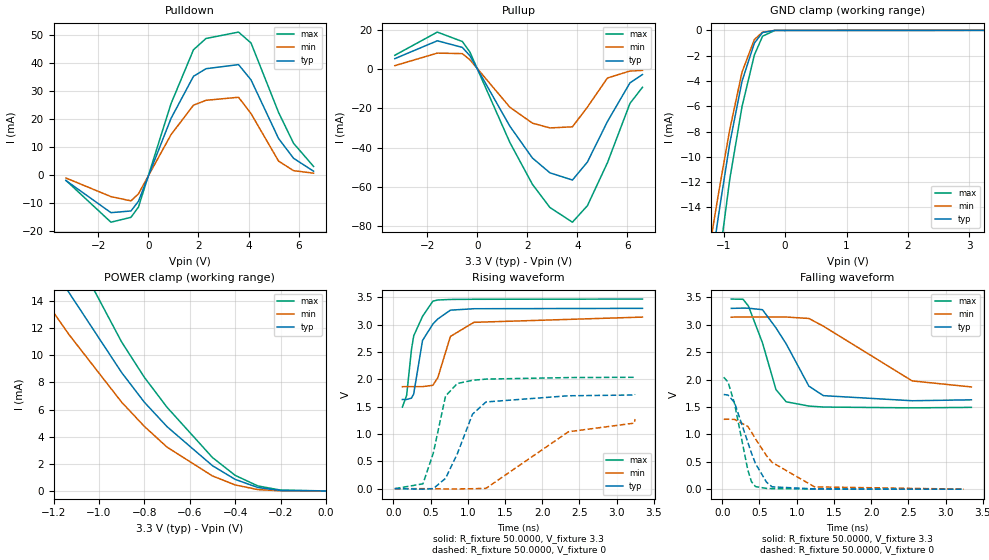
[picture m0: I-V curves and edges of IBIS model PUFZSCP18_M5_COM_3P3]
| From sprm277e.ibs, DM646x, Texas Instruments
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|   Model Cell PUFZSCP18_M5_COM_3P3
[Model]   PUFZSCP18_M5_COM_3P3
Model_type   I/O
Polarity   Non-Inverting
Enable   Active-Low
Vinl =  0.8V
Vinh =  2V
Cref =  10.0000pF
Rref =  50.0000
Vref =  1.5V
Vmeas =  1.65
C_comp   1.716149p   1.667802p   1.756925p
[Model Spec]
Vinl   0.8V   0.8V   0.8V
Vinh   2V   2V   2V
[Temperature Range]   25   105   0
[Voltage Range]   3.3   3.14   3.47
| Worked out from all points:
|   slope of the pulldown table from 0 to 0.495 V, typ, clamps not added: 42.9 ohm
|   slope of the pullup table from 0 to 0.495 V, typ, clamps not added: 42.8 ohm
|   GND clamp passes 1 mA (typ) near -0.50 V on its own axis
|   POWER clamp passes 1 mA (typ) near -0.41 V on its own axis
|   rising waveform, R_fixture 50.0000, V_fixture 3.3: 20-80 % time 195ps typ, 239ps min, 168ps max; typ from 1.63 V to 3.3 V
|   rising waveform, R_fixture 50.0000, V_fixture 0: 20-80 % time 309ps typ, 750ps min, 200ps max; typ from 0 V to 1.73 V
|   falling waveform, R_fixture 50.0000, V_fixture 3.3: 20-80 % time 411ps typ, 892ps min, 271ps max; typ from 3.3 V to 1.63 V
|   falling waveform, R_fixture 50.0000, V_fixture 0: 20-80 % time 275ps typ, 533ps min, 182ps max; typ from 1.73 V to 0 V
[POWER_clamp]
|   voltage   I(typ)   I(min)   I(max)
-3.3V     86.16mA    67.13mA    105mA
-1.4V     22.19mA    18.14mA    27.42mA
-1.267V   18.3mA     14.77mA    22.79mA
-1.133V   14.65mA    11.55mA    18.33mA
-900mV    8.728mA    6.543mA    10.98mA
-800mV    6.541mA    4.758mA    8.376mA
-700mV    4.737mA    3.229mA    6.166mA
-500mV    1.861mA    1.104mA    2.463mA
-400mV    851.5uA    442.9uA    1.148mA
-300mV    252.3uA    97.71uA    368.1uA
-200mV    33uA       10.48uA    62.12uA
0V        112.3nA    122.9nA    533.6nA
[Pulldown]
|   voltage   I(typ)   I(min)   I(max)
-3.3V     -1.944mA   -1.033mA   -1.887mA
-1.5V     -13.44mA   -7.698mA   -16.86mA
-700mV    -12.84mA   -9.216mA   -15.12mA
-400mV    -9.372mA   -6.707mA   -11.45mA
900mV     20.28mA    14.47mA    25.55mA
1.8V      35.39mA    25.05mA    44.9mA
2.3V      38.1mA     26.79mA    48.93mA
3.6V      39.58mA    27.88mA    51.22mA
4.1V      34.1mA     22.03mA    47.31mA
5.2V      13.11mA    5.026mA    22.46mA
5.8V      6.025mA    1.586mA    11.39mA
6.6V      1.393mA    699.1uA    3.101mA
[Pullup]
|   voltage   I(typ)   I(min)   I(max)
-3.3V     5.394mA    1.815mA    7.122mA
-1.6V     14.52mA    8.237mA    18.96mA
-600mV    11.14mA    7.958mA    14.14mA
-300mV    6.902mA    4.843mA    8.81mA
1.3V      -29.12mA   -19.42mA   -37.44mA
2.2V      -45.34mA   -27.53mA   -58.77mA
2.9V      -52.9mA    -29.98mA   -70.61mA
3.8V      -56.59mA   -29.42mA   -78.12mA
4.4V      -47.38mA   -19.32mA   -69.67mA
5.2V      -26.71mA   -4.49mA    -47.76mA
6.1V      -6.965mA   -911.1uA   -17.46mA
6.6V      -2.733mA   -594.2uA   -9.225mA
[GND_clamp]
|   voltage   I(typ)   I(min)   I(max)
-3.3V     -101.7mA   -80.79mA   -121.3mA
-1.3V     -22.2mA    -19.39mA   -27.16mA
-1.233V   -19.78mA   -17.37mA   -24.48mA
-1.167V   -17.44mA   -15.37mA   -21.83mA
-1.1V     -15.19mA   -13.39mA   -19.23mA
-1.033V   -13.05mA   -11.49mA   -16.69mA
-900mV    -8.932mA   -7.846mA   -11.77mA
-700mV    -4.017mA   -3.295mA   -6.019mA
-500mV    -1.012mA   -729.3uA   -1.957mA
-366.7mV  -174uA     -140.5uA   -464.2uA
-166.7mV  -4.976uA   -4.707uA   -10.04uA
3.233V    80.15nA    1.448uA    401nA
[Ramp]
| variable   typ   min   max
dV/dt_f  1.0170176/0.41794987n 0.79869191/0.93771927n  1.1953436/0.271774n
dV/dt_r  1.0440284/0.31176273n 0.78036067/0.77067259n  1.2327032/0.20156041n
R_load = 50
[Rising Waveform]
R_fixture = 50.0000
V_fixture = 3.3
V_fixture_min = 3.14
V_fixture_max = 3.47
|   time   V(typ)   V(min)   V(max)
121.5ps   1.631V     1.866V     1.493V
178.8ps   1.632V     1.868V     1.707V
243.5ps   1.657V     1.868V     2.545V
273.9ps   1.735V     1.867V     2.797V
392.4ps   2.712V     1.867V     3.154V
530.9ps   3.012V     1.892V     3.431V
597.3ps   3.106V     2.03V      3.453V
766.9ps   3.267V     2.786V     3.463V
1.082ns   3.293V     3.044V     3.466V
3.347ns   3.3V       3.14V      3.47V
[Rising Waveform]
R_fixture = 50.0000
V_fixture = 0
V_fixture_min = 0
V_fixture_max = 0
|   time   V(typ)   V(min)   V(max)
19.9ps    36.66uV    19.98uV    57.66uV
398ps     -9.361mV   14.62uV    88.58mV
536.5ps   -163.3uV   -1.491mV   647.9mV
701.5ps   189.3mV    -5.576mV   1.695V
858.9ps   635.5mV    -5.246mV   1.924V
1.063ns   1.362V     -1.363mV   1.983V
1.245ns   1.587V     5.928mV    2.005V
2.352ns   1.7V       1.041V     2.033V
3.24ns    1.714V     1.2V       2.038V
3.246ns   1.728V     1.275V     2.043V
[Falling Waveform]
R_fixture = 50.0000
V_fixture = 3.3
V_fixture_min = 3.14
V_fixture_max = 3.47
|   time   V(typ)   V(min)   V(max)
121.5ps   3.3V       3.14V      3.47V
279.7ps   3.305V     3.143V     3.466V
352ps     3.303V     3.143V     3.343V
540.6ps   3.276V     3.143V     2.672V
722.1ps   2.944V     3.143V     1.818V
859.4ps   2.652V     3.142V     1.595V
1.164ns   1.881V     3.116V     1.517V
1.359ns   1.707V     2.975V     1.499V
2.552ns   1.614V     1.976V     1.484V
3.347ns   1.631V     1.866V     1.493V
[Falling Waveform]
R_fixture = 50.0000
V_fixture = 0
V_fixture_min = 0
V_fixture_max = 0
|   time   V(typ)   V(min)   V(max)
19.9ps    1.728V     1.275V     2.043V
78.16ps   1.718V     1.277V     1.956V
165.2ps   1.582V     1.273V     1.564V
343.5ps   856.7mV    1.146V     351.8mV
392.3ps   660.1mV    1.044V     138mV
447.9ps   464.7mV    915.2mV    47mV
595ps     127.5mV    610.9mV    13.7mV
669.3ps   43.03mV    489.9mV    9.81mV
1.24ns    4.771mV    41.78mV    2.715mV
3.246ns   36.66uV    19.98uV    57.66uV
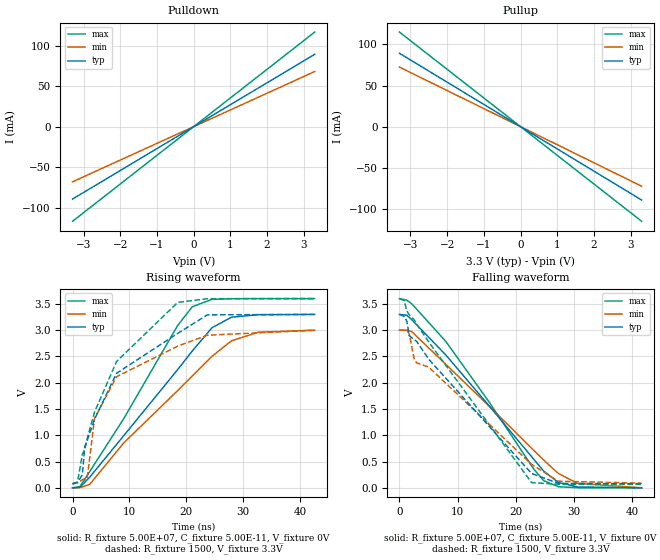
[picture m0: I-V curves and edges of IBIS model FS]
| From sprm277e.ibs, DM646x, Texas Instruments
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|************************ PHYUSR501AFE *******************************
[Model] FS
Model_type Output
Polarity Non-Inverting
Cref = 2.0pF
Rref = 50
Vref = 0V
Vmeas =0.350V
| typ min max
C_comp 2.0pF NA NA
|Voh = 0.3V
|Vol = 0.075V
|[Model Spec]
| typ min max
| typ min max
|Voh 0.7V 0.3V 1.15V
|Vol 0.01V -0.3V 0.075V
[Temperature Range] 25 125 -40
[Voltage Range] 3.30V 3.0V 3.6V
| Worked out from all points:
|   slope of the pulldown table from 0 to 0.495 V, typ, clamps not added: 36.9 ohm
|   slope of the pullup table from 0 to 0.495 V, typ, clamps not added: 37 ohm
|   rising waveform, R_fixture 5.00E+07, C_fixture 5.00E-11, V_fixture 0V: 20-80 % time 14.8ns typ, 16.7ns min, 11.7ns max; typ from 0 V to 3.3 V
|   falling waveform, R_fixture 5.00E+07, C_fixture 5.00E-11, V_fixture 0V: 20-80 % time 15.1ns typ, 16.6ns min, 13.7ns max; typ from 3.3 V to 0 V
|   rising waveform, R_fixture 1500, V_fixture 3.3V: 20-80 % time 9.74ns typ, 7.63ns min, 9.32ns max; typ from 0.078 V to 3.3 V
|   falling waveform, R_fixture 1500, V_fixture 3.3V: 20-80 % time 15.3ns typ, 17.8ns min, 14.2ns max; typ from 3.3 V to 0.079 V
| (Vdd votage range) 1.50V 1.35V 1.65V
| (Process strength) nominal weak strong
[Pulldown]
-3.3V     -89.5mA    -68.2mA    -117mA
0V        0A         0A         0A
3.3V      89.5mA     68.2mA     117mA
[Pullup]
-3.3V     89.2mA     72.4mA     115mA
0V        0A         0A         0A
3.3V      -89.2mA    -72.4mA    -115mA
[Ramp]
| variable typ min max
dV/dt_r 1.97881V/14.8414ns 1.7982V/16.6787ns 2.1594V/11.7342ns
dV/dt_f 1.97937V/15.1228ns 1.79822V/16.5615ns 2.1594V/13.6582ns
R_load = 5.00E+07
[Rising Waveform]
R_fixture = 5.00E+07
C_fixture = 5.00E-11
V_fixture = 0V
V_fixture_min = 0V
V_fixture_max = 0V
0s        -10.49uV   -7.857uV   -4.091uV
1.29ns    10.84mV    2.794mV    22.1mV
3.01ns    201.9mV    65.11mV    307.8mV
9.03ns    995.6mV    857.5mV    1.321V
18.49ns   2.249V     1.85V      3.088V
21.07ns   2.605V     2.13V      3.445V
24.51ns   3.044V     2.5V       3.584V
27.95ns   3.245V     2.796V     3.597V
32.68ns   3.293V     2.96V      3.599V
42.57ns   3.298V     2.997V     3.599V
|   4.3E-08S   3.29800V   2.99700V   3.59900V
[Falling Waveform]
R_fixture = 5.00E+07
C_fixture = 5.00E-11
V_fixture = 0V
V_fixture_min = 0V
V_fixture_max = 0V
0s        3.299V     2.998V     3.599V
1.26ns    3.283V     2.999V     3.569V
2.1ns     3.2V       2.972V     3.503V
7.98ns    2.525V     2.348V     2.783V
15.54ns   1.542V     1.539V     1.611V
23.1ns    539.2mV    710.5mV    352.8mV
24.78ns   317.9mV    527.1mV    136.3mV
27.3ns    101.2mV    273.1mV    21.27mV
30.66ns   16.35mV    82.67mV    1.496mV
41.58ns   67.45uV    1.138mV    6.057uV
|   4.20E-08S   50.04000uV   0.96040mV   5.55000uV
[Rising Waveform]
R_fixture = 1500
C_fixture = 0
V_fixture = 3.3V
V_fixture_min = 3.0V
V_fixture_max = 3.6V
0s        78.44mV    89.57mV    65.87mV
860ps     110mV      89.68mV    105.7mV
1.72ns    244.7mV    155.3mV    633mV
2.15ns    783.2mV    171.1mV    740.3mV
2.58ns    899.2mV    189.1mV    938.3mV
3.87ns    1.307V     1.321V     1.442V
7.74ns    2.179V     2.113V     2.403V
18.5ns    2.938V     2.696V     3.527V
23.7ns    3.29V      2.903V     3.597V
42.6ns    3.298V     2.998V     3.599V
|   0.000000043   3.29900V   2.99800V   3.59900V
[Falling Waveform]
R_fixture = 1500
C_fixture = 0
V_fixture = 3.3V
V_fixture_min = 3.0V
V_fixture_max = 3.6V
0s        3.299V     2.998V     3.599V
840ps     3.258V     3V         3.559V
1.26ns    3.173V     3.002V     3.364V
1.68ns    2.895V     2.928V     3.294V
2.52ns    2.816V     2.458V     3.197V
2.94ns    2.789V     2.377V     3.116V
5.04ns    2.445V     2.296V     2.773V
22.7ns    273mV      445.9mV    99.59mV
27.3ns    85.36mV    125.5mV    67.59mV
41.6ns    78.52mV    90.16mV    65.93mV
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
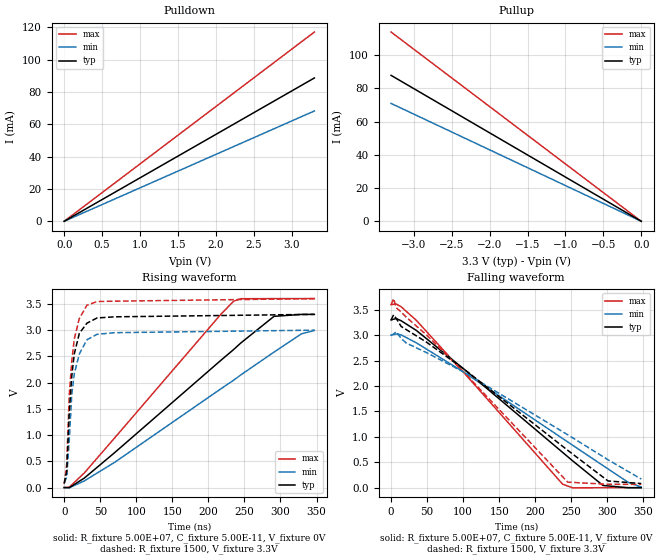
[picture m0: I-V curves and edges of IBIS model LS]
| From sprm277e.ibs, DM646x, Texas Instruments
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|   0.000000042   8.02200mV   9.40700mV   6.70800mV
[Model] LS
Model_type Output
Polarity Non-Inverting
Cref = 2.0pF
Rref = 50
Vref = 0V
Vmeas =0.350V
| typ min max
C_comp 2.0pF NA NA
|Voh = 0.3V
|Vol = 0.075V
|[Model Spec]
| typ min max
| typ min max
|Voh 0.7V 0.3V 1.15V
|Vol 0.01V -0.3V 0.075V
[Temperature Range] 25 125 -40
[Voltage Range] 3.30V 3.0V 3.6V
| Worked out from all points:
|   slope of the pulldown table from 0 to 0.495 V, typ, clamps not added: 37.2 ohm
|   rising waveform, R_fixture 5.00E+07, C_fixture 5.00E-11, V_fixture 0V: 20-80 % time 166ns typ, 189ns min, 135ns max; typ from 0 V to 3.3 V
|   falling waveform, R_fixture 5.00E+07, C_fixture 5.00E-11, V_fixture 0V: 20-80 % time 167ns typ, 189ns min, 136ns max; typ from 3.3 V to 0 V
|   rising waveform, R_fixture 1500, V_fixture 3.3V: 20-80 % time 10.7ns typ, 12.2ns min, 10.6ns max; typ from 0.079 V to 3.3 V
|   falling waveform, R_fixture 1500, V_fixture 3.3V: 20-80 % time 176ns typ, 199ns min, 143ns max; typ from 3.3 V to 0.082 V
| (Vdd votage range) 1.50V 1.35V 1.65V
| (Process strength) nominal weak strong
[Pulldown]
0V        0A         0A         0A
3.3V      88.6mA     68.2mA     117mA
[Pullup]
-3.3V     87.9mA     71mA       114mA
0V        0A         0A         0A
[Ramp]
| variable typ min max
dV/dt_r 1.97881V/14.8414ns 1.7982V/16.6787ns 2.1594V/11.7342ns
dV/dt_f 1.97937V/15.1228ns 1.79822V/16.5615ns 2.1594V/13.6582ns
R_load = 5.00E+07
[Rising Waveform]
R_fixture = 5.00E+07
C_fixture = 5.00E-11
V_fixture = 0V
V_fixture_min = 0V
V_fixture_max = 0V
0s        4.155uV    31.82uV    4.408uV
7ns       -1.844mV   -5.257mV   7.213mV
28ns      181.8mV    127.9mV    279.9mV
70ns      665.9mV    480.8mV    945.9mV
217ns     2.42V      1.878V     3.296V
235ns     2.629V     2.045V     3.549V
245ns     2.754V     2.146V     3.597V
291ns     3.261V     2.58V      3.599V
329ns     3.298V     2.928V     3.599V
347ns     3.298V     2.991V     3.599V
|   0.00000035   3.29800V   2.99500V   3.59900V
[Falling Waveform]
R_fixture = 5.00E+07
C_fixture = 5.00E-11
V_fixture = 0V
V_fixture_min = 0V
V_fixture_max = 0V
0s        3.298V     2.998V     3.599V
7ns       3.327V     3.024V     3.613V
14ns      3.282V     3.004V     3.557V
35ns      3.093V     2.849V     3.291V
102ns     2.321V     2.262V     2.246V
238ns     693.7mV    967.1mV    68.69mV
252ns     526.5mV    834mV      -2.385mV
294ns     43.66mV    434.9mV    63.52uV
329ns     128.3uV    104.8mV    59.22uV
347ns     91.05uV    11.37mV    54.52uV
|   0.00000035   87.37000uV   4.16600mV   51.18000uV
[Rising Waveform]
R_fixture = 1500
C_fixture = 0
V_fixture = 3.3V
V_fixture_min = 3.0V
V_fixture_max = 3.6V
0s        78.8mV     91.18mV    66mV
3.5ns     302.5mV    195.7mV    454.1mV
7ns       1.42V      901.3mV    1.769V
10.5ns    2.124V     1.775V     2.406V
14ns      2.547V     2.169V     2.832V
21ns      2.937V     2.545V     3.221V
31.5ns    3.131V     2.815V     3.472V
45.5ns    3.23V      2.919V     3.544V
70ns      3.252V     2.95V      3.55V
347ns     3.299V     2.998V     3.599V
|   0.00000035   3.29900V   2.99800V   3.59900V
[Falling Waveform]
R_fixture = 1500
C_fixture = 0
V_fixture = 3.3V
V_fixture_min = 3.0V
V_fixture_max = 3.6V
0s        3.299V     2.998V     3.599V
3.5ns     3.399V     3.02V      3.718V
7ns       3.33V      3.067V     3.542V
14ns      3.17V      2.934V     3.454V
21ns      3.109V     2.845V     3.354V
49ns      2.863V     2.657V     3.006V
102ns     2.322V     2.265V     2.256V
245ns     735.7mV    1.041V     109.2mV
301ns     132.7mV    549mV      66.88mV
347ns     82.4mV     169.9mV    66.15mV
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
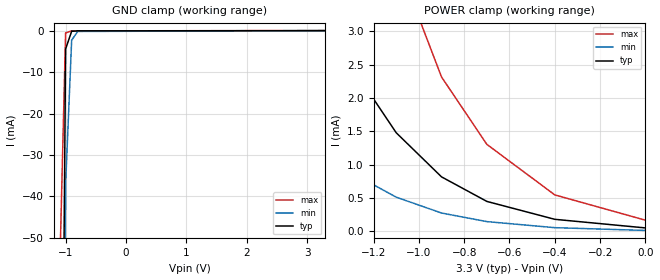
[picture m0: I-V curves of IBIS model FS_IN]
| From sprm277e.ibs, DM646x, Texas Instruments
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|   0.000000002   0.002998891   0.00664113   1.83000mV
[Model] FS_IN
Model_type Input
Polarity Non-Inverting
Vinh = 0.7V
Vinl = 0.0V
| typ min max
C_comp 0.0pF NA NA
[Model Spec]
| typ min max
Vinh 0.7V 0.30V 1.15V
Vinl 0.0V -0.30V 0.15V
[Temperature Range] 25 125 -40
[Voltage Range] 3.3V 3.0V 3.6V
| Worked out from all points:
|   GND clamp passes 1 mA (typ) near -0.92 V on its own axis
|   POWER clamp passes 1 mA (typ) near -0.96 V on its own axis
[GND clamp]
-3.3V     -16.63A    -12.74A    -20.99A
-1.1V     -184.8mA   -422.9mA   -59.24mA
-1V       -4.396mA   -37.09mA   -497.4uA
-900mV    -104.7uA   -2.257mA   -4.431uA
-800mV    -2.608uA   -137.4uA   -230.6nA
3.3V      53.44uA    41.59uA    69.05uA
[POWER clamp]
-3.3V     795.9mA    363.7mA    1.784A
-1.8V     11.38mA    4.339mA    29.17mA
-1.6V     6.382mA    2.372mA    16.71mA
-1.5V     4.773mA    1.751mA    12.63mA
-1.4V     3.567mA    1.291mA    9.539mA
-1.3V     2.663mA    951.3uA    7.199mA
-1.2V     1.986mA    699.9uA    5.429mA
-1.1V     1.48mA     514.4uA    4.091mA
-900mV    818.7uA    276.8uA    2.316mA
-700mV    450.8uA    148.1uA    1.306mA
-400mV    182.4uA    57.28uA    548.3uA
0V        53.44uA    15.74uA    169.3uA
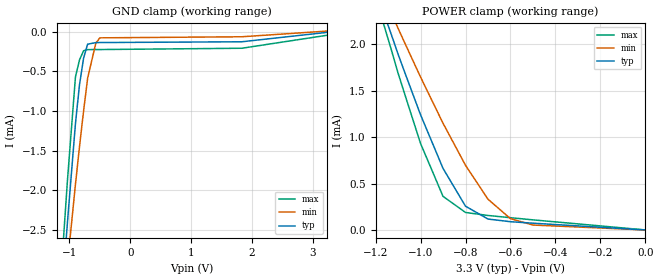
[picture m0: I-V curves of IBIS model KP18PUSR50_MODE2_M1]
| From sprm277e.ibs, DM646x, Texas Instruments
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|   Model Cell KP18PUSR50_MODE2_M1
[Model]   KP18PUSR50_MODE2_M1
Model_type   Input
Polarity   Non-Inverting
Vinl =  0.8V
Vinh =  2V
C_comp   0.7641276p   0.7005841p   0.8387284p
[Model Spec]
Vinl   0.8V   0.8V   0.8V
Vinh   2V   2V   2V
[Temperature Range]   25   125   -40
[Voltage Range]   3.3   3.14   3.47
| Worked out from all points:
|   GND clamp passes 1 mA (typ) near -0.88 V on its own axis
|   POWER clamp passes 1 mA (typ) near -0.96 V on its own axis
[POWER_clamp]
|   voltage   I(typ)   I(min)   I(max)
-3.3V     17.71mA    14.37mA    20.92mA
-1.167V   2.359mA    2.531mA    2.241mA
-1.133V   2.126mA    2.352mA    1.966mA
-1.1V     1.894mA    2.172mA    1.69mA
-1.067V   1.676mA    1.997mA    1.438mA
-1V       1.241mA    1.647mA    931.9uA
-900mV    663.2uA    1.149mA    362.3uA
-800mV    255.9uA    696.3uA    188.5uA
-700mV    117.6uA    331uA      156.2uA
-600mV    89.11uA    121.6uA    132.2uA
-500mV    73uA       53.1uA     108.9uA
0V        95.23nA    92.09nA    222.7nA
[GND_clamp]
|   voltage   I(typ)   I(min)   I(max)
-3.3V     -26.2mA    -21.58mA   -29.28mA
-1.167V   -3.771mA   -4.001mA   -3.451mA
-1.1V     -3.083mA   -3.467mA   -2.648mA
-1.033V   -2.417mA   -2.944mA   -1.888mA
-900mV    -1.156mA   -1.923mA   -569uA
-833.3mV  -666.4uA   -1.446mA   -354.7uA
-766.7mV  -333.7uA   -1mA       -240.5uA
-700mV    -157.8uA   -585.7uA   -226.4uA
-566.7mV  -137.7uA   -148.5uA   -225.4uA
-500mV    -137.1uA   -77.82uA   -225.3uA
1.833V    -127.3uA   -64.22uA   -208.9uA
3.233V    -8.72uA    7.659uA    -45.2uA
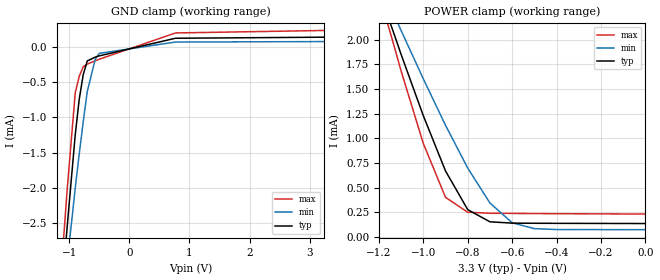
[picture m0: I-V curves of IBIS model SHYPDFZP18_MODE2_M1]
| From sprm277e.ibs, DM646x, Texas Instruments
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|   Model Cell SHYPDFZP18_MODE2_M1
[Model]   SHYPDFZP18_MODE2_M1
Model_type   Input
Polarity   Non-Inverting
Vinl =  0.8V
Vinh =  2V
C_comp   0.7732787p   0.7094674p   0.8496547p
[Model Spec]
Vinl   0.8V   0.8V   0.8V
Vinh   2V   2V   2V
[Temperature Range]   25   125   -40
[Voltage Range]   3.3   3.14   3.47
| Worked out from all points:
|   GND clamp passes 1 mA (typ) near -0.87 V on its own axis
|   POWER clamp passes 1 mA (typ) near -0.96 V on its own axis
[POWER_clamp]
|   voltage   I(typ)   I(min)   I(max)
-3.3V     16.34mA    13.45mA    19.16mA
-1.167V   2.282mA    2.426mA    2.21mA
-1.133V   2.066mA    2.259mA    1.947mA
-1.1V     1.85mA     2.092mA    1.683mA
-1V       1.229mA    1.602mA    948.2uA
-900mV    669.2uA    1.132mA    401.7uA
-800mV    277.2uA    698.2uA    250.7uA
-700mV    154uA      344.3uA    240.8uA
-600mV    140.6uA    144.3uA    239uA
-500mV    139.2uA    84.85uA    237.5uA
-400mV    138.5uA    75.78uA    236.2uA
0V        136.6uA    74.08uA    232.5uA
[GND_clamp]
|   voltage   I(typ)   I(min)   I(max)
-3.3V     -27.75mA   -22.6mA    -31.32mA
-1.167V   -3.925mA   -4.149mA   -3.612mA
-1.1V     -3.217mA   -3.594mA   -2.789mA
-1.033V   -2.536mA   -3.052mA   -2.01mA
-900mV    -1.245mA   -2.001mA   -652.2uA
-833.3mV  -740.4uA   -1.513mA   -416.6uA
-766.7mV  -391.9uA   -1.057mA   -280.5uA
-700mV    -199.6uA   -632.6uA   -244.1uA
-566.7mV  -145.5uA   -173.9uA   -198uA
-500mV    -127.8uA   -92.17uA   -175.2uA
766.7mV   121.4uA    67.78uA    196.4uA
3.233V    136.4uA    74.23uA    231.4uA
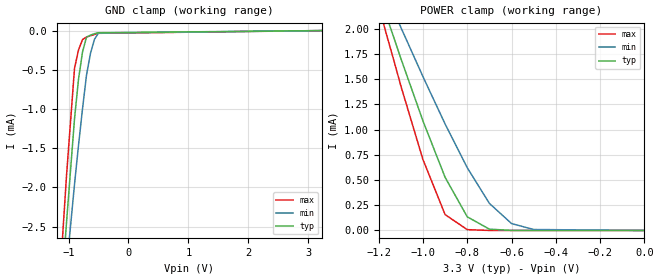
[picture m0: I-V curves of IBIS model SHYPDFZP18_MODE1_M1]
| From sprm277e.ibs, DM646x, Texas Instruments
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|   Model Cell SHYPDFZP18_MODE1_M1
[Model]   SHYPDFZP18_MODE1_M1
Model_type   Input
Polarity   Non-Inverting
Vinl =  0.8V
Vinh =  2V
C_comp   0.7732787p   0.7094674p   0.8496547p
[Model Spec]
Vinl   0.8V   0.8V   0.8V
Vinh   2V   2V   2V
[Temperature Range]   25   125   -40
[Voltage Range]   3.3   3.14   3.47
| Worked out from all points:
|   GND clamp passes 1 mA (typ) near -0.88 V on its own axis
|   POWER clamp passes 1 mA (typ) near -0.98 V on its own axis
[POWER_clamp]
|   voltage   I(typ)   I(min)   I(max)
-3.3V     16.09mA    13.31mA    18.76mA
-1.2V     2.351mA    2.515mA    2.222mA
-1.167V   2.136mA    2.348mA    1.959mA
-1.133V   1.92mA     2.18mA     1.696mA
-1.1V     1.705mA    2.013mA    1.433mA
-1V       1.085mA    1.524mA    701.6uA
-900mV    526.2uA    1.055mA    157.3uA
-800mV    135.4uA    621.7uA    8.319uA
-700mV    13.19uA    268.3uA    367.1nA
-600mV    617.7nA    68.74uA    260.2nA
-500mV    119.5nA    9.656uA    252.8nA
0V        95.63nA    96.62nA    223.7nA
[GND_clamp]
|   voltage   I(typ)   I(min)   I(max)
-3.3V     -27.74mA   -22.6mA    -31.32mA
-1.167V   -3.875mA   -4.137mA   -3.494mA
-1.1V     -3.146mA   -3.578mA   -2.639mA
-1.033V   -2.444mA   -3.03mA    -1.848mA
-900mV    -1.127mA   -1.961mA   -482.2uA
-833.3mV  -621.6uA   -1.464mA   -247.9uA
-766.7mV  -273.8uA   -999.5uA   -114.6uA
-700mV    -83.63uA   -568.8uA   -82.13uA
-633.3mV  -57.76uA   -289.8uA   -65.06uA
-566.7mV  -39.01uA   -110.7uA   -49.18uA
-500mV    -27.37uA   -31.63uA   -34.48uA
3.233V    94.38nA    98.48nA    211.4nA
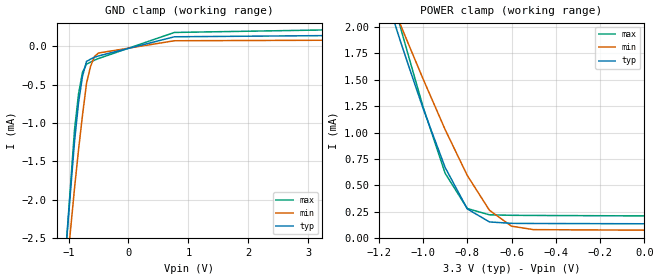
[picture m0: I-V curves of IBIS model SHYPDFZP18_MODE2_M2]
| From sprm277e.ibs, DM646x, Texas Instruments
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|   Model Cell SHYPDFZP18_MODE2_M2
[Model]   SHYPDFZP18_MODE2_M2
Model_type   Input
Polarity   Non-Inverting
Vinl =  0.8V
Vinh =  2V
C_comp   0.7732787p   0.7118968p   0.8502484p
[Model Spec]
Vinl   0.8V   0.8V   0.8V
Vinh   2V   2V   2V
[Temperature Range]   25   105   0
[Voltage Range]   3.3   3.14   3.47
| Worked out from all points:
|   GND clamp passes 1 mA (typ) near -0.87 V on its own axis
|   POWER clamp passes 1 mA (typ) near -0.96 V on its own axis
[POWER_clamp]
|   voltage   I(typ)   I(min)   I(max)
-3.3V     16.34mA    13.71mA    19mA
-1.133V   2.067mA    2.185mA    2.24mA
-1.1V     1.851mA    2.012mA    1.981mA
-1.067V   1.644mA    1.844mA    1.736mA
-1V       1.23mA     1.509mA    1.245mA
-900mV    669.6uA    1.028mA    614.9uA
-800mV    277.7uA    594uA      281.2uA
-700mV    154.5uA    265.1uA    221.7uA
-600mV    141uA      114.2uA    217.1uA
-500mV    139.7uA    81.39uA    215.7uA
0V        137uA      76.36uA    211.3uA
[GND_clamp]
|   voltage   I(typ)   I(min)   I(max)
-3.3V     -27.75mA   -23.32mA   -31.25mA
-1.1V     -3.217mA   -3.5mA     -3.314mA
-1.033V   -2.536mA   -2.939mA   -2.537mA
-900mV    -1.245mA   -1.853mA   -1.094mA
-833.3mV  -740.7uA   -1.355mA   -626uA
-766.7mV  -392.2uA   -898.9uA   -340.1uA
-700mV    -199.8uA   -485.6uA   -235.9uA
-633.3mV  -169.6uA   -266.6uA   -207.8uA
-566.7mV  -145.6uA   -134.6uA   -183uA
-500mV    -128uA     -89.72uA   -161.5uA
766.7mV   121.7uA    69.98uA    178.1uA
3.233V    136.8uA    76.52uA    210.3uA
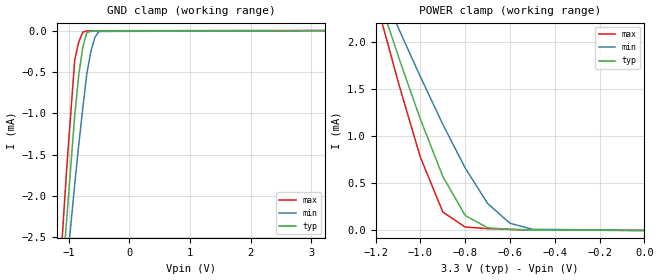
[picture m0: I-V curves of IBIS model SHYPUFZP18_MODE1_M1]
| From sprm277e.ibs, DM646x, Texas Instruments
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|   Model Cell SHYPUFZP18_MODE1_M1
[Model]   SHYPUFZP18_MODE1_M1
Model_type   Input
Polarity   Non-Inverting
Vinl =  0.8V
Vinh =  2V
C_comp   0.7647563p   0.701391p   0.8403617p
[Model Spec]
Vinl   0.8V   0.8V   0.8V
Vinh   2V   2V   2V
[Temperature Range]   25   125   -40
[Voltage Range]   3.3   3.14   3.47
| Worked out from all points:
|   GND clamp passes 1 mA (typ) near -0.90 V on its own axis
|   POWER clamp passes 1 mA (typ) near -0.97 V on its own axis
[POWER_clamp]
|   voltage   I(typ)   I(min)   I(max)
-3.3V     17.7mA     14.37mA    20.92mA
-1.167V   2.338mA    2.525mA    2.173mA
-1.133V   2.101mA    2.344mA    1.88mA
-1.1V     1.864mA    2.164mA    1.588mA
-1.067V   1.637mA    1.988mA    1.319mA
-1V       1.184mA    1.636mA    779.8uA
-900mV    576uA      1.13mA     196.9uA
-800mV    159.5uA    664.7uA    36.48uA
-700mV    28.98uA    287.6uA    19.64uA
-600mV    10.75uA    76.67uA    12.02uA
-500mV    5.715uA    13.26uA    6.166uA
0V        95.72nA    92.48nA    222.9nA
[GND_clamp]
|   voltage   I(typ)   I(min)   I(max)
-3.3V     -26.08mA   -21.52mA   -29.08mA
-1.167V   -3.644mA   -3.938mA   -3.242mA
-1.1V     -2.956mA   -3.405mA   -2.438mA
-1.033V   -2.29mA    -2.882mA   -1.678mA
-900mV    -1.027mA   -1.86mA    -354.7uA
-833.3mV  -536.2uA   -1.383mA   -136.3uA
-766.7mV  -201.4uA   -936.8uA   -19.12uA
-700mV    -22.93uA   -521.4uA   -3.15uA
-633.3mV  -8.863uA   -252.1uA   -2.584uA
-566.7mV  -1.535uA   -81.79uA   -2.296uA
-500mV    -942nA     -10.4uA    -2.286uA
3.233V    94.11nA    98.88nA    210.4nA
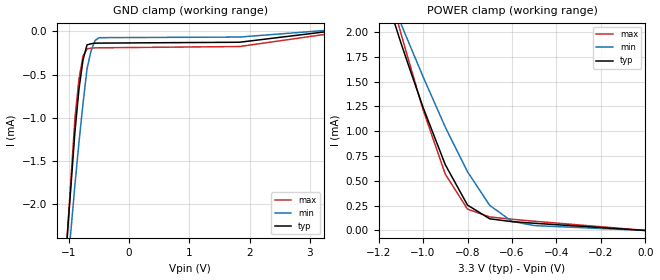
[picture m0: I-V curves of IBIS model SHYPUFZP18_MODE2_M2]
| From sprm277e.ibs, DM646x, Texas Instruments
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|   Model Cell SHYPUFZP18_MODE2_M2
[Model]   SHYPUFZP18_MODE2_M2
Model_type   Input
Polarity   Non-Inverting
Vinl =  0.8V
Vinh =  2V
C_comp   0.7647563p   0.7034294p   0.8410468p
[Model Spec]
Vinl   0.8V   0.8V   0.8V
Vinh   2V   2V   2V
[Temperature Range]   25   105   0
[Voltage Range]   3.3   3.14   3.47
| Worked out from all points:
|   GND clamp passes 1 mA (typ) near -0.88 V on its own axis
|   POWER clamp passes 1 mA (typ) near -0.96 V on its own axis
[POWER_clamp]
|   voltage   I(typ)   I(min)   I(max)
-3.3V     17.71mA    14.67mA    20.82mA
-1.133V   2.126mA    2.273mA    2.272mA
-1.1V     1.894mA    2.088mA    1.99mA
-1.067V   1.676mA    1.909mA    1.733mA
-1V       1.241mA    1.55mA     1.218mA
-900mV    663.2uA    1.042mA    567.9uA
-800mV    255.8uA    591.9uA    215uA
-700mV    117.5uA    252.4uA    136.6uA
-600mV    89.09uA    91.71uA    113.3uA
-500mV    72.99uA    49.44uA    93.38uA
0V        95.23nA    66.33nA    458.2nA
[GND_clamp]
|   voltage   I(typ)   I(min)   I(max)
-3.3V     -26.2mA    -22.27mA   -29.13mA
-1.1V     -3.083mA   -3.375mA   -3.167mA
-1.033V   -2.417mA   -2.83mA    -2.409mA
-900mV    -1.156mA   -1.771mA   -1.002mA
-833.3mV  -666.4uA   -1.283mA   -553.5uA
-766.7mV  -333.7uA   -838.1uA   -287uA
-700mV    -157.8uA   -435.3uA   -203uA
-633.3mV  -144.6uA   -227.7uA   -195.7uA
-566.7mV  -137.7uA   -107.3uA   -191.9uA
-500mV    -137.1uA   -74.19uA   -191.4uA
1.833V    -127.1uA   -67.09uA   -176.6uA
3.233V    -8.718uA   8.017uA    -38.34uA
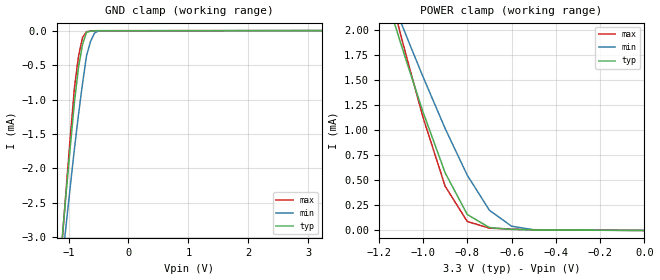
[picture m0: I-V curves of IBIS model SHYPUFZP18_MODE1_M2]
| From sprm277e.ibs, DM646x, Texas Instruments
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|   Model Cell SHYPUFZP18_MODE1_M2
[Model]   SHYPUFZP18_MODE1_M2
Model_type   Input
Polarity   Non-Inverting
Vinl =  0.8V
Vinh =  2V
C_comp   0.7647563p   0.7034294p   0.8410468p
[Model Spec]
Vinl   0.8V   0.8V   0.8V
Vinh   2V   2V   2V
[Temperature Range]   25   105   0
[Voltage Range]   3.3   3.14   3.47
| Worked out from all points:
|   GND clamp passes 1 mA (typ) near -0.90 V on its own axis
|   POWER clamp passes 1 mA (typ) near -0.97 V on its own axis
[POWER_clamp]
|   voltage   I(typ)   I(min)   I(max)
-3.3V     17.7mA     14.67mA    20.82mA
-1.133V   2.101mA    2.265mA    2.234mA
-1.1V     1.864mA    2.079mA    1.946mA
-1.067V   1.637mA    1.897mA    1.674mA
-1V       1.184mA    1.535mA    1.13mA
-900mV    576uA      1.018mA    442.2uA
-800mV    159.5uA    551.6uA    89.62uA
-700mV    28.98uA    201.9uA    23.37uA
-600mV    10.75uA    42.88uA    13.46uA
-500mV    5.715uA    6.943uA    7.75uA
0V        95.71nA    66.54nA    459.6nA
[GND_clamp]
|   voltage   I(typ)   I(min)   I(max)
-3.3V     -26.08mA   -22.2mA    -28.95mA
-1.1V     -2.956mA   -3.309mA   -2.988mA
-1.033V   -2.29mA    -2.765mA   -2.229mA
-966.7mV  -1.647mA   -2.23mA    -1.507mA
-900mV    -1.027mA   -1.705mA   -821.9uA
-833.3mV  -536.2uA   -1.217mA   -371uA
-766.7mV  -201.4uA   -771.2uA   -102.1uA
-700mV    -22.93uA   -367.4uA   -15.16uA
-633.3mV  -8.863uA   -158.4uA   -6.831uA
-566.7mV  -1.535uA   -37.08uA   -2.457uA
-500mV    -942nA     -3.547uA   -2.041uA
3.233V    94.11nA    70.2nA     435.3nA
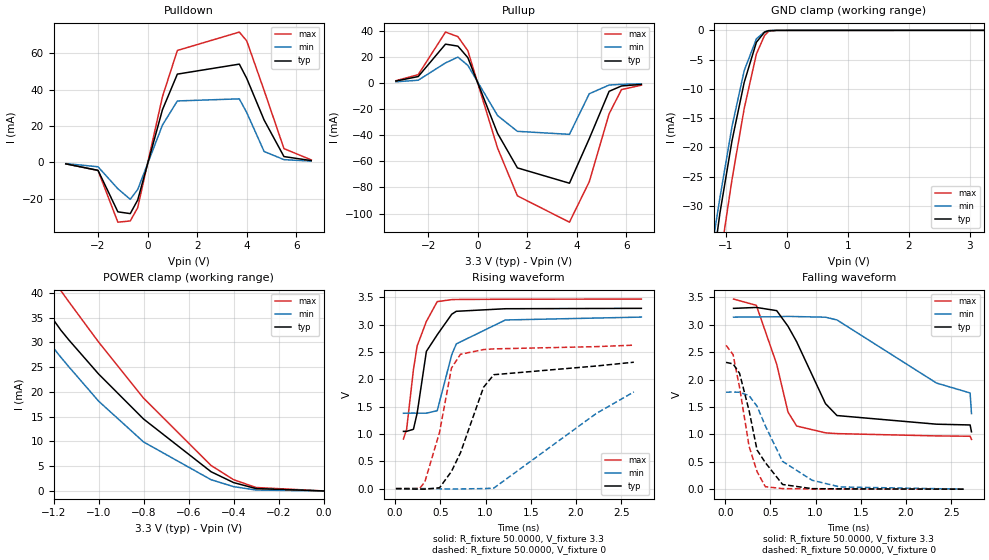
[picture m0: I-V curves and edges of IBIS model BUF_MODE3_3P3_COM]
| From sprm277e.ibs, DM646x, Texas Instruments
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|   Model Cell BUF_MODE3_3P3_COM
[Model]   BUF_MODE3_3P3_COM
Model_type   3-state
Polarity   Non-Inverting
Enable   Active-Low
Cref =  10.0000pF
Rref =  50.0000
Vref =  1.5V
Vmeas =  1.65
C_comp   2.460431p   2.38871p   2.515471p
[Temperature Range]   25   105   0
[Voltage Range]   3.3   3.14   3.47
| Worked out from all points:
|   slope of the pulldown table from 0 to 0.495 V, typ, clamps not added: 20.3 ohm
|   slope of the pullup table from 0 to 0.495 V, typ, clamps not added: 20 ohm
|   GND clamp passes 1 mA (typ) near -0.43 V on its own axis
|   POWER clamp passes 1 mA (typ) near -0.34 V on its own axis
|   rising waveform, R_fixture 50.0000, V_fixture 3.3: 20-80 % time 225ps typ, 302ps min, 173ps max; typ from 1.05 V to 3.3 V
|   rising waveform, R_fixture 50.0000, V_fixture 0: 20-80 % time 309ps typ, 817ps min, 197ps max; typ from 0 V to 2.31 V
|   falling waveform, R_fixture 50.0000, V_fixture 3.3: 20-80 % time 393ps typ, 1.21ns min, 252ps max; typ from 3.3 V to 1.05 V
|   falling waveform, R_fixture 50.0000, V_fixture 0: 20-80 % time 246ps typ, 371ps min, 177ps max; typ from 2.31 V to 0 V
[POWER_clamp]
|   voltage   I(typ)   I(min)   I(max)
-3.3V     198.1mA    153mA      242.5mA
-1.4V     48.45mA    40.47mA    58.81mA
-1.367V   45.97mA    38.5mA     55.88mA
-1.267V   38.79mA    32.65mA    47.53mA
-1.167V   32.44mA    26.97mA    40.42mA
-1.133V   30.55mA    25.13mA    38.27mA
-1V       23.63mA    18.15mA    30.08mA
-800mV    14.53mA    9.898mA    18.75mA
-500mV    3.882mA    2.27mA     5.148mA
-400mV    1.69mA     867.7uA    2.28mA
-300mV    474.6uA    180.9uA    692.3uA
0V        29.06nA    98.09nA    129.8nA
[Pulldown]
|   voltage   I(typ)   I(min)   I(max)
-3.3V     -857.2uA   -697.6uA   -837.5uA
-2V       -4.413mA   -2.459mA   -4.51mA
-1.2V     -27.23mA   -14.55mA   -32.92mA
-700mV    -28.2mA    -20.34mA   -32.24mA
-400mV    -20.75mA   -14.95mA   -24.96mA
600mV     28.95mA    20.5mA     36.11mA
1.2V      48.47mA    33.72mA    61.47mA
3.7V      53.96mA    34.87mA    71.57mA
4V        46.07mA    27.28mA    66.69mA
4.7V      23.22mA    5.946mA    39.48mA
5.5V      3.144mA    1.458mA    7.525mA
6.6V      939.1uA    651.5uA    1.319mA
[Pullup]
|   voltage   I(typ)   I(min)   I(max)
-3.3V     1.596mA    997.8uA    1.838mA
-2.4V     5.021mA    2.213mA    6.471mA
-1.3V     29.87mA    15.47mA    39.1mA
-800mV    28.34mA    19.93mA    35.61mA
-400mV    19.56mA    13.63mA    24.85mA
800mV     -38.51mA   -24.87mA   -49.81mA
1.6V      -64.97mA   -36.97mA   -86.4mA
3.7V      -76.73mA   -39.27mA   -106.6mA
4.5V      -42.52mA   -8.164mA   -75.56mA
5.3V      -6.294mA   -1.485mA   -23.49mA
5.8V      -2.184mA   -919.2uA   -4.958mA
6.6V      -1.015mA   -547.1uA   -1.589mA
[GND_clamp]
|   voltage   I(typ)   I(min)   I(max)
-3.3V     -226.9mA   -177.6mA   -274.2mA
-1.3V     -47.68mA   -41.99mA   -57.1mA
-1.233V   -41.93mA   -37.49mA   -50.61mA
-1.167V   -36.46mA   -33.04mA   -44.67mA
-1.1V     -31.26mA   -28.64mA   -39.3mA
-900mV    -18.81mA   -16.38mA   -25.43mA
-700mV    -8.866mA   -6.865mA   -13.32mA
-500mV    -2.027mA   -1.452mA   -4.029mA
-366.7mV  -316.4uA   -256.2uA   -875.7uA
-300mV    -51.48uA   -55.66uA   -176uA
-166.7mV  -7.25uA    -8.049uA   -14.2uA
3.233V    -25.89nA   2.48uA     -64.81nA
[Ramp]
| variable   typ   min   max
dV/dt_f  1.3624423/0.39650188n  1.0645712/1.3766382n  1.5496303/0.25309991n
dV/dt_r  1.3956192/0.31076348n  1.0672964/0.81926499n  1.5833314/0.19790758n
R_load = 50
[Rising Waveform]
R_fixture = 50.0000
V_fixture = 3.3
V_fixture_min = 3.14
V_fixture_max = 3.47
|   time   V(typ)   V(min)   V(max)
92.25ps   1.047V     1.379V     907.7mV
127.5ps   1.048V     1.381V     1.086V
202.9ps   1.086V     1.382V     2.178V
243.9ps   1.381V     1.381V     2.612V
346ps     2.512V     1.381V     3.061V
465.9ps   2.816V     1.426V     3.423V
626.9ps   3.193V     2.452V     3.46V
676.9ps   3.246V     2.649V     3.462V
1.22ns    3.293V     3.087V     3.467V
2.724ns   3.3V       3.14V      3.47V
[Rising Waveform]
R_fixture = 50.0000
V_fixture = 0
V_fixture_min = 0
V_fixture_max = 0
|   time   V(typ)   V(min)   V(max)
9.078ps   28.65uV    29.61uV    31.32uV
272.8ps   -10.49mV   62.05uV    5.52mV
328.4ps   -10.5mV    37.61uV    119.6mV
491.8ps   15.36mV    -3.126mV   1.032V
623.6ps   314.4mV    -9.001mV   2.207V
723.8ps   658.8mV    -6.055mV   2.46V
978.3ps   1.855V     -60.85uV   2.545V
1.092ns   2.085V     8.826mV    2.558V
2.223ns   2.244V     1.373V     2.599V
2.641ns   2.314V     1.77V      2.626V
[Falling Waveform]
R_fixture = 50.0000
V_fixture = 3.3
V_fixture_min = 3.14
V_fixture_max = 3.47
|   time   V(typ)   V(min)   V(max)
92.25ps   3.3V       3.14V      3.47V
343.9ps   3.317V     3.144V     3.356V
569.2ps   3.259V     3.147V     2.282V
694.4ps   2.974V     3.154V     1.407V
790.1ps   2.691V     3.15V      1.153V
1.109ns   1.561V     3.139V     1.028V
1.236ns   1.344V     3.089V     1.014V
2.337ns   1.186V     1.937V     972mV
2.709ns   1.172V     1.756V     966.2mV
2.724ns   1.047V     1.379V     907.7mV
[Falling Waveform]
R_fixture = 50.0000
V_fixture = 0
V_fixture_min = 0
V_fixture_max = 0
|   time   V(typ)   V(min)   V(max)
9.078ps   2.314V     1.77V      2.626V
86.68ps   2.287V     1.773V     2.457V
158.9ps   2.113V     1.769V     1.854V
264ps     1.433V     1.706V     781.8mV
351.9ps   715.8mV    1.514V     320.1mV
443.8ps   484.2mV    1.155V     45.14mV
634.6ps   85.81mV    507mV      10.1mV
960.5ps   9.091mV    163mV      4.528mV
1.269ns   5.859mV    40.57mV    2.692mV
2.641ns   28.65uV    29.61uV    31.32uV
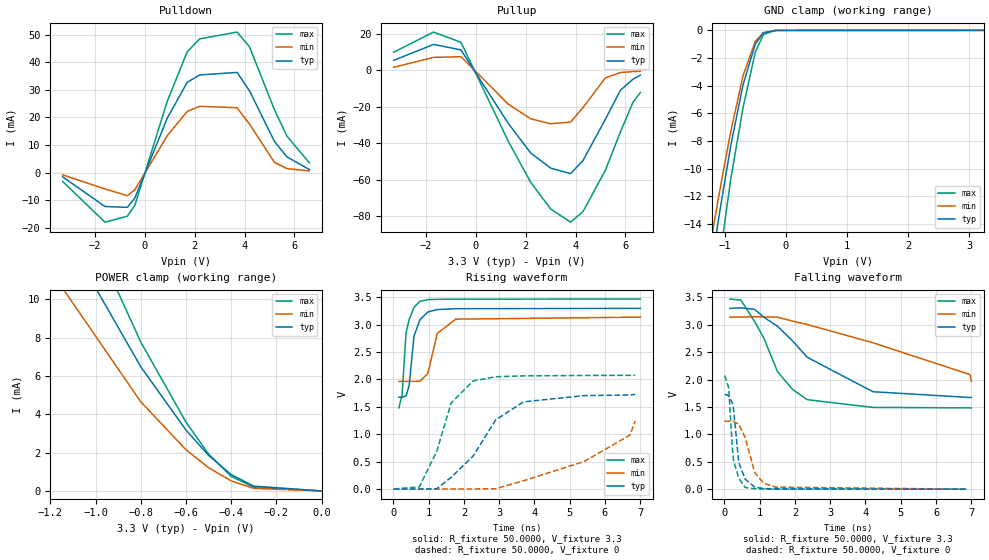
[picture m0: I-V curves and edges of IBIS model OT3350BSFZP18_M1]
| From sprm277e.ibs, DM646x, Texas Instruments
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|   Model Cell OT3350BSFZP18_M1
[Model]   OT3350BSFZP18_M1
Model_type   3-state
Polarity   Non-Inverting
Enable   Active-Low
Cref =  10.0000pF
Rref =  50.0000
Vref =  1.5V
Vmeas =  1.65
C_comp   1.572001p   1.534735p   1.612261p
[Temperature Range]   25   125   -40
[Voltage Range]   3.3   3.14   3.47
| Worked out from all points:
|   slope of the pulldown table from 0 to 0.495 V, typ, clamps not added: 44 ohm
|   slope of the pullup table from 0 to 0.495 V, typ, clamps not added: 42.8 ohm
|   GND clamp passes 1 mA (typ) near -0.50 V on its own axis
|   POWER clamp passes 1 mA (typ) near -0.41 V on its own axis
|   rising waveform, R_fixture 50.0000, V_fixture 3.3: 20-80 % time 213ps typ, 304ps min, 172ps max; typ from 1.68 V to 3.3 V
|   rising waveform, R_fixture 50.0000, V_fixture 0: 20-80 % time 1.22ns typ, 2.5ns min, 683ps max; typ from 0 V to 1.73 V
|   falling waveform, R_fixture 50.0000, V_fixture 3.3: 20-80 % time 1.87ns typ, 3.44ns min, 1ns max; typ from 3.3 V to 1.68 V
|   falling waveform, R_fixture 50.0000, V_fixture 0: 20-80 % time 194ps typ, 355ps min, 156ps max; typ from 1.73 V to 0 V
[POWER_clamp]
|   voltage   I(typ)   I(min)   I(max)
-3.3V     74.53mA    56.57mA    89.78mA
-1.433V   20.46mA    16.55mA    24.82mA
-1.3V     17.11mA    13.73mA    21.04mA
-1.267V   16.35mA    13.05mA    20.1mA
-1.167V   14.08mA    11.02mA    17.33mA
-1.133V   13.35mA    10.37mA    16.41mA
-800mV    6.485mA    4.657mA    7.776mA
-600mV    3.177mA    2.148mA    3.593mA
-500mV    1.856mA    1.211mA    1.925mA
-400mV    849.6uA    522.3uA    759.5uA
-300mV    251.9uA    131.4uA    193.7uA
0V        16.41nA    108.8nA    12.28nA
[Pulldown]
|   voltage   I(typ)   I(min)   I(max)
-3.3V     -1.51mA    -788.1uA   -3.172mA
-1.6V     -12.28mA   -5.921mA   -17.96mA
-700mV    -12.58mA   -8.354mA   -15.76mA
-400mV    -9.19mA    -6.205mA   -11.82mA
900mV     19.74mA    13.39mA    25.89mA
1.7V      32.7mA     22.18mA    43.75mA
2.2V      35.39mA    24.02mA    48.45mA
3.7V      36.3mA     23.5mA     50.91mA
4.2V      29.63mA    17.57mA    45.56mA
5.2V      11.29mA    3.714mA    22.78mA
5.7V      5.726mA    1.466mA    13.23mA
6.6V      1.128mA    616.4uA    3.561mA
[Pullup]
|   voltage   I(typ)   I(min)   I(max)
-3.3V     5.393mA    1.592mA    9.843mA
-1.7V     14.11mA    7.029mA    20.87mA
-600mV    11.14mA    7.391mA    15.31mA
1.3V      -29.12mA   -18.58mA   -38.91mA
2.2V      -45.34mA   -26.59mA   -61.37mA
3V        -53.59mA   -29.28mA   -75.95mA
3.8V      -56.59mA   -28.41mA   -83.18mA
4.3V      -49.39mA   -20.38mA   -77.34mA
5.2V      -26.73mA   -4.173mA   -54.61mA
5.8V      -10.97mA   -1.259mA   -33.76mA
6.3V      -4.966mA   -742.7uA   -17.66mA
6.6V      -2.645mA   -590.8uA   -12.2mA
[GND_clamp]
|   voltage   I(typ)   I(min)   I(max)
-3.3V     -90.23mA   -69.54mA   -106.7mA
-1.3V     -19.77mA   -17.25mA   -23.98mA
-1.233V   -17.66mA   -15.52mA   -21.71mA
-1.167V   -15.64mA   -13.82mA   -19.46mA
-1.1V     -13.7mA    -12.13mA   -17.22mA
-1.033V   -11.88mA   -10.49mA   -15.02mA
-900mV    -8.367mA   -7.333mA   -10.78mA
-700mV    -3.963mA   -3.298mA   -5.618mA
-500mV    -1.004mA   -795uA     -1.595mA
-366.7mV  -172.3uA   -169.8uA   -300.1uA
-166.7mV  -4.07uA    -5.868uA   -4.352uA
3.233V    -14.17nA   2.341uA    -4.987nA
[Ramp]
| variable   typ   min   max
dV/dt_f 0.98724982/1.8960587n 0.74672772/3.6648793n  1.2049754/1.0118265n
dV/dt_r  1.0419101/1.2255453n 0.75526862/2.586802n   1.2522241/0.68406712n
R_load = 50
[Rising Waveform]
R_fixture = 50.0000
V_fixture = 3.3
V_fixture_min = 3.14
V_fixture_max = 3.47
|   time   V(typ)   V(min)   V(max)
154.7ps   1.676V     1.965V     1.481V
246.4ps   1.676V     1.965V     1.72V
361ps     1.701V     1.965V     2.86V
446.2ps   1.888V     1.965V     3.091V
585.4ps   2.794V     1.965V     3.319V
753.4ps   3.091V     1.969V     3.43V
977.6ps   3.234V     2.113V     3.46V
1.246ns   3.278V     2.843V     3.465V
1.77ns    3.294V     3.103V     3.468V
7.004ns   3.3V       3.14V      3.47V
[Rising Waveform]
R_fixture = 50.0000
V_fixture = 0
V_fixture_min = 0
V_fixture_max = 0
|   time   V(typ)   V(min)   V(max)
7.721ps   17.64uV    18.18uV    16.31uV
735.2ps   -3.241mV   -217.3uV   36.72mV
1.232ns   3.646mV    -4.209mV   691.5mV
1.637ns   211.3mV    -761.9uV   1.57V
2.257ns   597.8mV    27.08uV    1.973V
2.902ns   1.262V     4.187mV    2.05V
3.685ns   1.591V     148.1mV    2.066V
5.407ns   1.706V     501mV      2.074V
6.708ns   1.717V     983.5mV    2.076V
6.857ns   1.728V     1.24V      2.077V
[Falling Waveform]
R_fixture = 50.0000
V_fixture = 3.3
V_fixture_min = 3.14
V_fixture_max = 3.47
|   time   V(typ)   V(min)   V(max)
154.7ps   3.3V       3.14V      3.47V
468ps     3.31V      3.142V     3.452V
855.3ps   3.283V     3.148V     3.06V
1.116ns   3.139V     3.144V     2.76V
1.506ns   2.974V     3.14V      2.144V
1.933ns   2.706V     3.069V     1.82V
2.347ns   2.408V     3.006V     1.634V
4.209ns   1.779V     2.673V     1.492V
6.963ns   1.673V     2.092V     1.484V
7.004ns   1.676V     1.965V     1.481V
[Falling Waveform]
R_fixture = 50.0000
V_fixture = 0
V_fixture_min = 0
V_fixture_max = 0
|   time   V(typ)   V(min)   V(max)
7.721ps   1.728V     1.24V      2.077V
119.9ps   1.709V     1.242V     1.853V
227.9ps   1.567V     1.236V     727.9mV
260.8ps   1.449V     1.232V     513.4mV
405.8ps   485.8mV    1.186V     202.5mV
586.9ps   183.8mV    943.9mV    30.86mV
859.3ps   36.4mV     304.4mV    6.842mV
1.115ns   10.48mV    105.5mV    3.827mV
1.45ns    5.056mV    36.54mV    2.037mV
6.857ns   17.64uV    18.18uV    16.31uV
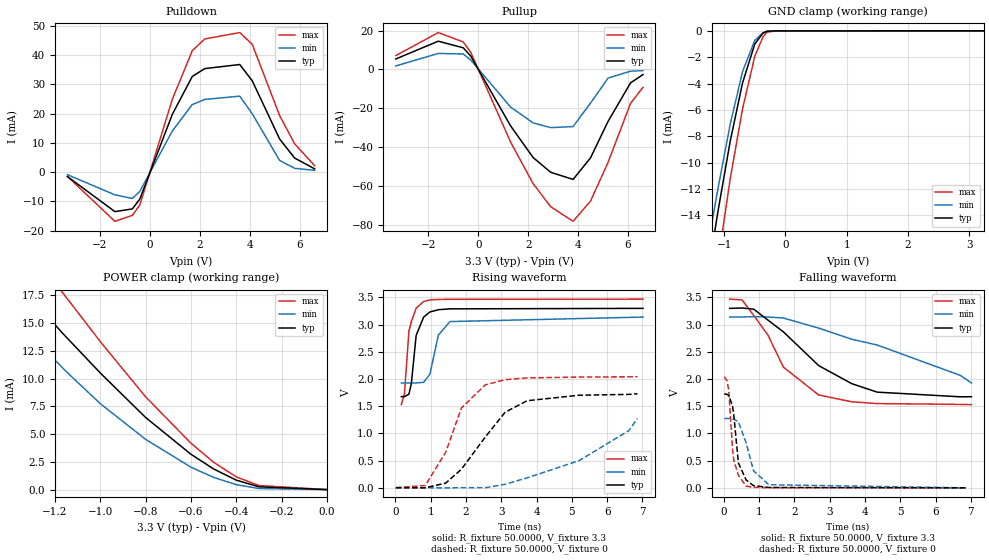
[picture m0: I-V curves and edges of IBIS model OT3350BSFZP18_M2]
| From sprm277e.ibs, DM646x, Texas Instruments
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|   Model Cell OT3350BSFZP18_M2
[Model]   OT3350BSFZP18_M2
Model_type   3-state
Polarity   Non-Inverting
Enable   Active-Low
Cref =  10.0000pF
Rref =  50.0000
Vref =  1.5V
Vmeas =  1.65
C_comp   1.572001p   1.536489p   1.612727p
[Temperature Range]   25   105   0
[Voltage Range]   3.3   3.14   3.47
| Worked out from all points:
|   slope of the pulldown table from 0 to 0.495 V, typ, clamps not added: 44 ohm
|   slope of the pullup table from 0 to 0.495 V, typ, clamps not added: 42.8 ohm
|   GND clamp passes 1 mA (typ) near -0.50 V on its own axis
|   POWER clamp passes 1 mA (typ) near -0.41 V on its own axis
|   rising waveform, R_fixture 50.0000, V_fixture 3.3: 20-80 % time 214ps typ, 298ps min, 179ps max; typ from 1.68 V to 3.3 V
|   rising waveform, R_fixture 50.0000, V_fixture 0: 20-80 % time 1.22ns typ, 2.38ns min, 839ps max; typ from 0 V to 1.73 V
|   falling waveform, R_fixture 50.0000, V_fixture 3.3: 20-80 % time 1.87ns typ, 3.34ns min, 1.22ns max; typ from 3.3 V to 1.68 V
|   falling waveform, R_fixture 50.0000, V_fixture 0: 20-80 % time 194ps typ, 346ps min, 161ps max; typ from 1.73 V to 0 V
[POWER_clamp]
|   voltage   I(typ)   I(min)   I(max)
-3.3V     74.53mA    58.44mA    90.4mA
-1.467V   21.35mA    17.44mA    26.25mA
-1.3V     17.11mA    13.76mA    21.37mA
-1.167V   14.08mA    10.96mA    17.73mA
-1.133V   13.35mA    10.28mA    16.84mA
-1V       10.49mA    7.728mA    13.31mA
-800mV    6.485mA    4.517mA    8.34mA
-600mV    3.177mA    2.014mA    4.17mA
-500mV    1.856mA    1.101mA    2.456mA
-400mV    849.6uA    442uA      1.145mA
-300mV    251.9uA    97.53uA    367uA
0V        16.41nA    55.85nA    72.83nA
[Pulldown]
|   voltage   I(typ)   I(min)   I(max)
-3.3V     -1.51mA    -878.2uA   -1.476mA
-1.4V     -13.5mA    -7.755mA   -16.81mA
-700mV    -12.58mA   -9.013mA   -14.79mA
-400mV    -9.19mA    -6.568mA   -11.22mA
900mV     19.74mA    14.05mA    24.87mA
1.7V      32.7mA     23.1mA     41.52mA
2.2V      35.39mA    24.85mA    45.53mA
3.6V      36.79mA    25.98mA    47.71mA
4.1V      31.26mA    19.99mA    43.72mA
5.2V      11.29mA    3.969mA    19.31mA
5.8V      4.813mA    1.297mA    9.683mA
6.6V      1.128mA    609.9uA    2.211mA
[Pullup]
|   voltage   I(typ)   I(min)   I(max)
-3.3V     5.393mA    1.811mA    7.122mA
-1.6V     14.53mA    8.235mA    18.97mA
-600mV    11.14mA    7.955mA    14.14mA
-300mV    6.902mA    4.842mA    8.811mA
1.3V      -29.12mA   -19.41mA   -37.45mA
2.2V      -45.34mA   -27.5mA    -58.77mA
2.9V      -52.91mA   -29.94mA   -70.62mA
3.8V      -56.6mA    -29.4mA    -78.14mA
4.5V      -45.46mA   -17.28mA   -67.69mA
5.2V      -26.74mA   -4.471mA   -47.86mA
6.1V      -6.932mA   -894.8uA   -17.48mA
6.6V      -2.646mA   -584.9uA   -9.171mA
[GND_clamp]
|   voltage   I(typ)   I(min)   I(max)
-3.3V     -90.23mA   -71.94mA   -107.2mA
-1.3V     -19.77mA   -17.29mA   -24.19mA
-1.233V   -17.66mA   -15.5mA    -21.92mA
-1.167V   -15.64mA   -13.72mA   -19.69mA
-1.1V     -13.7mA    -11.97mA   -17.51mA
-900mV    -8.367mA   -7.078mA   -11.22mA
-700mV    -3.963mA   -3.105mA   -5.94mA
-500mV    -1.004mA   -722.3uA   -1.938mA
-366.7mV  -172.3uA   -139.7uA   -459.5uA
-300mV    -29.29uA   -31.64uA   -98.99uA
-166.7mV  -4.07uA    -4.547uA   -8.038uA
3.233V    -14.17nA   1.379uA    -35.45nA
[Ramp]
| variable   typ   min   max
dV/dt_f 0.98720445/1.8960218n 0.76974528/3.5435312n  1.1762202/1.2302817n
dV/dt_r  1.0419147/1.2256014n 0.77656358/2.4398442n  1.2316503/0.84566068n
R_load = 50
[Rising Waveform]
R_fixture = 50.0000
V_fixture = 3.3
V_fixture_min = 3.14
V_fixture_max = 3.47
|   time   V(typ)   V(min)   V(max)
166.2ps   1.676V     1.928V     1.53V
254.6ps   1.676V     1.928V     1.725V
380.8ps   1.72V      1.928V     2.877V
449.7ps   1.914V     1.928V     3.056V
586.5ps   2.802V     1.928V     3.303V
799.5ps   3.14V      1.94V      3.428V
976.7ps   3.234V     2.089V     3.456V
1.215ns   3.275V     2.806V     3.464V
1.543ns   3.291V     3.057V     3.467V
7.016ns   3.3V       3.14V      3.47V
[Rising Waveform]
R_fixture = 50.0000
V_fixture = 0
V_fixture_min = 0
V_fixture_max = 0
|   time   V(typ)   V(min)   V(max)
9.825ps   17.64uV    17.19uV    19.99uV
845.7ps   -1.348mV   -619.3uV   41.44mV
1.426ns   85.32mV    -2.768mV   655.9mV
1.869ns   339.9mV    -104uV     1.467V
2.549ns   935.6mV    293.7uV    1.894V
3.107ns   1.388V     62.56mV    1.988V
3.729ns   1.6V       180.4mV    2.021V
5.208ns   1.702V     499mV      2.036V
6.617ns   1.717V     1.053V     2.04V
6.859ns   1.728V     1.275V     2.043V
[Falling Waveform]
R_fixture = 50.0000
V_fixture = 3.3
V_fixture_min = 3.14
V_fixture_max = 3.47
|   time   V(typ)   V(min)   V(max)
166.2ps   3.3V       3.14V      3.47V
514.7ps   3.307V     3.142V     3.456V
847.5ps   3.285V     3.148V     3.171V
1.246ns   3.086V     3.142V     2.813V
1.69ns    2.867V     3.122V     2.218V
2.688ns   2.248V     2.937V     1.708V
3.627ns   1.915V     2.732V     1.582V
4.344ns   1.76V      2.627V     1.55V
6.705ns   1.674V     2.067V     1.534V
7.016ns   1.676V     1.928V     1.53V
[Falling Waveform]
R_fixture = 50.0000
V_fixture = 0
V_fixture_min = 0
V_fixture_max = 0
|   time   V(typ)   V(min)   V(max)
9.825ps   1.728V     1.275V     2.043V
89.82ps   1.719V     1.276V     1.971V
137.7ps   1.699V     1.276V     1.8V
245.6ps   1.507V     1.268V     723.3mV
280.7ps   1.348V     1.263V     510.3mV
412.6ps   457.7mV    1.214V     229mV
632.7ps   144.3mV    826.8mV    31.95mV
839.3ps   41.36mV    315.6mV    9.29mV
1.275ns   6.978mV    57.45mV    3.368mV
6.859ns   17.64uV    17.19uV    19.99uV
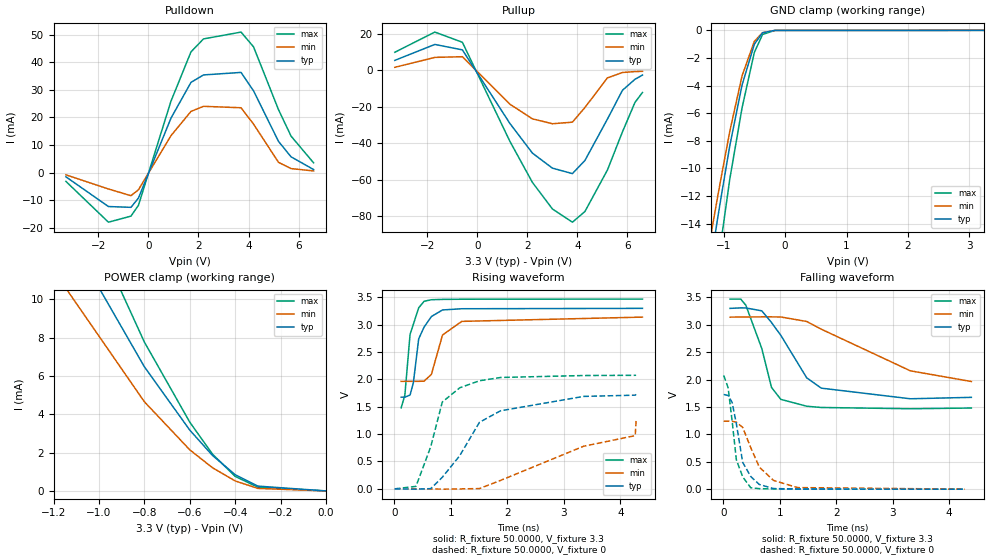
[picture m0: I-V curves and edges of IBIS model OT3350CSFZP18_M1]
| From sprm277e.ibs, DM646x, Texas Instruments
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|   Model Cell OT3350CSFZP18_M1
[Model]   OT3350CSFZP18_M1
Model_type   3-state
Polarity   Non-Inverting
Enable   Active-Low
Cref =  10.0000pF
Rref =  50.0000
Vref =  1.5V
Vmeas =  1.65
C_comp   1.576969p   1.539569p   1.618479p
[Temperature Range]   25   125   -40
[Voltage Range]   3.3   3.14   3.47
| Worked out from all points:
|   slope of the pulldown table from 0 to 0.495 V, typ, clamps not added: 44 ohm
|   slope of the pullup table from 0 to 0.495 V, typ, clamps not added: 42.8 ohm
|   GND clamp passes 1 mA (typ) near -0.50 V on its own axis
|   POWER clamp passes 1 mA (typ) near -0.42 V on its own axis
|   rising waveform, R_fixture 50.0000, V_fixture 3.3: 20-80 % time 191ps typ, 257ps min, 152ps max; typ from 1.68 V to 3.3 V
|   rising waveform, R_fixture 50.0000, V_fixture 0: 20-80 % time 816ps typ, 2.14ns min, 367ps max; typ from 0 V to 1.73 V
|   falling waveform, R_fixture 50.0000, V_fixture 3.3: 20-80 % time 603ps typ, 1.45ns min, 337ps max; typ from 3.3 V to 1.68 V
|   falling waveform, R_fixture 50.0000, V_fixture 0: 20-80 % time 211ps typ, 384ps min, 162ps max; typ from 1.73 V to 0 V
[POWER_clamp]
|   voltage   I(typ)   I(min)   I(max)
-3.3V     74.53mA    56.57mA    89.78mA
-1.433V   20.46mA    16.55mA    24.82mA
-1.3V     17.11mA    13.73mA    21.03mA
-1.267V   16.34mA    13.04mA    20.1mA
-1.167V   14.08mA    11.02mA    17.32mA
-1.133V   13.35mA    10.36mA    16.41mA
-800mV    6.483mA    4.656mA    7.774mA
-600mV    3.176mA    2.147mA    3.592mA
-500mV    1.855mA    1.211mA    1.924mA
-400mV    849.1uA    522uA      759.1uA
-300mV    251.7uA    131.3uA    193.5uA
0V        16.5nA     109.4nA    12.34nA
[Pulldown]
|   voltage   I(typ)   I(min)   I(max)
-3.3V     -1.51mA    -788.4uA   -3.171mA
-1.6V     -12.28mA   -5.922mA   -17.95mA
-700mV    -12.57mA   -8.353mA   -15.75mA
-400mV    -9.189mA   -6.204mA   -11.82mA
900mV     19.74mA    13.39mA    25.89mA
1.7V      32.7mA     22.18mA    43.75mA
2.2V      35.39mA    24.02mA    48.44mA
3.7V      36.3mA     23.5mA     50.91mA
4.2V      29.63mA    17.58mA    45.56mA
5.2V      11.29mA    3.713mA    22.78mA
5.7V      5.724mA    1.465mA    13.23mA
6.6V      1.128mA    616.3uA    3.557mA
[Pullup]
|   voltage   I(typ)   I(min)   I(max)
-3.3V     5.39mA     1.593mA    9.838mA
-1.7V     14.11mA    7.031mA    20.87mA
-600mV    11.14mA    7.392mA    15.31mA
1.3V      -29.12mA   -18.58mA   -38.9mA
2.2V      -45.34mA   -26.6mA    -61.37mA
3V        -53.58mA   -29.29mA   -75.93mA
3.8V      -56.58mA   -28.42mA   -83.16mA
4.3V      -49.38mA   -20.4mA    -77.31mA
5.2V      -26.72mA   -4.185mA   -54.58mA
5.8V      -10.97mA   -1.26mA    -33.73mA
6.3V      -4.964mA   -743.2uA   -17.63mA
6.6V      -2.644mA   -591.2uA   -12.19mA
[GND_clamp]
|   voltage   I(typ)   I(min)   I(max)
-3.3V     -90.23mA   -69.54mA   -106.7mA
-1.3V     -19.77mA   -17.25mA   -23.98mA
-1.233V   -17.67mA   -15.52mA   -21.71mA
-1.167V   -15.64mA   -13.82mA   -19.46mA
-1.1V     -13.7mA    -12.13mA   -17.22mA
-1.033V   -11.88mA   -10.49mA   -15.02mA
-900mV    -8.37mA    -7.333mA   -10.79mA
-700mV    -3.966mA   -3.299mA   -5.622mA
-500mV    -1.006mA   -796.4uA   -1.598mA
-366.7mV  -173uA     -170.3uA   -301.1uA
-166.7mV  -4.076uA   -5.883uA   -4.359uA
3.233V    -14.06nA   2.34uA     -4.925nA
[Ramp]
| variable   typ   min   max
dV/dt_f  1.0006538/0.62466985n 0.75696727/1.6005346n  1.2087299/0.34128744n
dV/dt_r  1.0444184/0.82282261n 0.76139901/2.3322071n  1.2536569/0.3680679n
R_load = 50
[Rising Waveform]
R_fixture = 50.0000
V_fixture = 3.3
V_fixture_min = 3.14
V_fixture_max = 3.47
|   time   V(typ)   V(min)   V(max)
118.2ps   1.676V     1.965V     1.481V
183.3ps   1.676V     1.966V     1.712V
275.6ps   1.715V     1.966V     2.824V
333.8ps   1.938V     1.966V     3.008V
428.6ps   2.743V     1.966V     3.31V
524.8ps   2.959V     1.969V     3.43V
654.3ps   3.151V     2.095V     3.458V
850.5ps   3.271V     2.813V     3.464V
1.192ns   3.293V     3.062V     3.467V
4.392ns   3.3V       3.14V      3.47V
[Rising Waveform]
R_fixture = 50.0000
V_fixture = 0
V_fixture_min = 0
V_fixture_max = 0
|   time   V(typ)   V(min)   V(max)
5.451ps   17.63uV    18.18uV    16.31uV
379.7ps   -5.915mV   23.15uV    45.1mV
642.4ps   3.522mV    -1.399mV   772.1mV
846.5ps   211mV      -5.73mV    1.587V
1.156ns   607.3mV    -1.443mV   1.848V
1.505ns   1.217V     5.222mV    1.976V
1.878ns   1.427V     154.2mV    2.036V
3.348ns   1.69V      778.1mV    2.072V
4.264ns   1.713V     973.4mV    2.076V
4.279ns   1.728V     1.241V     2.077V
[Falling Waveform]
R_fixture = 50.0000
V_fixture = 3.3
V_fixture_min = 3.14
V_fixture_max = 3.47
|   time   V(typ)   V(min)   V(max)
118.2ps   3.3V       3.14V      3.47V
307.1ps   3.309V     3.143V     3.47V
397.1ps   3.308V     3.143V     3.358V
680.9ps   3.255V     3.145V     2.565V
852.4ps   3.041V     3.145V     1.857V
1.017ns   2.808V     3.143V     1.639V
1.476ns   2.032V     3.061V     1.514V
1.734ns   1.844V     2.92V      1.491V
3.312ns   1.65V      2.16V      1.468V
4.392ns   1.676V     1.965V     1.481V
[Falling Waveform]
R_fixture = 50.0000
V_fixture = 0
V_fixture_min = 0
V_fixture_max = 0
|   time   V(typ)   V(min)   V(max)
5.451ps   1.728V     1.241V     2.077V
83.83ps   1.71V      1.242V     1.852V
154.7ps   1.583V     1.239V     1.245V
230ps     1.191V     1.223V     533.4mV
342.5ps   488.1mV    1.126V     224.4mV
484.5ps   230.3mV    757.5mV    25.32mV
636.5ps   85.26mV    402.4mV    9.164mV
888.3ps   10.9mV     160mV      4.276mV
1.311ns   4.014mV    28.82mV    1.939mV
4.279ns   17.63uV    18.18uV    16.31uV
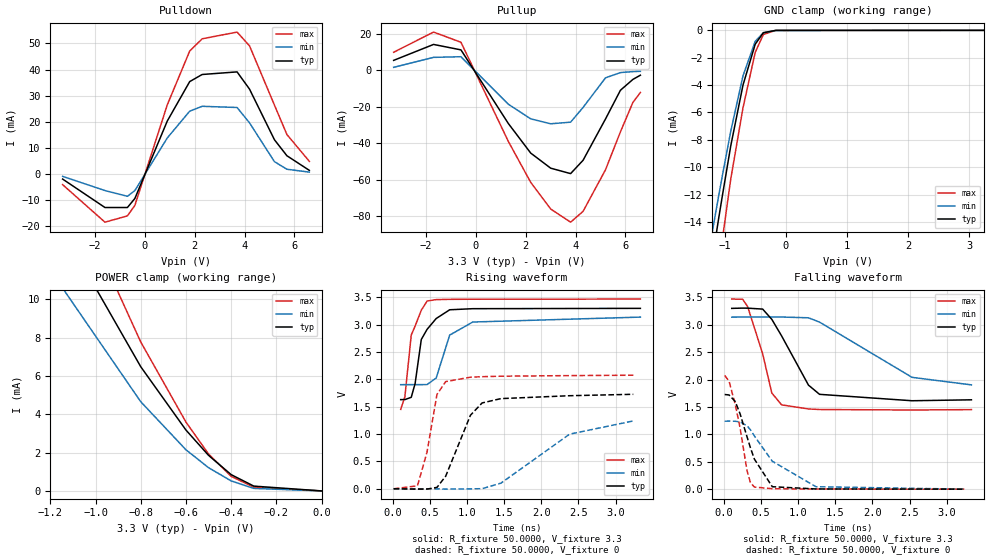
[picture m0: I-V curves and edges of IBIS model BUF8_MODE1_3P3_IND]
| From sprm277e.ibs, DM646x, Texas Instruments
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|   Model Cell BUF8_MODE1_3P3_IND
[Model]   BUF8_MODE1_3P3_IND
Model_type   I/O
Polarity   Non-Inverting
Enable   Active-Low
Vinl =  0.8V
Vinh =  2V
Cref =  10.0000pF
Rref =  50.0000
Vref =  1.5V
Vmeas =  1.65
C_comp   2.460431p   2.393507p   2.515096p
[Model Spec]
Vinl   0.8V   0.8V   0.8V
Vinh   2V   2V   2V
[Temperature Range]   25   125   -40
[Voltage Range]   3.3   3.14   3.47
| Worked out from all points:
|   slope of the pulldown table from 0 to 0.495 V, typ, clamps not added: 42.9 ohm
|   slope of the pullup table from 0 to 0.495 V, typ, clamps not added: 42.8 ohm
|   GND clamp passes 1 mA (typ) near -0.50 V on its own axis
|   POWER clamp passes 1 mA (typ) near -0.42 V on its own axis
|   rising waveform, R_fixture 50.0000, V_fixture 3.3: 20-80 % time 183ps typ, 230ps min, 149ps max; typ from 1.63 V to 3.3 V
|   rising waveform, R_fixture 50.0000, V_fixture 0: 20-80 % time 306ps typ, 764ps min, 166ps max; typ from 0 V to 1.73 V
|   falling waveform, R_fixture 50.0000, V_fixture 3.3: 20-80 % time 405ps typ, 903ps min, 236ps max; typ from 3.3 V to 1.63 V
|   falling waveform, R_fixture 50.0000, V_fixture 0: 20-80 % time 270ps typ, 549ps min, 167ps max; typ from 1.73 V to 0 V
[POWER_clamp]
|   voltage   I(typ)   I(min)   I(max)
-3.3V     74.53mA    56.57mA    89.78mA
-1.433V   20.46mA    16.55mA    24.82mA
-1.3V     17.11mA    13.73mA    21.03mA
-1.267V   16.34mA    13.05mA    20.1mA
-1.167V   14.08mA    11.02mA    17.32mA
-1.133V   13.35mA    10.37mA    16.41mA
-800mV    6.483mA    4.656mA    7.774mA
-600mV    3.176mA    2.147mA    3.592mA
-500mV    1.855mA    1.211mA    1.924mA
-400mV    849.1uA    522uA      759.1uA
-300mV    251.7uA    131.3uA    193.5uA
0V        16.6nA     109.7nA    12.43nA
[Pulldown]
|   voltage   I(typ)   I(min)   I(max)
-3.3V     -1.941mA   -916.8uA   -4.083mA
-1.6V     -12.84mA   -6.343mA   -18.46mA
-700mV    -12.84mA   -8.55mA    -16.04mA
-400mV    -9.372mA   -6.338mA   -12.02mA
900mV     20.28mA    13.8mA     26.48mA
1.8V      35.39mA    24.06mA    47.09mA
2.3V      38.1mA     25.92mA    51.77mA
3.7V      39.1mA     25.46mA    54.34mA
4.2V      32.5mA     19.58mA    49.07mA
5.2V      13.11mA    4.724mA    26.38mA
5.7V      6.988mA    1.815mA    15.11mA
6.6V      1.391mA    706.7uA    4.843mA
[Pullup]
|   voltage   I(typ)   I(min)   I(max)
-3.3V     5.391mA    1.594mA    9.838mA
-1.7V     14.11mA    7.033mA    20.87mA
-600mV    11.14mA    7.393mA    15.31mA
1.3V      -29.12mA   -18.59mA   -38.9mA
2.2V      -45.34mA   -26.61mA   -61.37mA
3V        -53.59mA   -29.31mA   -75.93mA
3.8V      -56.58mA   -28.42mA   -83.16mA
4.3V      -49.29mA   -20.38mA   -77.24mA
5.2V      -26.7mA    -4.184mA   -54.5mA
5.8V      -10.96mA   -1.28mA    -33.71mA
6.3V      -5.024mA   -754.6uA   -17.62mA
6.6V      -2.725mA   -599.7uA   -12.2mA
[GND_clamp]
|   voltage   I(typ)   I(min)   I(max)
-3.3V     -90.24mA   -69.55mA   -106.7mA
-1.3V     -19.87mA   -17.28mA   -24.17mA
-1.233V   -17.77mA   -15.56mA   -21.89mA
-1.167V   -15.76mA   -13.86mA   -19.62mA
-1.1V     -13.82mA   -12.17mA   -17.37mA
-1.033V   -11.99mA   -10.53mA   -15.15mA
-900mV    -8.449mA   -7.377mA   -10.88mA
-700mV    -4.003mA   -3.328mA   -5.669mA
-500mV    -1.011mA   -801.3uA   -1.606mA
-366.7mV  -173.1uA   -170.6uA   -301.5uA
-166.7mV  -4.073uA   -5.876uA   -4.355uA
3.233V    -13.96nA   2.341uA    -4.843nA
[Ramp]
| variable   typ   min   max
dV/dt_f  1.0170833/0.41203484n 0.77592472/0.95286006n  1.2189112/0.23596202n
dV/dt_r  1.0441636/0.30795697n 0.75930148/0.7844658n  1.2538393/0.16647245n
R_load = 50
[Rising Waveform]
R_fixture = 50.0000
V_fixture = 3.3
V_fixture_min = 3.14
V_fixture_max = 3.47
|   time   V(typ)   V(min)   V(max)
107.3ps   1.631V     1.904V     1.452V
163.3ps   1.631V     1.905V     1.681V
249.2ps   1.673V     1.905V     2.811V
301.5ps   1.927V     1.905V     2.977V
384.4ps   2.731V     1.905V     3.266V
462.8ps   2.917V     1.906V     3.434V
584.8ps   3.114V     2.026V     3.46V
766.7ps   3.274V     2.811V     3.465V
1.077ns   3.294V     3.05V      3.467V
3.333ns   3.3V       3.14V      3.47V
[Rising Waveform]
R_fixture = 50.0000
V_fixture = 0
V_fixture_min = 0
V_fixture_max = 0
|   time   V(typ)   V(min)   V(max)
12.41ps   16.5uV     16.96uV    15.38uV
332.6ps   -7.409mV   25.99uV    54.8mV
460.8ps   -5.909mV   -285uV     666.3mV
595.4ps   25.16mV    -1.753mV   1.725V
712.8ps   230.1mV    -6.03mV    1.96V
1.046ns   1.345V     -1.696mV   2.041V
1.203ns   1.57V      1.416mV    2.05V
1.456ns   1.649V     102.9mV    2.059V
2.381ns   1.702V     998.9mV    2.07V
3.238ns   1.728V     1.241V     2.077V
[Falling Waveform]
R_fixture = 50.0000
V_fixture = 3.3
V_fixture_min = 3.14
V_fixture_max = 3.47
|   time   V(typ)   V(min)   V(max)
107.3ps   3.3V       3.14V      3.47V
253.9ps   3.305V     3.142V     3.467V
321.1ps   3.304V     3.143V     3.332V
523.1ps   3.287V     3.143V     2.473V
646.3ps   3.1V       3.143V     1.756V
778.5ps   2.797V     3.142V     1.539V
1.14ns    1.899V     3.128V     1.464V
1.289ns   1.731V     3.049V     1.454V
2.534ns   1.614V     2.041V     1.445V
3.333ns   1.631V     1.904V     1.452V
[Falling Waveform]
R_fixture = 50.0000
V_fixture = 0
V_fixture_min = 0
V_fixture_max = 0
|   time   V(typ)   V(min)   V(max)
12.41ps   1.728V     1.241V     2.077V
71.69ps   1.719V     1.242V     1.968V
153.9ps   1.601V     1.24V      1.551V
220.1ps   1.373V     1.226V     1.113V
313.3ps   954.1mV    1.157V     335.4mV
359.5ps   752.2mV    1.083V     117.7mV
412.5ps   547.5mV    970.2mV    38.94mV
653.1ps   44.62mV    509.8mV    7.856mV
1.24ns    4.087mV    44.7mV     2.163mV
3.238ns   16.5uV     16.96uV    15.38uV
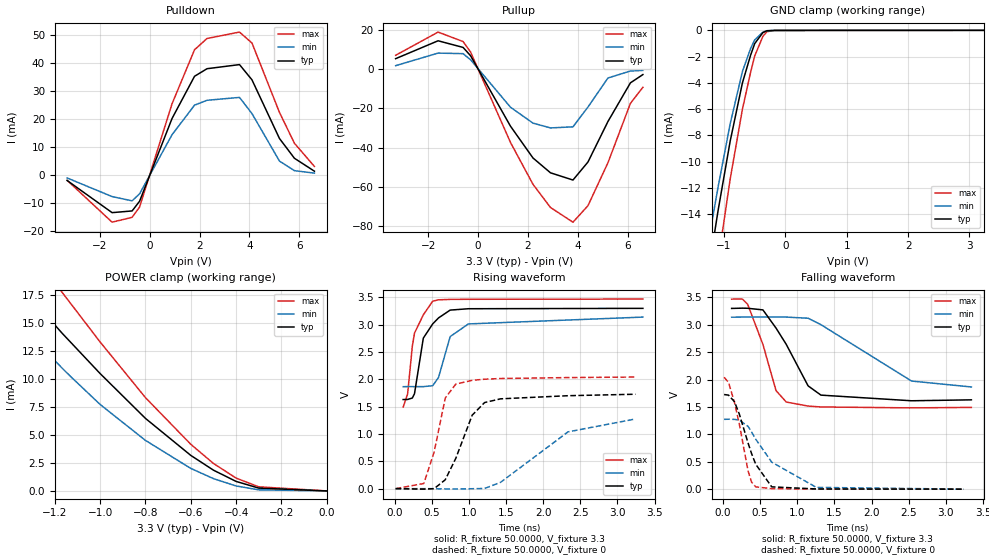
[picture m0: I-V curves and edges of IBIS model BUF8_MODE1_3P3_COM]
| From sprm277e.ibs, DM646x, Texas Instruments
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|   Model Cell BUF8_MODE1_3P3_COM
[Model]   BUF8_MODE1_3P3_COM
Model_type   I/O
Polarity   Non-Inverting
Enable   Active-Low
Vinl =  0.8V
Vinh =  2V
Cref =  10.0000pF
Rref =  50.0000
Vref =  1.5V
Vmeas =  1.65
C_comp   2.460431p   2.38871p   2.515471p
[Model Spec]
Vinl   0.8V   0.8V   0.8V
Vinh   2V   2V   2V
[Temperature Range]   25   105   0
[Voltage Range]   3.3   3.14   3.47
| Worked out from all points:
|   slope of the pulldown table from 0 to 0.495 V, typ, clamps not added: 42.9 ohm
|   slope of the pullup table from 0 to 0.495 V, typ, clamps not added: 42.8 ohm
|   GND clamp passes 1 mA (typ) near -0.50 V on its own axis
|   POWER clamp passes 1 mA (typ) near -0.42 V on its own axis
|   rising waveform, R_fixture 50.0000, V_fixture 3.3: 20-80 % time 183ps typ, 225ps min, 158ps max; typ from 1.63 V to 3.3 V
|   rising waveform, R_fixture 50.0000, V_fixture 0: 20-80 % time 305ps typ, 745ps min, 198ps max; typ from 0 V to 1.73 V
|   falling waveform, R_fixture 50.0000, V_fixture 3.3: 20-80 % time 406ps typ, 884ps min, 265ps max; typ from 3.3 V to 1.63 V
|   falling waveform, R_fixture 50.0000, V_fixture 0: 20-80 % time 272ps typ, 530ps min, 179ps max; typ from 1.73 V to 0 V
[POWER_clamp]
|   voltage   I(typ)   I(min)   I(max)
-3.3V     74.53mA    58.44mA    90.4mA
-1.467V   21.35mA    17.44mA    26.25mA
-1.3V     17.11mA    13.76mA    21.37mA
-1.167V   14.08mA    10.96mA    17.73mA
-1.133V   13.35mA    10.28mA    16.83mA
-1V       10.49mA    7.728mA    13.31mA
-800mV    6.483mA    4.516mA    8.338mA
-600mV    3.176mA    2.013mA    4.168mA
-500mV    1.855mA    1.1mA      2.455mA
-400mV    849.1uA    441.8uA    1.144mA
-300mV    251.7uA    97.47uA    366.8uA
0V        16.6nA     56.32nA    74.02nA
[Pulldown]
|   voltage   I(typ)   I(min)   I(max)
-3.3V     -1.941mA   -1.032mA   -1.883mA
-1.5V     -13.45mA   -7.699mA   -16.87mA
-700mV    -12.84mA   -9.218mA   -15.12mA
-400mV    -9.372mA   -6.707mA   -11.45mA
900mV     20.28mA    14.47mA    25.55mA
1.8V      35.39mA    25.05mA    44.9mA
2.3V      38.1mA     26.79mA    48.93mA
3.6V      39.58mA    27.83mA    51.22mA
4.1V      34.11mA    22.03mA    47.31mA
5.2V      13.11mA    5.024mA    22.46mA
5.8V      6.02mA     1.585mA    11.39mA
6.6V      1.391mA    698.9uA    3.093mA
[Pullup]
|   voltage   I(typ)   I(min)   I(max)
-3.3V     5.391mA    1.814mA    7.117mA
-1.6V     14.53mA    8.239mA    18.97mA
-600mV    11.14mA    7.958mA    14.14mA
-300mV    6.902mA    4.843mA    8.81mA
1.3V      -29.12mA   -19.42mA   -37.44mA
2.2V      -45.34mA   -27.53mA   -58.77mA
2.9V      -52.9mA    -29.98mA   -70.61mA
3.8V      -56.59mA   -29.42mA   -78.12mA
4.4V      -47.4mA    -19.32mA   -69.7mA
5.2V      -26.71mA   -4.486mA   -47.77mA
6.1V      -6.958mA   -910.6uA   -17.44mA
6.6V      -2.727mA   -594uA     -9.214mA
[GND_clamp]
|   voltage   I(typ)   I(min)   I(max)
-3.3V     -90.24mA   -71.95mA   -107.2mA
-1.3V     -19.87mA   -17.33mA   -24.39mA
-1.233V   -17.77mA   -15.54mA   -22.12mA
-1.1V     -13.82mA   -12.02mA   -17.69mA
-900mV    -8.449mA   -7.127mA   -11.34mA
-700mV    -4.003mA   -3.134mA   -6.006mA
-566.7mV  -1.892mA   -1.378mA   -3.198mA
-500mV    -1.011mA   -727.7uA   -1.955mA
-366.7mV  -173.1uA   -140.3uA   -462.2uA
-300mV    -29.37uA   -31.71uA   -99.32uA
-166.7mV  -4.073uA   -4.552uA   -8.05uA
3.233V    -13.96nA   1.378uA    -34.27nA
[Ramp]
| variable   typ   min   max
dV/dt_f  1.0170549/0.41210905n 0.79869685/0.93189183n  1.1953839/0.26727273n
dV/dt_r  1.0441698/0.30785682n 0.78040033/0.7652834n  1.2328812/0.19852184n
R_load = 50
[Rising Waveform]
R_fixture = 50.0000
V_fixture = 3.3
V_fixture_min = 3.14
V_fixture_max = 3.47
|   time   V(typ)   V(min)   V(max)
116.3ps   1.631V     1.866V     1.493V
175.7ps   1.632V     1.868V     1.732V
239.8ps   1.659V     1.868V     2.609V
268.9ps   1.738V     1.867V     2.847V
387.4ps   2.755V     1.867V     3.181V
514ps     3.016V     1.884V     3.432V
592.3ps   3.125V     2.036V     3.456V
748.5ps   3.268V     2.783V     3.464V
993.9ps   3.293V     3.015V     3.466V
3.342ns   3.3V       3.14V      3.47V
[Rising Waveform]
R_fixture = 50.0000
V_fixture = 0
V_fixture_min = 0
V_fixture_max = 0
|   time   V(typ)   V(min)   V(max)
14.76ps   16.5uV     16.04uV    18.75uV
394.4ps   -9.513mV   9.865uV    94.61mV
533.2ps   234.9uV    -1.55mV    670.5mV
682.7ps   162.9mV    -4.822mV   1.659V
824.8ps   556.2mV    -6.059mV   1.914V
1.045ns   1.345V     -1.522mV   1.983V
1.212ns   1.576V     3.124mV    2.003V
1.427ns   1.644V     115.8mV    2.016V
2.334ns   1.701V     1.039V     2.033V
3.241ns   1.728V     1.275V     2.043V
[Falling Waveform]
R_fixture = 50.0000
V_fixture = 3.3
V_fixture_min = 3.14
V_fixture_max = 3.47
|   time   V(typ)   V(min)   V(max)
116.3ps   3.3V       3.14V      3.47V
261.5ps   3.305V     3.142V     3.471V
331.5ps   3.303V     3.143V     3.377V
537.3ps   3.273V     3.143V     2.642V
713.5ps   2.941V     3.143V     1.8V
850.9ps   2.644V     3.142V     1.591V
1.145ns   1.886V     3.121V     1.517V
1.318ns   1.717V     3.003V     1.501V
2.537ns   1.614V     1.974V     1.484V
3.342ns   1.631V     1.866V     1.493V
[Falling Waveform]
R_fixture = 50.0000
V_fixture = 0
V_fixture_min = 0
V_fixture_max = 0
|   time   V(typ)   V(min)   V(max)
14.76ps   1.728V     1.275V     2.043V
74.47ps   1.717V     1.277V     1.95V
153.7ps   1.598V     1.274V     1.587V
219.2ps   1.373V     1.26V      1.193V
336.5ps   845mV      1.147V     336.2mV
383.6ps   653.3mV    1.047V     131.3mV
440.3ps   454.7mV    912.5mV    41.94mV
655.6ps   42.15mV    493.1mV    9.116mV
1.256ns   3.984mV    32.44mV    2.373mV
3.241ns   16.5uV     16.04uV    18.75uV
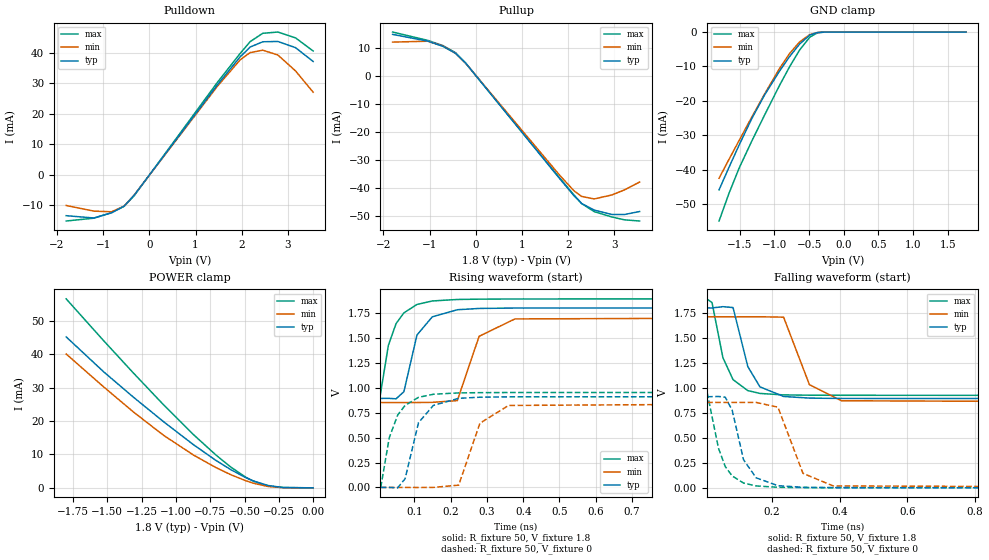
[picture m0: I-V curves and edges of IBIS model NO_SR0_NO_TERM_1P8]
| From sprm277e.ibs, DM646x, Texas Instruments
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|   Model Cell NO_SR0_NO_TERM_1P8
|Driver model in Fast Mode of operation, 1P8V +/-5% Operation
[Model]   NO_SR0_NO_TERM_1P8
Model_type   I/O
Polarity   Non-Inverting
Enable   Active-Low
Cref =  15.0000pF
Rref =  100.0000M
Vref =  0V
Vmeas =  0.9
C_comp   1.4932869p   1.4443092p   1.7624819p
[Temperature Range]   25   125   -40
[Voltage Range]   1.8   1.71   1.89
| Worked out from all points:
|   slope of the pulldown table from 0 to 0.27 V, typ, clamps not added: 48.6 ohm
|   slope of the pullup table from 0 to 0.27 V, typ, clamps not added: 48.6 ohm
|   GND clamp passes 1 mA (typ) near -0.50 V on its own axis
|   POWER clamp passes 1 mA (typ) near -0.36 V on its own axis
|   rising waveform, R_fixture 50, V_fixture 1.8: 20-80 % time 43.1ps typ, 46.9ps min, 43.3ps max; typ from 0.892 V to 1.8 V
|   rising waveform, R_fixture 50, V_fixture 0: 20-80 % time 44.5ps typ, 48ps min, 42.9ps max; typ from 0 V to 0.911 V
|   falling waveform, R_fixture 50, V_fixture 1.8: 20-80 % time 46.3ps typ, 54.9ps min, 44.5ps max; typ from 1.8 V to 0.892 V
|   falling waveform, R_fixture 50, V_fixture 0: 20-80 % time 44.4ps typ, 51.3ps min, 42ps max; typ from 0.911 V to 0 V
[POWER_clamp]
|   voltage   I(typ)   I(min)   I(max)
-1.8V     45.24mA    40.11mA    56.63mA
-1.527V   34.78mA    30.26mA    44.1mA
-1.309V   27.14mA    22.71mA    34.37mA
-1.091V   19.85mA    15.77mA    24.92mA
-872.7mV  12.95mA    9.842mA    15.97mA
-709.1mV  8.24mA     6.092mA    9.863mA
-600mV    5.448mA    3.934mA    6.223mA
-490.9mV  3.058mA    2.131mA    3.184mA
-436.4mV  2.077mA    1.4mA      2.009mA
-327.3mV  690.5uA    396.8uA    556.8uA
-218.2mV  104.2uA    49.84uA    76.16uA
0V        110.7nA    133.6nA    263.4nA
[Pulldown]
|   voltage   I(typ)   I(min)   I(max)
-1.8V     -13.46mA   -10.11mA   -15.21mA
-1.2V     -14.22mA   -11.97mA   -14.28mA
-818.2mV  -12.54mA   -12.18mA   -12.43mA
-545.5mV  -10.33mA   -10.31mA   -10.38mA
-327.3mV  -6.717mA   -6.686mA   -6.887mA
1.473V    29.47mA    29.01mA    30.28mA
1.964V    38.65mA    37.65mA    39.75mA
2.182V    41.88mA    40.06mA    43.65mA
2.455V    43.6mA     40.84mA    46.39mA
2.782V    43.71mA    39.26mA    46.8mA
3.164V    41.67mA    34.04mA    44.88mA
3.545V    37.15mA    27.06mA    40.58mA
[Pullup]
|   voltage   I(typ)   I(min)   I(max)
-1.8V     14.69mA    11.94mA    15.53mA
-1.036V   12.27mA    12.26mA    12.54mA
-709.1mV  10.41mA    10.55mA    10.69mA
-436.4mV  7.93mA     7.944mA    8.142mA
-218.2mV  4.442mA    4.38mA     4.432mA
1.8V      -36.42mA   -35.22mA   -36.18mA
2.127V    -42.84mA   -41.11mA   -42.58mA
2.291V    -45.59mA   -43.06mA   -45.6mA
2.564V    -47.94mA   -43.97mA   -48.49mA
2.945V    -49.5mA    -42.54mA   -50.39mA
3.218V    -49.51mA   -40.74mA   -51.41mA
3.545V    -48.45mA   -37.94mA   -51.83mA
[GND_clamp]
|   voltage   I(typ)   I(min)   I(max)
-1.8V     -45.84mA   -42.45mA   -54.88mA
-1.655V   -39.23mA   -36.93mA   -46.76mA
-1.509V   -32.77mA   -31.45mA   -39.47mA
-1.327V   -25.11mA   -24.68mA   -31.64mA
-1.145V   -18.35mA   -18.07mA   -24.19mA
-927.3mV  -11.35mA   -10.59mA   -15.5mA
-781.8mV  -7.112mA   -6.235mA   -10.08mA
-636.4mV  -3.474mA   -2.848mA   -5.206mA
-490.9mV  -889.6uA   -748.3uA   -1.49mA
-381.8mV  -136uA     -148.6uA   -241.8uA
-272.7mV  -12.55uA   -20.62uA   -15.52uA
1.764V    38.35nA    927.7nA    122.5nA
[Ramp]
| variable   typ   min   max
dV/dt_f 0.56262331/46.464766p 0.53040286/55.820308p  0.5895116/44.586229p
dV/dt_r 0.54880937/43.281411p 0.51671552/47.982861p 0.57488554/42.840774p
R_load = 50
[Rising Waveform]
R_fixture = 50
V_fixture = 1.8
V_fixture_min = 1.71
V_fixture_max = 1.89
|   time   V(typ)   V(min)   V(max)
6.239ps   892.3mV    851.1mV    924.5mV
28.64ps   893.3mV    851.1mV    1.425V
49.79ps   888.6mV    851.1mV    1.642V
71.35ps   959.7mV    851.1mV    1.75V
107.4ps   1.528V     851.2mV    1.834V
149.6ps   1.71V      852.9mV    1.869V
218.5ps   1.781V     870.4mV    1.884V
278.6ps   1.794V     1.515V     1.887V
377.3ps   1.798V     1.689V     1.889V
2.006ns   1.8V       1.71V      1.89V
[Rising Waveform]
R_fixture = 50
V_fixture = 0
V_fixture_min = 0
V_fixture_max = 0
|   time   V(typ)   V(min)   V(max)
7.534ps   42.55uV    30.99uV    50.39uV
30.94ps   302.4uV    31.25uV    497.3mV
54.19ps   -3.889mV   32.3uV     725.4mV
74.62ps   87.27mV    -27.27uV   822.6mV
111.6ps   649.6mV    -266.2uV   903.2mV
152.8ps   823.1mV    644.8uV    934.2mV
222.3ps   893mV      23.24mV    947.6mV
280.7ps   904.6mV    643.7mV    950.1mV
359.8ps   908.3mV    822mV      951.3mV
2.008ns   910.7mV    854.5mV    952.8mV
[Falling Waveform]
R_fixture = 50
V_fixture = 1.8
V_fixture_min = 1.71
V_fixture_max = 1.89
|   time   V(typ)   V(min)   V(max)
6.239ps   1.8V       1.71V      1.89V
21.98ps   1.799V     1.71V      1.853V
54.23ps   1.812V     1.71V      1.302V
84.26ps   1.803V     1.71V      1.082V
127.9ps   1.213V     1.71V      972.7mV
163.9ps   1.01V      1.711V     944.3mV
233.9ps   913.9mV    1.707V     929.6mV
310.3ps   897.4mV    1.032V     926.6mV
405.2ps   894.2mV    871mV      925.7mV
2.006ns   892.3mV    851.1mV    924.5mV
[Falling Waveform]
R_fixture = 50
V_fixture = 0
V_fixture_min = 0
V_fixture_max = 0
|   time   V(typ)   V(min)   V(max)
7.534ps   910.7mV    854.5mV    952.8mV
41.12ps   914mV      854.5mV    396.3mV
61.19ps   906.9mV    854.5mV    212.6mV
81.74ps   775.9mV    854.5mV    118.8mV
115.3ps   281.2mV    854.5mV    47.98mV
152.6ps   100.3mV    854.5mV    19.13mV
217.3ps   21.55mV    806.4mV    5.444mV
291.2ps   5.516mV    145.2mV    2.41mV
380.5ps   2.181mV    19.33mV    1.445mV
2.008ns   42.55uV    30.99uV    50.39uV
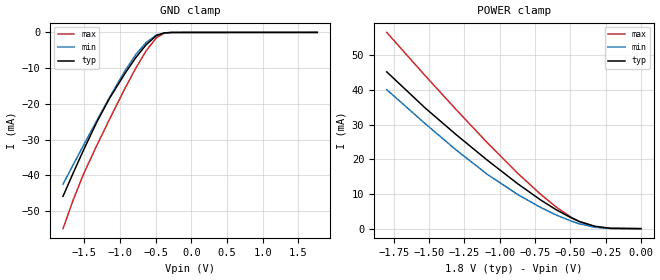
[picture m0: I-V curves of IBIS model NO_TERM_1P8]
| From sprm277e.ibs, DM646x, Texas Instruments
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|   Model Cell NO_TERM_1P8
|Reciever in No Termination Mode , 1P8V +/-5% Operation
[Model]   NO_TERM_1P8
Model_type   Input
Polarity   Non-Inverting
Vinl =  0.8
Vinh =  1
C_comp   1.493287p   1.444309p   1.762482p
[Model Spec]
Vinl   0.8   0.755   0.845
Vinh   1   0.955   1.045
[Temperature Range]   25   125   -40
[Voltage Range]   1.8   1.71   1.89
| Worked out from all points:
|   GND clamp passes 1 mA (typ) near -0.50 V on its own axis
|   POWER clamp passes 1 mA (typ) near -0.36 V on its own axis
[POWER_clamp]
|   voltage   I(typ)   I(min)   I(max)
-1.8V     45.24mA    40.11mA    56.63mA
-1.527V   34.78mA    30.26mA    44.1mA
-1.309V   27.14mA    22.71mA    34.37mA
-1.091V   19.85mA    15.77mA    24.92mA
-872.7mV  12.95mA    9.842mA    15.97mA
-709.1mV  8.24mA     6.092mA    9.863mA
-600mV    5.448mA    3.934mA    6.223mA
-490.9mV  3.058mA    2.131mA    3.184mA
-436.4mV  2.077mA    1.4mA      2.009mA
-327.3mV  690.5uA    396.8uA    556.8uA
-218.2mV  104.2uA    49.84uA    76.16uA
0V        110.7nA    133.6nA    263.4nA
[GND_clamp]
|   voltage   I(typ)   I(min)   I(max)
-1.8V     -45.84mA   -42.45mA   -54.88mA
-1.655V   -39.23mA   -36.93mA   -46.76mA
-1.509V   -32.77mA   -31.45mA   -39.47mA
-1.327V   -25.11mA   -24.68mA   -31.64mA
-1.145V   -18.35mA   -18.07mA   -24.19mA
-927.3mV  -11.35mA   -10.59mA   -15.5mA
-781.8mV  -7.112mA   -6.235mA   -10.08mA
-636.4mV  -3.474mA   -2.848mA   -5.206mA
-490.9mV  -889.6uA   -748.3uA   -1.49mA
-381.8mV  -136uA     -148.6uA   -241.8uA
-272.7mV  -12.55uA   -20.62uA   -15.52uA
1.764V    38.35nA    927.7nA    122.5nA
